VERSION 5.7 ;
  NOWIREEXTENSIONATPIN ON ;
  DIVIDERCHAR "/" ;
  BUSBITCHARS "[]" ;
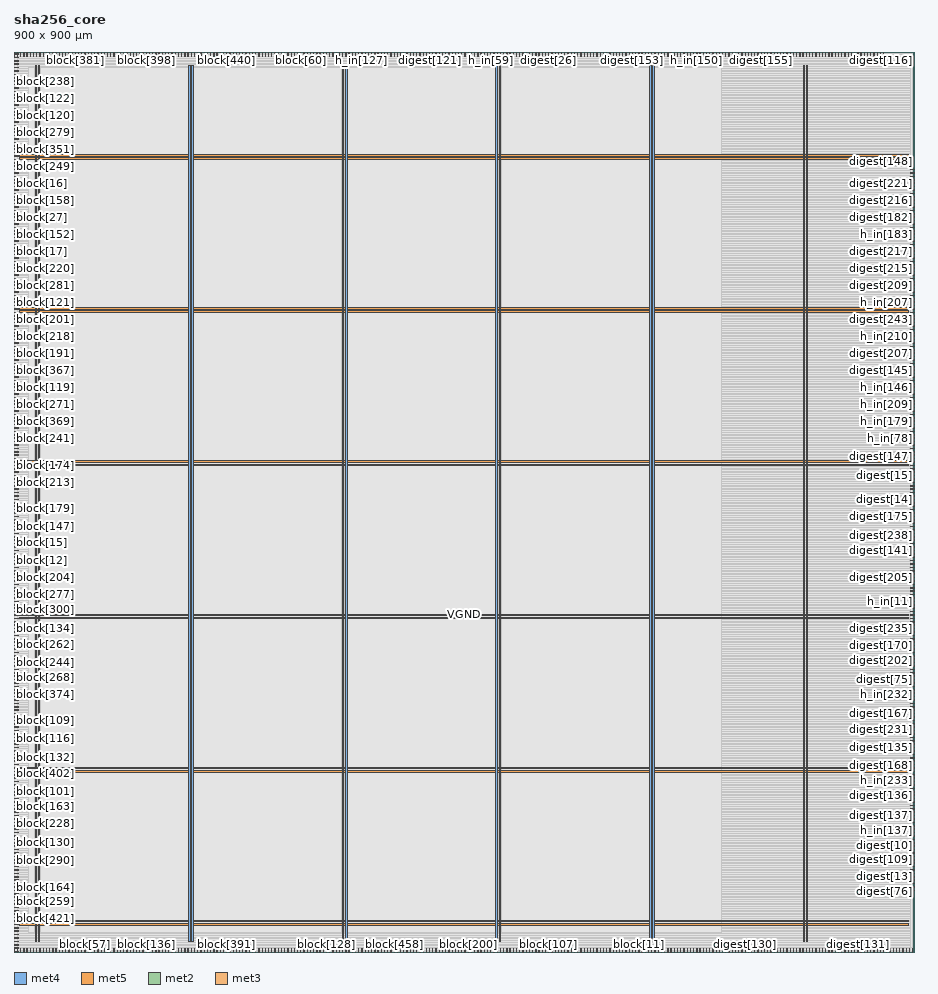
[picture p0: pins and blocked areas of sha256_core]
MACRO sha256_core
  CLASS BLOCK ;
  FOREIGN sha256_core ;
  ORIGIN 0.000 0.000 ;
  SIZE 900.000 BY 900.000 ;
  PIN VGND
    DIRECTION INOUT ;
    USE GROUND ;
    PORT
      LAYER met4 ;
        RECT 24.340 10.640 25.940 886.960 ;
    END
    PORT
      LAYER met4 ;
        RECT 177.940 10.640 179.540 886.960 ;
    END
    PORT
      LAYER met4 ;
        RECT 331.540 10.640 333.140 886.960 ;
    END
    PORT
      LAYER met4 ;
        RECT 485.140 10.640 486.740 886.960 ;
    END
    PORT
      LAYER met4 ;
        RECT 638.740 10.640 640.340 886.960 ;
    END
    PORT
      LAYER met4 ;
        RECT 792.340 10.640 793.940 886.960 ;
    END
    PORT
      LAYER met5 ;
        RECT 5.280 30.030 894.480 31.630 ;
    END
    PORT
      LAYER met5 ;
        RECT 5.280 183.210 894.480 184.810 ;
    END
    PORT
      LAYER met5 ;
        RECT 5.280 336.390 894.480 337.990 ;
    END
    PORT
      LAYER met5 ;
        RECT 5.280 489.570 894.480 491.170 ;
    END
    PORT
      LAYER met5 ;
        RECT 5.280 642.750 894.480 644.350 ;
    END
    PORT
      LAYER met5 ;
        RECT 5.280 795.930 894.480 797.530 ;
    END
  END VGND
  PIN VPWR
    DIRECTION INOUT ;
    USE POWER ;
    PORT
      LAYER met4 ;
        RECT 21.040 10.640 22.640 886.960 ;
    END
    PORT
      LAYER met4 ;
        RECT 174.640 10.640 176.240 886.960 ;
    END
    PORT
      LAYER met4 ;
        RECT 328.240 10.640 329.840 886.960 ;
    END
    PORT
      LAYER met4 ;
        RECT 481.840 10.640 483.440 886.960 ;
    END
    PORT
      LAYER met4 ;
        RECT 635.440 10.640 637.040 886.960 ;
    END
    PORT
      LAYER met4 ;
        RECT 789.040 10.640 790.640 886.960 ;
    END
    PORT
      LAYER met5 ;
        RECT 5.280 26.730 894.480 28.330 ;
    END
    PORT
      LAYER met5 ;
        RECT 5.280 179.910 894.480 181.510 ;
    END
    PORT
      LAYER met5 ;
        RECT 5.280 333.090 894.480 334.690 ;
    END
    PORT
      LAYER met5 ;
        RECT 5.280 486.270 894.480 487.870 ;
    END
    PORT
      LAYER met5 ;
        RECT 5.280 639.450 894.480 641.050 ;
    END
    PORT
      LAYER met5 ;
        RECT 5.280 792.630 894.480 794.230 ;
    END
  END VPWR
  PIN block[0]
    DIRECTION INPUT ;
    USE SIGNAL ;
    ANTENNAGATEAREA 0.631200 ;
    ANTENNADIFFAREA 0.434700 ;
    PORT
      LAYER met2 ;
        RECT 296.330 0.000 296.610 4.000 ;
    END
  END block[0]
  PIN block[100]
    DIRECTION INPUT ;
    USE SIGNAL ;
    ANTENNAGATEAREA 0.631200 ;
    ANTENNADIFFAREA 0.434700 ;
    PORT
      LAYER met3 ;
        RECT 0.000 302.640 4.000 303.240 ;
    END
  END block[100]
  PIN block[101]
    DIRECTION INPUT ;
    USE SIGNAL ;
    ANTENNAGATEAREA 0.631200 ;
    ANTENNADIFFAREA 0.434700 ;
    PORT
      LAYER met3 ;
        RECT 0.000 159.840 4.000 160.440 ;
    END
  END block[101]
  PIN block[102]
    DIRECTION INPUT ;
    USE SIGNAL ;
    ANTENNAGATEAREA 0.631200 ;
    ANTENNADIFFAREA 0.434700 ;
    PORT
      LAYER met3 ;
        RECT 0.000 353.640 4.000 354.240 ;
    END
  END block[102]
  PIN block[103]
    DIRECTION INPUT ;
    USE SIGNAL ;
    ANTENNAGATEAREA 0.631200 ;
    ANTENNADIFFAREA 0.434700 ;
    PORT
      LAYER met2 ;
        RECT 180.410 0.000 180.690 4.000 ;
    END
  END block[103]
  PIN block[104]
    DIRECTION INPUT ;
    USE SIGNAL ;
    ANTENNAGATEAREA 0.631200 ;
    ANTENNADIFFAREA 0.434700 ;
    PORT
      LAYER met2 ;
        RECT 116.010 0.000 116.290 4.000 ;
    END
  END block[104]
  PIN block[105]
    DIRECTION INPUT ;
    USE SIGNAL ;
    ANTENNAGATEAREA 0.631200 ;
    ANTENNADIFFAREA 0.434700 ;
    PORT
      LAYER met3 ;
        RECT 0.000 639.240 4.000 639.840 ;
    END
  END block[105]
  PIN block[106]
    DIRECTION INPUT ;
    USE SIGNAL ;
    ANTENNAGATEAREA 0.631200 ;
    ANTENNADIFFAREA 0.434700 ;
    PORT
      LAYER met3 ;
        RECT 0.000 887.440 4.000 888.040 ;
    END
  END block[106]
  PIN block[107]
    DIRECTION INPUT ;
    USE SIGNAL ;
    ANTENNAGATEAREA 0.631200 ;
    ANTENNADIFFAREA 0.434700 ;
    PORT
      LAYER met2 ;
        RECT 534.610 0.000 534.890 4.000 ;
    END
  END block[107]
  PIN block[108]
    DIRECTION INPUT ;
    USE SIGNAL ;
    ANTENNAGATEAREA 0.631200 ;
    ANTENNADIFFAREA 0.434700 ;
    PORT
      LAYER met3 ;
        RECT 0.000 377.440 4.000 378.040 ;
    END
  END block[108]
  PIN block[109]
    DIRECTION INPUT ;
    USE SIGNAL ;
    ANTENNAGATEAREA 0.631200 ;
    ANTENNADIFFAREA 0.434700 ;
    PORT
      LAYER met3 ;
        RECT 0.000 231.240 4.000 231.840 ;
    END
  END block[109]
  PIN block[10]
    DIRECTION INPUT ;
    USE SIGNAL ;
    ANTENNAGATEAREA 0.647700 ;
    ANTENNADIFFAREA 0.434700 ;
    PORT
      LAYER met2 ;
        RECT 344.630 0.000 344.910 4.000 ;
    END
  END block[10]
  PIN block[110]
    DIRECTION INPUT ;
    USE SIGNAL ;
    ANTENNAGATEAREA 0.631200 ;
    ANTENNADIFFAREA 0.434700 ;
    PORT
      LAYER met3 ;
        RECT 0.000 499.840 4.000 500.440 ;
    END
  END block[110]
  PIN block[111]
    DIRECTION INPUT ;
    USE SIGNAL ;
    ANTENNAGATEAREA 0.631200 ;
    ANTENNADIFFAREA 0.434700 ;
    PORT
      LAYER met3 ;
        RECT 0.000 676.640 4.000 677.240 ;
    END
  END block[111]
  PIN block[112]
    DIRECTION INPUT ;
    USE SIGNAL ;
    ANTENNAGATEAREA 0.631200 ;
    ANTENNADIFFAREA 0.434700 ;
    PORT
      LAYER met3 ;
        RECT 0.000 557.640 4.000 558.240 ;
    END
  END block[112]
  PIN block[113]
    DIRECTION INPUT ;
    USE SIGNAL ;
    ANTENNAGATEAREA 0.631200 ;
    ANTENNADIFFAREA 0.434700 ;
    PORT
      LAYER met3 ;
        RECT 0.000 523.640 4.000 524.240 ;
    END
  END block[113]
  PIN block[114]
    DIRECTION INPUT ;
    USE SIGNAL ;
    ANTENNAGATEAREA 0.631200 ;
    ANTENNADIFFAREA 0.434700 ;
    PORT
      LAYER met3 ;
        RECT 0.000 380.840 4.000 381.440 ;
    END
  END block[114]
  PIN block[115]
    DIRECTION INPUT ;
    USE SIGNAL ;
    ANTENNAGATEAREA 0.631200 ;
    ANTENNADIFFAREA 0.434700 ;
    PORT
      LAYER met3 ;
        RECT 0.000 363.840 4.000 364.440 ;
    END
  END block[115]
  PIN block[116]
    DIRECTION INPUT ;
    USE SIGNAL ;
    ANTENNAGATEAREA 0.631200 ;
    ANTENNADIFFAREA 0.434700 ;
    PORT
      LAYER met3 ;
        RECT 0.000 221.040 4.000 221.640 ;
    END
  END block[116]
  PIN block[117]
    DIRECTION INPUT ;
    USE SIGNAL ;
    ANTENNAGATEAREA 0.631200 ;
    ANTENNADIFFAREA 0.434700 ;
    PORT
      LAYER met3 ;
        RECT 0.000 496.440 4.000 497.040 ;
    END
  END block[117]
  PIN block[118]
    DIRECTION INPUT ;
    USE SIGNAL ;
    ANTENNAGATEAREA 0.631200 ;
    ANTENNADIFFAREA 0.434700 ;
    PORT
      LAYER met3 ;
        RECT 0.000 438.640 4.000 439.240 ;
    END
  END block[118]
  PIN block[119]
    DIRECTION INPUT ;
    USE SIGNAL ;
    ANTENNAGATEAREA 0.631200 ;
    ANTENNADIFFAREA 0.434700 ;
    PORT
      LAYER met3 ;
        RECT 0.000 564.440 4.000 565.040 ;
    END
  END block[119]
  PIN block[11]
    DIRECTION INPUT ;
    USE SIGNAL ;
    ANTENNAGATEAREA 0.593700 ;
    ANTENNADIFFAREA 0.434700 ;
    PORT
      LAYER met2 ;
        RECT 624.770 0.000 625.050 4.000 ;
    END
  END block[11]
  PIN block[120]
    DIRECTION INPUT ;
    USE SIGNAL ;
    ANTENNAGATEAREA 0.631200 ;
    ANTENNADIFFAREA 0.434700 ;
    PORT
      LAYER met3 ;
        RECT 0.000 836.440 4.000 837.040 ;
    END
  END block[120]
  PIN block[121]
    DIRECTION INPUT ;
    USE SIGNAL ;
    ANTENNAGATEAREA 0.631200 ;
    ANTENNADIFFAREA 0.434700 ;
    PORT
      LAYER met3 ;
        RECT 0.000 649.440 4.000 650.040 ;
    END
  END block[121]
  PIN block[122]
    DIRECTION INPUT ;
    USE SIGNAL ;
    ANTENNAGATEAREA 0.631200 ;
    ANTENNADIFFAREA 0.434700 ;
    PORT
      LAYER met3 ;
        RECT 0.000 853.440 4.000 854.040 ;
    END
  END block[122]
  PIN block[123]
    DIRECTION INPUT ;
    USE SIGNAL ;
    ANTENNAGATEAREA 0.631200 ;
    ANTENNADIFFAREA 0.434700 ;
    PORT
      LAYER met2 ;
        RECT 225.490 896.000 225.770 900.000 ;
    END
  END block[123]
  PIN block[124]
    DIRECTION INPUT ;
    USE SIGNAL ;
    ANTENNAGATEAREA 0.631200 ;
    ANTENNADIFFAREA 0.434700 ;
    PORT
      LAYER met3 ;
        RECT 0.000 765.040 4.000 765.640 ;
    END
  END block[124]
  PIN block[125]
    DIRECTION INPUT ;
    USE SIGNAL ;
    ANTENNAGATEAREA 0.631200 ;
    ANTENNADIFFAREA 0.434700 ;
    PORT
      LAYER met2 ;
        RECT 167.530 896.000 167.810 900.000 ;
    END
  END block[125]
  PIN block[126]
    DIRECTION INPUT ;
    USE SIGNAL ;
    ANTENNAGATEAREA 0.631200 ;
    ANTENNADIFFAREA 0.434700 ;
    PORT
      LAYER met3 ;
        RECT 0.000 646.040 4.000 646.640 ;
    END
  END block[126]
  PIN block[127]
    DIRECTION INPUT ;
    USE SIGNAL ;
    ANTENNAGATEAREA 0.631200 ;
    ANTENNADIFFAREA 0.434700 ;
    PORT
      LAYER met3 ;
        RECT 0.000 686.840 4.000 687.440 ;
    END
  END block[127]
  PIN block[128]
    DIRECTION INPUT ;
    USE SIGNAL ;
    ANTENNAGATEAREA 0.631200 ;
    ANTENNADIFFAREA 0.434700 ;
    PORT
      LAYER met2 ;
        RECT 312.430 0.000 312.710 4.000 ;
    END
  END block[128]
  PIN block[129]
    DIRECTION INPUT ;
    USE SIGNAL ;
    ANTENNAGATEAREA 0.631200 ;
    ANTENNADIFFAREA 0.434700 ;
    PORT
      LAYER met2 ;
        RECT 106.350 0.000 106.630 4.000 ;
    END
  END block[129]
  PIN block[12]
    DIRECTION INPUT ;
    USE SIGNAL ;
    ANTENNAGATEAREA 0.631200 ;
    ANTENNADIFFAREA 0.434700 ;
    PORT
      LAYER met3 ;
        RECT 0.000 391.040 4.000 391.640 ;
    END
  END block[12]
  PIN block[130]
    DIRECTION INPUT ;
    USE SIGNAL ;
    ANTENNAGATEAREA 0.560700 ;
    ANTENNADIFFAREA 0.434700 ;
    PORT
      LAYER met3 ;
        RECT 0.000 108.840 4.000 109.440 ;
    END
  END block[130]
  PIN block[131]
    DIRECTION INPUT ;
    USE SIGNAL ;
    ANTENNAGATEAREA 0.631200 ;
    ANTENNADIFFAREA 0.434700 ;
    PORT
      LAYER met3 ;
        RECT 0.000 37.440 4.000 38.040 ;
    END
  END block[131]
  PIN block[132]
    DIRECTION INPUT ;
    USE SIGNAL ;
    ANTENNAGATEAREA 0.631200 ;
    ANTENNADIFFAREA 0.434700 ;
    PORT
      LAYER met3 ;
        RECT 0.000 193.840 4.000 194.440 ;
    END
  END block[132]
  PIN block[133]
    DIRECTION INPUT ;
    USE SIGNAL ;
    ANTENNAGATEAREA 0.631200 ;
    ANTENNADIFFAREA 0.434700 ;
    PORT
      LAYER met3 ;
        RECT 0.000 197.240 4.000 197.840 ;
    END
  END block[133]
  PIN block[134]
    DIRECTION INPUT ;
    USE SIGNAL ;
    ANTENNAGATEAREA 0.631200 ;
    ANTENNADIFFAREA 0.434700 ;
    PORT
      LAYER met3 ;
        RECT 0.000 323.040 4.000 323.640 ;
    END
  END block[134]
  PIN block[135]
    DIRECTION INPUT ;
    USE SIGNAL ;
    ANTENNAGATEAREA 0.631200 ;
    ANTENNADIFFAREA 0.434700 ;
    PORT
      LAYER met2 ;
        RECT 58.050 0.000 58.330 4.000 ;
    END
  END block[135]
  PIN block[136]
    DIRECTION INPUT ;
    USE SIGNAL ;
    ANTENNAGATEAREA 0.631200 ;
    ANTENNADIFFAREA 0.434700 ;
    PORT
      LAYER met2 ;
        RECT 132.110 0.000 132.390 4.000 ;
    END
  END block[136]
  PIN block[137]
    DIRECTION INPUT ;
    USE SIGNAL ;
    ANTENNAGATEAREA 0.631200 ;
    ANTENNADIFFAREA 0.434700 ;
    PORT
      LAYER met3 ;
        RECT 0.000 778.640 4.000 779.240 ;
    END
  END block[137]
  PIN block[138]
    DIRECTION INPUT ;
    USE SIGNAL ;
    ANTENNAGATEAREA 0.631200 ;
    ANTENNADIFFAREA 0.434700 ;
    PORT
      LAYER met3 ;
        RECT 0.000 884.040 4.000 884.640 ;
    END
  END block[138]
  PIN block[139]
    DIRECTION INPUT ;
    USE SIGNAL ;
    ANTENNAGATEAREA 0.631200 ;
    ANTENNADIFFAREA 0.434700 ;
    PORT
      LAYER met2 ;
        RECT 502.410 0.000 502.690 4.000 ;
    END
  END block[139]
  PIN block[13]
    DIRECTION INPUT ;
    USE SIGNAL ;
    ANTENNAGATEAREA 0.647700 ;
    ANTENNADIFFAREA 0.434700 ;
    PORT
      LAYER met2 ;
        RECT 29.070 0.000 29.350 4.000 ;
    END
  END block[13]
  PIN block[140]
    DIRECTION INPUT ;
    USE SIGNAL ;
    ANTENNAGATEAREA 0.631200 ;
    ANTENNADIFFAREA 0.434700 ;
    PORT
      LAYER met3 ;
        RECT 0.000 258.440 4.000 259.040 ;
    END
  END block[140]
  PIN block[141]
    DIRECTION INPUT ;
    USE SIGNAL ;
    ANTENNAGATEAREA 0.631200 ;
    ANTENNADIFFAREA 0.434700 ;
    PORT
      LAYER met3 ;
        RECT 0.000 414.840 4.000 415.440 ;
    END
  END block[141]
  PIN block[142]
    DIRECTION INPUT ;
    USE SIGNAL ;
    ANTENNAGATEAREA 0.631200 ;
    ANTENNADIFFAREA 0.434700 ;
    PORT
      LAYER met3 ;
        RECT 0.000 489.640 4.000 490.240 ;
    END
  END block[142]
  PIN block[143]
    DIRECTION INPUT ;
    USE SIGNAL ;
    ANTENNAGATEAREA 0.631200 ;
    ANTENNADIFFAREA 0.434700 ;
    PORT
      LAYER met3 ;
        RECT 0.000 714.040 4.000 714.640 ;
    END
  END block[143]
  PIN block[144]
    DIRECTION INPUT ;
    USE SIGNAL ;
    ANTENNAGATEAREA 0.631200 ;
    ANTENNADIFFAREA 0.434700 ;
    PORT
      LAYER met3 ;
        RECT 0.000 591.640 4.000 592.240 ;
    END
  END block[144]
  PIN block[145]
    DIRECTION INPUT ;
    USE SIGNAL ;
    ANTENNAGATEAREA 0.647700 ;
    ANTENNADIFFAREA 0.434700 ;
    PORT
      LAYER met3 ;
        RECT 0.000 748.040 4.000 748.640 ;
    END
  END block[145]
  PIN block[146]
    DIRECTION INPUT ;
    USE SIGNAL ;
    ANTENNAGATEAREA 0.631200 ;
    ANTENNADIFFAREA 0.434700 ;
    PORT
      LAYER met3 ;
        RECT 0.000 244.840 4.000 245.440 ;
    END
  END block[146]
  PIN block[147]
    DIRECTION INPUT ;
    USE SIGNAL ;
    ANTENNAGATEAREA 0.631200 ;
    ANTENNADIFFAREA 0.434700 ;
    PORT
      LAYER met3 ;
        RECT 0.000 425.040 4.000 425.640 ;
    END
  END block[147]
  PIN block[148]
    DIRECTION INPUT ;
    USE SIGNAL ;
    ANTENNAGATEAREA 0.631200 ;
    ANTENNADIFFAREA 0.434700 ;
    PORT
      LAYER met3 ;
        RECT 0.000 319.640 4.000 320.240 ;
    END
  END block[148]
  PIN block[149]
    DIRECTION INPUT ;
    USE SIGNAL ;
    ANTENNAGATEAREA 0.631200 ;
    ANTENNADIFFAREA 0.434700 ;
    PORT
      LAYER met3 ;
        RECT 0.000 472.640 4.000 473.240 ;
    END
  END block[149]
  PIN block[14]
    DIRECTION INPUT ;
    USE SIGNAL ;
    ANTENNAGATEAREA 0.631200 ;
    ANTENNADIFFAREA 0.434700 ;
    PORT
      LAYER met3 ;
        RECT 0.000 411.440 4.000 412.040 ;
    END
  END block[14]
  PIN block[150]
    DIRECTION INPUT ;
    USE SIGNAL ;
    ANTENNAGATEAREA 0.631200 ;
    ANTENNADIFFAREA 0.434700 ;
    PORT
      LAYER met3 ;
        RECT 0.000 251.640 4.000 252.240 ;
    END
  END block[150]
  PIN block[151]
    DIRECTION INPUT ;
    USE SIGNAL ;
    ANTENNAGATEAREA 0.631200 ;
    ANTENNADIFFAREA 0.434700 ;
    PORT
      LAYER met3 ;
        RECT 0.000 588.240 4.000 588.840 ;
    END
  END block[151]
  PIN block[152]
    DIRECTION INPUT ;
    USE SIGNAL ;
    ANTENNAGATEAREA 0.631200 ;
    ANTENNADIFFAREA 0.434700 ;
    PORT
      LAYER met3 ;
        RECT 0.000 717.440 4.000 718.040 ;
    END
  END block[152]
  PIN block[153]
    DIRECTION INPUT ;
    USE SIGNAL ;
    ANTENNAGATEAREA 0.631200 ;
    ANTENNADIFFAREA 0.434700 ;
    PORT
      LAYER met3 ;
        RECT 0.000 839.840 4.000 840.440 ;
    END
  END block[153]
  PIN block[154]
    DIRECTION INPUT ;
    USE SIGNAL ;
    ANTENNAGATEAREA 0.631200 ;
    ANTENNADIFFAREA 0.434700 ;
    PORT
      LAYER met3 ;
        RECT 0.000 799.040 4.000 799.640 ;
    END
  END block[154]
  PIN block[155]
    DIRECTION INPUT ;
    USE SIGNAL ;
    ANTENNAGATEAREA 0.631200 ;
    ANTENNADIFFAREA 0.434700 ;
    PORT
      LAYER met2 ;
        RECT 151.430 896.000 151.710 900.000 ;
    END
  END block[155]
  PIN block[156]
    DIRECTION INPUT ;
    USE SIGNAL ;
    ANTENNAGATEAREA 0.631200 ;
    ANTENNADIFFAREA 0.434700 ;
    PORT
      LAYER met3 ;
        RECT 0.000 826.240 4.000 826.840 ;
    END
  END block[156]
  PIN block[157]
    DIRECTION INPUT ;
    USE SIGNAL ;
    ANTENNAGATEAREA 0.631200 ;
    ANTENNADIFFAREA 0.434700 ;
    PORT
      LAYER met2 ;
        RECT 64.490 896.000 64.770 900.000 ;
    END
  END block[157]
  PIN block[158]
    DIRECTION INPUT ;
    USE SIGNAL ;
    ANTENNAGATEAREA 0.631200 ;
    ANTENNADIFFAREA 0.434700 ;
    PORT
      LAYER met3 ;
        RECT 0.000 751.440 4.000 752.040 ;
    END
  END block[158]
  PIN block[159]
    DIRECTION INPUT ;
    USE SIGNAL ;
    ANTENNAGATEAREA 0.631200 ;
    ANTENNADIFFAREA 0.434700 ;
    PORT
      LAYER met3 ;
        RECT 0.000 822.840 4.000 823.440 ;
    END
  END block[159]
  PIN block[15]
    DIRECTION INPUT ;
    USE SIGNAL ;
    ANTENNAGATEAREA 0.631200 ;
    ANTENNADIFFAREA 0.434700 ;
    PORT
      LAYER met3 ;
        RECT 0.000 401.240 4.000 401.840 ;
    END
  END block[15]
  PIN block[160]
    DIRECTION INPUT ;
    USE SIGNAL ;
    ANTENNAGATEAREA 0.631200 ;
    ANTENNADIFFAREA 0.434700 ;
    PORT
      LAYER met2 ;
        RECT 360.730 0.000 361.010 4.000 ;
    END
  END block[160]
  PIN block[161]
    DIRECTION INPUT ;
    USE SIGNAL ;
    ANTENNAGATEAREA 0.631200 ;
    ANTENNADIFFAREA 0.434700 ;
    PORT
      LAYER met2 ;
        RECT 186.850 0.000 187.130 4.000 ;
    END
  END block[161]
  PIN block[162]
    DIRECTION INPUT ;
    USE SIGNAL ;
    ANTENNAGATEAREA 0.631200 ;
    ANTENNADIFFAREA 0.434700 ;
    PORT
      LAYER met2 ;
        RECT 209.390 0.000 209.670 4.000 ;
    END
  END block[162]
  PIN block[163]
    DIRECTION INPUT ;
    USE SIGNAL ;
    ANTENNAGATEAREA 0.631200 ;
    ANTENNADIFFAREA 0.434700 ;
    PORT
      LAYER met3 ;
        RECT 0.000 153.040 4.000 153.640 ;
    END
  END block[163]
  PIN block[164]
    DIRECTION INPUT ;
    USE SIGNAL ;
    ANTENNAGATEAREA 0.631200 ;
    ANTENNADIFFAREA 0.434700 ;
    PORT
      LAYER met3 ;
        RECT 0.000 64.640 4.000 65.240 ;
    END
  END block[164]
  PIN block[165]
    DIRECTION INPUT ;
    USE SIGNAL ;
    ANTENNAGATEAREA 0.631200 ;
    ANTENNADIFFAREA 0.434700 ;
    PORT
      LAYER met3 ;
        RECT 0.000 6.840 4.000 7.440 ;
    END
  END block[165]
  PIN block[166]
    DIRECTION INPUT ;
    USE SIGNAL ;
    ANTENNAGATEAREA 0.631200 ;
    ANTENNADIFFAREA 0.434700 ;
    PORT
      LAYER met3 ;
        RECT 0.000 309.440 4.000 310.040 ;
    END
  END block[166]
  PIN block[167]
    DIRECTION INPUT ;
    USE SIGNAL ;
    ANTENNAGATEAREA 0.631200 ;
    ANTENNADIFFAREA 0.434700 ;
    PORT
      LAYER met2 ;
        RECT 51.610 0.000 51.890 4.000 ;
    END
  END block[167]
  PIN block[168]
    DIRECTION INPUT ;
    USE SIGNAL ;
    ANTENNAGATEAREA 0.631200 ;
    ANTENNADIFFAREA 0.434700 ;
    PORT
      LAYER met2 ;
        RECT 325.310 0.000 325.590 4.000 ;
    END
  END block[168]
  PIN block[169]
    DIRECTION INPUT ;
    USE SIGNAL ;
    ANTENNAGATEAREA 0.631200 ;
    ANTENNADIFFAREA 0.434700 ;
    PORT
      LAYER met3 ;
        RECT 0.000 856.840 4.000 857.440 ;
    END
  END block[169]
  PIN block[16]
    DIRECTION INPUT ;
    USE SIGNAL ;
    ANTENNAGATEAREA 0.593700 ;
    ANTENNADIFFAREA 0.434700 ;
    PORT
      LAYER met3 ;
        RECT 0.000 768.440 4.000 769.040 ;
    END
  END block[16]
  PIN block[170]
    DIRECTION INPUT ;
    USE SIGNAL ;
    ANTENNAGATEAREA 0.631200 ;
    ANTENNADIFFAREA 0.434700 ;
    PORT
      LAYER met3 ;
        RECT 0.000 867.040 4.000 867.640 ;
    END
  END block[170]
  PIN block[171]
    DIRECTION INPUT ;
    USE SIGNAL ;
    ANTENNAGATEAREA 0.631200 ;
    ANTENNADIFFAREA 0.434700 ;
    PORT
      LAYER met2 ;
        RECT 611.890 0.000 612.170 4.000 ;
    END
  END block[171]
  PIN block[172]
    DIRECTION INPUT ;
    USE SIGNAL ;
    ANTENNAGATEAREA 0.631200 ;
    ANTENNADIFFAREA 0.434700 ;
    PORT
      LAYER met3 ;
        RECT 0.000 268.640 4.000 269.240 ;
    END
  END block[172]
  PIN block[173]
    DIRECTION INPUT ;
    USE SIGNAL ;
    ANTENNAGATEAREA 0.631200 ;
    ANTENNADIFFAREA 0.434700 ;
    PORT
      LAYER met3 ;
        RECT 0.000 404.640 4.000 405.240 ;
    END
  END block[173]
  PIN block[174]
    DIRECTION INPUT ;
    USE SIGNAL ;
    ANTENNAGATEAREA 0.631200 ;
    ANTENNADIFFAREA 0.434700 ;
    PORT
      LAYER met3 ;
        RECT 0.000 486.240 4.000 486.840 ;
    END
  END block[174]
  PIN block[175]
    DIRECTION INPUT ;
    USE SIGNAL ;
    ANTENNAGATEAREA 0.631200 ;
    ANTENNADIFFAREA 0.434700 ;
    PORT
      LAYER met3 ;
        RECT 0.000 537.240 4.000 537.840 ;
    END
  END block[175]
  PIN block[176]
    DIRECTION INPUT ;
    USE SIGNAL ;
    ANTENNAGATEAREA 0.631200 ;
    ANTENNADIFFAREA 0.434700 ;
    PORT
      LAYER met3 ;
        RECT 0.000 550.840 4.000 551.440 ;
    END
  END block[176]
  PIN block[177]
    DIRECTION INPUT ;
    USE SIGNAL ;
    ANTENNAGATEAREA 0.631200 ;
    ANTENNADIFFAREA 0.434700 ;
    PORT
      LAYER met3 ;
        RECT 0.000 516.840 4.000 517.440 ;
    END
  END block[177]
  PIN block[178]
    DIRECTION INPUT ;
    USE SIGNAL ;
    ANTENNAGATEAREA 0.631200 ;
    ANTENNADIFFAREA 0.434700 ;
    PORT
      LAYER met3 ;
        RECT 0.000 238.040 4.000 238.640 ;
    END
  END block[178]
  PIN block[179]
    DIRECTION INPUT ;
    USE SIGNAL ;
    ANTENNAGATEAREA 0.631200 ;
    ANTENNADIFFAREA 0.434700 ;
    PORT
      LAYER met3 ;
        RECT 0.000 435.240 4.000 435.840 ;
    END
  END block[179]
  PIN block[17]
    DIRECTION INPUT ;
    USE SIGNAL ;
    ANTENNAGATEAREA 0.631200 ;
    ANTENNADIFFAREA 0.434700 ;
    PORT
      LAYER met3 ;
        RECT 0.000 700.440 4.000 701.040 ;
    END
  END block[17]
  PIN block[180]
    DIRECTION INPUT ;
    USE SIGNAL ;
    ANTENNAGATEAREA 0.631200 ;
    ANTENNADIFFAREA 0.434700 ;
    PORT
      LAYER met3 ;
        RECT 0.000 227.840 4.000 228.440 ;
    END
  END block[180]
  PIN block[181]
    DIRECTION INPUT ;
    USE SIGNAL ;
    ANTENNAGATEAREA 0.593700 ;
    ANTENNADIFFAREA 0.434700 ;
    PORT
      LAYER met3 ;
        RECT 0.000 897.640 4.000 898.240 ;
    END
  END block[181]
  PIN block[182]
    DIRECTION INPUT ;
    USE SIGNAL ;
    ANTENNAGATEAREA 0.631200 ;
    ANTENNADIFFAREA 0.434700 ;
    PORT
      LAYER met3 ;
        RECT 0.000 397.840 4.000 398.440 ;
    END
  END block[182]
  PIN block[183]
    DIRECTION INPUT ;
    USE SIGNAL ;
    ANTENNAGATEAREA 0.631200 ;
    ANTENNADIFFAREA 0.434700 ;
    PORT
      LAYER met3 ;
        RECT 0.000 578.040 4.000 578.640 ;
    END
  END block[183]
  PIN block[184]
    DIRECTION INPUT ;
    USE SIGNAL ;
    ANTENNAGATEAREA 0.631200 ;
    ANTENNADIFFAREA 0.434700 ;
    PORT
      LAYER met3 ;
        RECT 0.000 710.640 4.000 711.240 ;
    END
  END block[184]
  PIN block[185]
    DIRECTION INPUT ;
    USE SIGNAL ;
    ANTENNAGATEAREA 0.631200 ;
    ANTENNADIFFAREA 0.434700 ;
    PORT
      LAYER met3 ;
        RECT 0.000 843.240 4.000 843.840 ;
    END
  END block[185]
  PIN block[186]
    DIRECTION INPUT ;
    USE SIGNAL ;
    ANTENNAGATEAREA 0.631200 ;
    ANTENNADIFFAREA 0.434700 ;
    PORT
      LAYER met3 ;
        RECT 0.000 680.040 4.000 680.640 ;
    END
  END block[186]
  PIN block[187]
    DIRECTION INPUT ;
    USE SIGNAL ;
    ANTENNAGATEAREA 0.631200 ;
    ANTENNADIFFAREA 0.434700 ;
    PORT
      LAYER met2 ;
        RECT 29.070 896.000 29.350 900.000 ;
    END
  END block[187]
  PIN block[188]
    DIRECTION INPUT ;
    USE SIGNAL ;
    ANTENNAGATEAREA 0.631200 ;
    ANTENNADIFFAREA 0.434700 ;
    PORT
      LAYER met3 ;
        RECT 0.000 761.640 4.000 762.240 ;
    END
  END block[188]
  PIN block[189]
    DIRECTION INPUT ;
    USE SIGNAL ;
    ANTENNAGATEAREA 0.631200 ;
    ANTENNADIFFAREA 0.434700 ;
    PORT
      LAYER met2 ;
        RECT 48.390 896.000 48.670 900.000 ;
    END
  END block[189]
  PIN block[18]
    DIRECTION INPUT ;
    USE SIGNAL ;
    ANTENNAGATEAREA 0.593700 ;
    ANTENNADIFFAREA 0.434700 ;
    PORT
      LAYER met3 ;
        RECT 0.000 690.240 4.000 690.840 ;
    END
  END block[18]
  PIN block[190]
    DIRECTION INPUT ;
    USE SIGNAL ;
    ANTENNAGATEAREA 0.631200 ;
    ANTENNADIFFAREA 0.434700 ;
    PORT
      LAYER met3 ;
        RECT 0.000 795.640 4.000 796.240 ;
    END
  END block[190]
  PIN block[191]
    DIRECTION INPUT ;
    USE SIGNAL ;
    ANTENNAGATEAREA 0.631200 ;
    ANTENNADIFFAREA 0.434700 ;
    PORT
      LAYER met3 ;
        RECT 0.000 598.440 4.000 599.040 ;
    END
  END block[191]
  PIN block[192]
    DIRECTION INPUT ;
    USE SIGNAL ;
    ANTENNAGATEAREA 0.631200 ;
    ANTENNADIFFAREA 0.434700 ;
    PORT
      LAYER met2 ;
        RECT 396.150 0.000 396.430 4.000 ;
    END
  END block[192]
  PIN block[193]
    DIRECTION INPUT ;
    USE SIGNAL ;
    ANTENNAGATEAREA 0.631200 ;
    ANTENNADIFFAREA 0.434700 ;
    PORT
      LAYER met2 ;
        RECT 257.690 0.000 257.970 4.000 ;
    END
  END block[193]
  PIN block[194]
    DIRECTION INPUT ;
    USE SIGNAL ;
    ANTENNAGATEAREA 0.631200 ;
    ANTENNADIFFAREA 0.434700 ;
    PORT
      LAYER met2 ;
        RECT 125.670 0.000 125.950 4.000 ;
    END
  END block[194]
  PIN block[195]
    DIRECTION INPUT ;
    USE SIGNAL ;
    ANTENNAGATEAREA 0.631200 ;
    ANTENNADIFFAREA 0.434700 ;
    PORT
      LAYER met3 ;
        RECT 0.000 44.240 4.000 44.840 ;
    END
  END block[195]
  PIN block[196]
    DIRECTION INPUT ;
    USE SIGNAL ;
    ANTENNAGATEAREA 0.631200 ;
    ANTENNADIFFAREA 0.434700 ;
    PORT
      LAYER met3 ;
        RECT 0.000 78.240 4.000 78.840 ;
    END
  END block[196]
  PIN block[197]
    DIRECTION INPUT ;
    USE SIGNAL ;
    ANTENNAGATEAREA 0.631200 ;
    ANTENNADIFFAREA 0.434700 ;
    PORT
      LAYER met3 ;
        RECT 0.000 183.640 4.000 184.240 ;
    END
  END block[197]
  PIN block[198]
    DIRECTION INPUT ;
    USE SIGNAL ;
    ANTENNAGATEAREA 0.631200 ;
    ANTENNADIFFAREA 0.434700 ;
    PORT
      LAYER met3 ;
        RECT 0.000 292.440 4.000 293.040 ;
    END
  END block[198]
  PIN block[199]
    DIRECTION INPUT ;
    USE SIGNAL ;
    ANTENNAGATEAREA 0.631200 ;
    ANTENNADIFFAREA 0.434700 ;
    PORT
      LAYER met2 ;
        RECT 222.270 0.000 222.550 4.000 ;
    END
  END block[199]
  PIN block[19]
    DIRECTION INPUT ;
    USE SIGNAL ;
    ANTENNAGATEAREA 0.647700 ;
    ANTENNADIFFAREA 0.434700 ;
    PORT
      LAYER met3 ;
        RECT 0.000 860.240 4.000 860.840 ;
    END
  END block[19]
  PIN block[1]
    DIRECTION INPUT ;
    USE SIGNAL ;
    ANTENNAGATEAREA 0.631200 ;
    ANTENNADIFFAREA 0.434700 ;
    PORT
      LAYER met2 ;
        RECT 80.590 0.000 80.870 4.000 ;
    END
  END block[1]
  PIN block[200]
    DIRECTION INPUT ;
    USE SIGNAL ;
    ANTENNAGATEAREA 0.631200 ;
    ANTENNADIFFAREA 0.434700 ;
    PORT
      LAYER met2 ;
        RECT 454.110 0.000 454.390 4.000 ;
    END
  END block[200]
  PIN block[201]
    DIRECTION INPUT ;
    USE SIGNAL ;
    ANTENNAGATEAREA 0.631200 ;
    ANTENNADIFFAREA 0.434700 ;
    PORT
      LAYER met3 ;
        RECT 0.000 632.440 4.000 633.040 ;
    END
  END block[201]
  PIN block[202]
    DIRECTION INPUT ;
    USE SIGNAL ;
    ANTENNAGATEAREA 0.631200 ;
    ANTENNADIFFAREA 0.434700 ;
    PORT
      LAYER met3 ;
        RECT 0.000 894.240 4.000 894.840 ;
    END
  END block[202]
  PIN block[203]
    DIRECTION INPUT ;
    USE SIGNAL ;
    ANTENNAGATEAREA 0.631200 ;
    ANTENNADIFFAREA 0.434700 ;
    PORT
      LAYER met2 ;
        RECT 615.110 0.000 615.390 4.000 ;
    END
  END block[203]
  PIN block[204]
    DIRECTION INPUT ;
    USE SIGNAL ;
    ANTENNAGATEAREA 0.631200 ;
    ANTENNADIFFAREA 0.434700 ;
    PORT
      LAYER met3 ;
        RECT 0.000 374.040 4.000 374.640 ;
    END
  END block[204]
  PIN block[205]
    DIRECTION INPUT ;
    USE SIGNAL ;
    ANTENNAGATEAREA 0.631200 ;
    ANTENNADIFFAREA 0.434700 ;
    PORT
      LAYER met3 ;
        RECT 0.000 428.440 4.000 429.040 ;
    END
  END block[205]
  PIN block[206]
    DIRECTION INPUT ;
    USE SIGNAL ;
    ANTENNAGATEAREA 0.631200 ;
    ANTENNADIFFAREA 0.434700 ;
    PORT
      LAYER met3 ;
        RECT 0.000 479.440 4.000 480.040 ;
    END
  END block[206]
  PIN block[207]
    DIRECTION INPUT ;
    USE SIGNAL ;
    ANTENNAGATEAREA 0.631200 ;
    ANTENNADIFFAREA 0.434700 ;
    PORT
      LAYER met3 ;
        RECT 0.000 788.840 4.000 789.440 ;
    END
  END block[207]
  PIN block[208]
    DIRECTION INPUT ;
    USE SIGNAL ;
    ANTENNAGATEAREA 0.631200 ;
    ANTENNADIFFAREA 0.434700 ;
    PORT
      LAYER met3 ;
        RECT 0.000 618.840 4.000 619.440 ;
    END
  END block[208]
  PIN block[209]
    DIRECTION INPUT ;
    USE SIGNAL ;
    ANTENNAGATEAREA 0.631200 ;
    ANTENNADIFFAREA 0.434700 ;
    PORT
      LAYER met3 ;
        RECT 0.000 510.040 4.000 510.640 ;
    END
  END block[209]
  PIN block[20]
    DIRECTION INPUT ;
    USE SIGNAL ;
    ANTENNAGATEAREA 0.631200 ;
    ANTENNADIFFAREA 0.434700 ;
    PORT
      LAYER met3 ;
        RECT 0.000 493.040 4.000 493.640 ;
    END
  END block[20]
  PIN block[210]
    DIRECTION INPUT ;
    USE SIGNAL ;
    ANTENNAGATEAREA 0.631200 ;
    ANTENNADIFFAREA 0.434700 ;
    PORT
      LAYER met3 ;
        RECT 0.000 336.640 4.000 337.240 ;
    END
  END block[210]
  PIN block[211]
    DIRECTION INPUT ;
    USE SIGNAL ;
    ANTENNAGATEAREA 0.631200 ;
    ANTENNADIFFAREA 0.434700 ;
    PORT
      LAYER met3 ;
        RECT 0.000 408.040 4.000 408.640 ;
    END
  END block[211]
  PIN block[212]
    DIRECTION INPUT ;
    USE SIGNAL ;
    ANTENNAGATEAREA 0.631200 ;
    ANTENNADIFFAREA 0.434700 ;
    PORT
      LAYER met3 ;
        RECT 0.000 312.840 4.000 313.440 ;
    END
  END block[212]
  PIN block[213]
    DIRECTION INPUT ;
    USE SIGNAL ;
    ANTENNAGATEAREA 0.631200 ;
    ANTENNADIFFAREA 0.434700 ;
    PORT
      LAYER met3 ;
        RECT 0.000 469.240 4.000 469.840 ;
    END
  END block[213]
  PIN block[214]
    DIRECTION INPUT ;
    USE SIGNAL ;
    ANTENNAGATEAREA 0.631200 ;
    ANTENNADIFFAREA 0.434700 ;
    PORT
      LAYER met3 ;
        RECT 0.000 421.640 4.000 422.240 ;
    END
  END block[214]
  PIN block[215]
    DIRECTION INPUT ;
    USE SIGNAL ;
    ANTENNAGATEAREA 0.631200 ;
    ANTENNADIFFAREA 0.434700 ;
    PORT
      LAYER met3 ;
        RECT 0.000 584.840 4.000 585.440 ;
    END
  END block[215]
  PIN block[216]
    DIRECTION INPUT ;
    USE SIGNAL ;
    ANTENNAGATEAREA 0.631200 ;
    ANTENNADIFFAREA 0.434700 ;
    PORT
      LAYER met3 ;
        RECT 0.000 697.040 4.000 697.640 ;
    END
  END block[216]
  PIN block[217]
    DIRECTION INPUT ;
    USE SIGNAL ;
    ANTENNAGATEAREA 0.631200 ;
    ANTENNADIFFAREA 0.434700 ;
    PORT
      LAYER met3 ;
        RECT 0.000 656.240 4.000 656.840 ;
    END
  END block[217]
  PIN block[218]
    DIRECTION INPUT ;
    USE SIGNAL ;
    ANTENNAGATEAREA 0.631200 ;
    ANTENNADIFFAREA 0.434700 ;
    PORT
      LAYER met3 ;
        RECT 0.000 615.440 4.000 616.040 ;
    END
  END block[218]
  PIN block[219]
    DIRECTION INPUT ;
    USE SIGNAL ;
    ANTENNAGATEAREA 0.631200 ;
    ANTENNADIFFAREA 0.434700 ;
    PORT
      LAYER met2 ;
        RECT 80.590 896.000 80.870 900.000 ;
    END
  END block[219]
  PIN block[21]
    DIRECTION INPUT ;
    USE SIGNAL ;
    ANTENNAGATEAREA 0.593700 ;
    ANTENNADIFFAREA 0.434700 ;
    PORT
      LAYER met3 ;
        RECT 0.000 608.640 4.000 609.240 ;
    END
  END block[21]
  PIN block[220]
    DIRECTION INPUT ;
    USE SIGNAL ;
    ANTENNAGATEAREA 0.631200 ;
    ANTENNADIFFAREA 0.434700 ;
    PORT
      LAYER met3 ;
        RECT 0.000 683.440 4.000 684.040 ;
    END
  END block[220]
  PIN block[221]
    DIRECTION INPUT ;
    USE SIGNAL ;
    ANTENNAGATEAREA 0.631200 ;
    ANTENNADIFFAREA 0.434700 ;
    PORT
      LAYER met2 ;
        RECT 209.390 896.000 209.670 900.000 ;
    END
  END block[221]
  PIN block[222]
    DIRECTION INPUT ;
    USE SIGNAL ;
    ANTENNAGATEAREA 0.631200 ;
    ANTENNADIFFAREA 0.434700 ;
    PORT
      LAYER met3 ;
        RECT 0.000 731.040 4.000 731.640 ;
    END
  END block[222]
  PIN block[223]
    DIRECTION INPUT ;
    USE SIGNAL ;
    ANTENNAGATEAREA 0.631200 ;
    ANTENNADIFFAREA 0.434700 ;
    PORT
      LAYER met3 ;
        RECT 0.000 629.040 4.000 629.640 ;
    END
  END block[223]
  PIN block[224]
    DIRECTION INPUT ;
    USE SIGNAL ;
    ANTENNAGATEAREA 0.631200 ;
    ANTENNADIFFAREA 0.434700 ;
    PORT
      LAYER met2 ;
        RECT 331.750 0.000 332.030 4.000 ;
    END
  END block[224]
  PIN block[225]
    DIRECTION INPUT ;
    USE SIGNAL ;
    ANTENNAGATEAREA 0.631200 ;
    ANTENNADIFFAREA 0.434700 ;
    PORT
      LAYER met2 ;
        RECT 244.810 0.000 245.090 4.000 ;
    END
  END block[225]
  PIN block[226]
    DIRECTION INPUT ;
    USE SIGNAL ;
    ANTENNAGATEAREA 0.631200 ;
    ANTENNADIFFAREA 0.434700 ;
    PORT
      LAYER met2 ;
        RECT 154.650 0.000 154.930 4.000 ;
    END
  END block[226]
  PIN block[227]
    DIRECTION INPUT ;
    USE SIGNAL ;
    ANTENNAGATEAREA 0.631200 ;
    ANTENNADIFFAREA 0.434700 ;
    PORT
      LAYER met3 ;
        RECT 0.000 23.840 4.000 24.440 ;
    END
  END block[227]
  PIN block[228]
    DIRECTION INPUT ;
    USE SIGNAL ;
    ANTENNAGATEAREA 0.631200 ;
    ANTENNADIFFAREA 0.434700 ;
    PORT
      LAYER met3 ;
        RECT 0.000 136.040 4.000 136.640 ;
    END
  END block[228]
  PIN block[229]
    DIRECTION INPUT ;
    USE SIGNAL ;
    ANTENNAGATEAREA 0.631200 ;
    ANTENNADIFFAREA 0.434700 ;
    PORT
      LAYER met3 ;
        RECT 0.000 68.040 4.000 68.640 ;
    END
  END block[229]
  PIN block[22]
    DIRECTION INPUT ;
    USE SIGNAL ;
    ANTENNAGATEAREA 0.647700 ;
    ANTENNADIFFAREA 0.434700 ;
    PORT
      LAYER met3 ;
        RECT 0.000 642.640 4.000 643.240 ;
    END
  END block[22]
  PIN block[230]
    DIRECTION INPUT ;
    USE SIGNAL ;
    ANTENNAGATEAREA 0.631200 ;
    ANTENNADIFFAREA 0.434700 ;
    PORT
      LAYER met3 ;
        RECT 0.000 329.840 4.000 330.440 ;
    END
  END block[230]
  PIN block[231]
    DIRECTION INPUT ;
    USE SIGNAL ;
    ANTENNAGATEAREA 0.631200 ;
    ANTENNADIFFAREA 0.434700 ;
    PORT
      LAYER met2 ;
        RECT 273.790 0.000 274.070 4.000 ;
    END
  END block[231]
  PIN block[232]
    DIRECTION INPUT ;
    USE SIGNAL ;
    ANTENNAGATEAREA 0.631200 ;
    ANTENNADIFFAREA 0.434700 ;
    PORT
      LAYER met2 ;
        RECT 470.210 0.000 470.490 4.000 ;
    END
  END block[232]
  PIN block[233]
    DIRECTION INPUT ;
    USE SIGNAL ;
    ANTENNAGATEAREA 0.631200 ;
    ANTENNADIFFAREA 0.434700 ;
    PORT
      LAYER met3 ;
        RECT 0.000 625.640 4.000 626.240 ;
    END
  END block[233]
  PIN block[234]
    DIRECTION INPUT ;
    USE SIGNAL ;
    ANTENNAGATEAREA 0.631200 ;
    ANTENNADIFFAREA 0.434700 ;
    PORT
      LAYER met3 ;
        RECT 0.000 462.440 4.000 463.040 ;
    END
  END block[234]
  PIN block[235]
    DIRECTION INPUT ;
    USE SIGNAL ;
    ANTENNAGATEAREA 0.631200 ;
    ANTENNADIFFAREA 0.434700 ;
    PORT
      LAYER met2 ;
        RECT 573.250 0.000 573.530 4.000 ;
    END
  END block[235]
  PIN block[236]
    DIRECTION INPUT ;
    USE SIGNAL ;
    ANTENNAGATEAREA 0.631200 ;
    ANTENNADIFFAREA 0.434700 ;
    PORT
      LAYER met3 ;
        RECT 0.000 275.440 4.000 276.040 ;
    END
  END block[236]
  PIN block[237]
    DIRECTION INPUT ;
    USE SIGNAL ;
    ANTENNAGATEAREA 0.631200 ;
    ANTENNADIFFAREA 0.434700 ;
    PORT
      LAYER met3 ;
        RECT 0.000 445.440 4.000 446.040 ;
    END
  END block[237]
  PIN block[238]
    DIRECTION INPUT ;
    USE SIGNAL ;
    ANTENNAGATEAREA 0.593700 ;
    ANTENNADIFFAREA 0.434700 ;
    PORT
      LAYER met3 ;
        RECT 0.000 870.440 4.000 871.040 ;
    END
  END block[238]
  PIN block[239]
    DIRECTION INPUT ;
    USE SIGNAL ;
    ANTENNAGATEAREA 0.631200 ;
    ANTENNADIFFAREA 0.434700 ;
    PORT
      LAYER met3 ;
        RECT 0.000 540.640 4.000 541.240 ;
    END
  END block[239]
  PIN block[23]
    DIRECTION INPUT ;
    USE SIGNAL ;
    ANTENNAGATEAREA 0.647700 ;
    ANTENNADIFFAREA 0.434700 ;
    PORT
      LAYER met3 ;
        RECT 0.000 877.240 4.000 877.840 ;
    END
  END block[23]
  PIN block[240]
    DIRECTION INPUT ;
    USE SIGNAL ;
    ANTENNAGATEAREA 0.631200 ;
    ANTENNADIFFAREA 0.434700 ;
    PORT
      LAYER met3 ;
        RECT 0.000 574.640 4.000 575.240 ;
    END
  END block[240]
  PIN block[241]
    DIRECTION INPUT ;
    USE SIGNAL ;
    ANTENNAGATEAREA 0.631200 ;
    ANTENNADIFFAREA 0.434700 ;
    PORT
      LAYER met3 ;
        RECT 0.000 513.440 4.000 514.040 ;
    END
  END block[241]
  PIN block[242]
    DIRECTION INPUT ;
    USE SIGNAL ;
    ANTENNAGATEAREA 0.631200 ;
    ANTENNADIFFAREA 0.434700 ;
    PORT
      LAYER met3 ;
        RECT 0.000 234.640 4.000 235.240 ;
    END
  END block[242]
  PIN block[243]
    DIRECTION INPUT ;
    USE SIGNAL ;
    ANTENNAGATEAREA 0.631200 ;
    ANTENNADIFFAREA 0.434700 ;
    PORT
      LAYER met3 ;
        RECT 0.000 241.440 4.000 242.040 ;
    END
  END block[243]
  PIN block[244]
    DIRECTION INPUT ;
    USE SIGNAL ;
    ANTENNAGATEAREA 0.631200 ;
    ANTENNADIFFAREA 0.434700 ;
    PORT
      LAYER met3 ;
        RECT 0.000 289.040 4.000 289.640 ;
    END
  END block[244]
  PIN block[245]
    DIRECTION INPUT ;
    USE SIGNAL ;
    ANTENNAGATEAREA 0.631200 ;
    ANTENNADIFFAREA 0.434700 ;
    PORT
      LAYER met3 ;
        RECT 0.000 452.240 4.000 452.840 ;
    END
  END block[245]
  PIN block[246]
    DIRECTION INPUT ;
    USE SIGNAL ;
    ANTENNAGATEAREA 0.631200 ;
    ANTENNADIFFAREA 0.434700 ;
    PORT
      LAYER met3 ;
        RECT 0.000 261.840 4.000 262.440 ;
    END
  END block[246]
  PIN block[247]
    DIRECTION INPUT ;
    USE SIGNAL ;
    ANTENNAGATEAREA 0.631200 ;
    ANTENNADIFFAREA 0.434700 ;
    PORT
      LAYER met3 ;
        RECT 0.000 595.040 4.000 595.640 ;
    END
  END block[247]
  PIN block[248]
    DIRECTION INPUT ;
    USE SIGNAL ;
    ANTENNAGATEAREA 0.631200 ;
    ANTENNADIFFAREA 0.434700 ;
    PORT
      LAYER met2 ;
        RECT 138.550 896.000 138.830 900.000 ;
    END
  END block[248]
  PIN block[249]
    DIRECTION INPUT ;
    USE SIGNAL ;
    ANTENNAGATEAREA 0.631200 ;
    ANTENNADIFFAREA 0.434700 ;
    PORT
      LAYER met3 ;
        RECT 0.000 785.440 4.000 786.040 ;
    END
  END block[249]
  PIN block[24]
    DIRECTION INPUT ;
    USE SIGNAL ;
    ANTENNAGATEAREA 0.631200 ;
    ANTENNADIFFAREA 0.434700 ;
    PORT
      LAYER met3 ;
        RECT 0.000 612.040 4.000 612.640 ;
    END
  END block[24]
  PIN block[250]
    DIRECTION INPUT ;
    USE SIGNAL ;
    ANTENNAGATEAREA 0.631200 ;
    ANTENNADIFFAREA 0.434700 ;
    PORT
      LAYER met3 ;
        RECT 0.000 782.040 4.000 782.640 ;
    END
  END block[250]
  PIN block[251]
    DIRECTION INPUT ;
    USE SIGNAL ;
    ANTENNAGATEAREA 0.631200 ;
    ANTENNADIFFAREA 0.434700 ;
    PORT
      LAYER met2 ;
        RECT 74.150 896.000 74.430 900.000 ;
    END
  END block[251]
  PIN block[252]
    DIRECTION INPUT ;
    USE SIGNAL ;
    ANTENNAGATEAREA 0.631200 ;
    ANTENNADIFFAREA 0.434700 ;
    PORT
      LAYER met2 ;
        RECT 116.010 896.000 116.290 900.000 ;
    END
  END block[252]
  PIN block[253]
    DIRECTION INPUT ;
    USE SIGNAL ;
    ANTENNAGATEAREA 0.631200 ;
    ANTENNADIFFAREA 0.434700 ;
    PORT
      LAYER met2 ;
        RECT 164.310 896.000 164.590 900.000 ;
    END
  END block[253]
  PIN block[254]
    DIRECTION INPUT ;
    USE SIGNAL ;
    ANTENNAGATEAREA 0.631200 ;
    ANTENNADIFFAREA 0.434700 ;
    PORT
      LAYER met3 ;
        RECT 0.000 693.640 4.000 694.240 ;
    END
  END block[254]
  PIN block[255]
    DIRECTION INPUT ;
    USE SIGNAL ;
    ANTENNAGATEAREA 0.631200 ;
    ANTENNADIFFAREA 0.434700 ;
    PORT
      LAYER met3 ;
        RECT 0.000 601.840 4.000 602.440 ;
    END
  END block[255]
  PIN block[256]
    DIRECTION INPUT ;
    USE SIGNAL ;
    ANTENNAGATEAREA 0.631200 ;
    ANTENNADIFFAREA 0.434700 ;
    PORT
      LAYER met2 ;
        RECT 627.990 0.000 628.270 4.000 ;
    END
  END block[256]
  PIN block[257]
    DIRECTION INPUT ;
    USE SIGNAL ;
    ANTENNAGATEAREA 0.631200 ;
    ANTENNADIFFAREA 0.434700 ;
    PORT
      LAYER met2 ;
        RECT 238.370 0.000 238.650 4.000 ;
    END
  END block[257]
  PIN block[258]
    DIRECTION INPUT ;
    USE SIGNAL ;
    ANTENNAGATEAREA 0.631200 ;
    ANTENNADIFFAREA 0.434700 ;
    PORT
      LAYER met3 ;
        RECT 0.000 115.640 4.000 116.240 ;
    END
  END block[258]
  PIN block[259]
    DIRECTION INPUT ;
    USE SIGNAL ;
    ANTENNAGATEAREA 0.631200 ;
    ANTENNADIFFAREA 0.434700 ;
    PORT
      LAYER met3 ;
        RECT 0.000 57.840 4.000 58.440 ;
    END
  END block[259]
  PIN block[25]
    DIRECTION INPUT ;
    USE SIGNAL ;
    ANTENNAGATEAREA 0.631200 ;
    ANTENNADIFFAREA 0.434700 ;
    PORT
      LAYER met3 ;
        RECT 0.000 652.840 4.000 653.440 ;
    END
  END block[25]
  PIN block[260]
    DIRECTION INPUT ;
    USE SIGNAL ;
    ANTENNAGATEAREA 0.631200 ;
    ANTENNADIFFAREA 0.434700 ;
    PORT
      LAYER met3 ;
        RECT 0.000 156.440 4.000 157.040 ;
    END
  END block[260]
  PIN block[261]
    DIRECTION INPUT ;
    USE SIGNAL ;
    ANTENNAGATEAREA 0.631200 ;
    ANTENNADIFFAREA 0.434700 ;
    PORT
      LAYER met3 ;
        RECT 0.000 27.240 4.000 27.840 ;
    END
  END block[261]
  PIN block[262]
    DIRECTION INPUT ;
    USE SIGNAL ;
    ANTENNAGATEAREA 0.631200 ;
    ANTENNADIFFAREA 0.434700 ;
    PORT
      LAYER met3 ;
        RECT 0.000 299.240 4.000 299.840 ;
    END
  END block[262]
  PIN block[263]
    DIRECTION INPUT ;
    USE SIGNAL ;
    ANTENNAGATEAREA 0.631200 ;
    ANTENNADIFFAREA 0.434700 ;
    PORT
      LAYER met2 ;
        RECT 277.010 0.000 277.290 4.000 ;
    END
  END block[263]
  PIN block[264]
    DIRECTION INPUT ;
    USE SIGNAL ;
    ANTENNAGATEAREA 0.631200 ;
    ANTENNADIFFAREA 0.434700 ;
    PORT
      LAYER met2 ;
        RECT 621.550 0.000 621.830 4.000 ;
    END
  END block[264]
  PIN block[265]
    DIRECTION INPUT ;
    USE SIGNAL ;
    ANTENNAGATEAREA 0.631200 ;
    ANTENNADIFFAREA 0.434700 ;
    PORT
      LAYER met3 ;
        RECT 0.000 850.040 4.000 850.640 ;
    END
  END block[265]
  PIN block[266]
    DIRECTION INPUT ;
    USE SIGNAL ;
    ANTENNAGATEAREA 0.631200 ;
    ANTENNADIFFAREA 0.434700 ;
    PORT
      LAYER met3 ;
        RECT 0.000 459.040 4.000 459.640 ;
    END
  END block[266]
  PIN block[267]
    DIRECTION INPUT ;
    USE SIGNAL ;
    ANTENNAGATEAREA 0.631200 ;
    ANTENNADIFFAREA 0.434700 ;
    PORT
      LAYER met2 ;
        RECT 505.630 0.000 505.910 4.000 ;
    END
  END block[267]
  PIN block[268]
    DIRECTION INPUT ;
    USE SIGNAL ;
    ANTENNAGATEAREA 0.631200 ;
    ANTENNADIFFAREA 0.434700 ;
    PORT
      LAYER met3 ;
        RECT 0.000 282.240 4.000 282.840 ;
    END
  END block[268]
  PIN block[269]
    DIRECTION INPUT ;
    USE SIGNAL ;
    ANTENNAGATEAREA 0.631200 ;
    ANTENNADIFFAREA 0.434700 ;
    PORT
      LAYER met3 ;
        RECT 0.000 431.840 4.000 432.440 ;
    END
  END block[269]
  PIN block[26]
    DIRECTION INPUT ;
    USE SIGNAL ;
    ANTENNAGATEAREA 0.631200 ;
    ANTENNADIFFAREA 0.434700 ;
    PORT
      LAYER met3 ;
        RECT 0.000 775.240 4.000 775.840 ;
    END
  END block[26]
  PIN block[270]
    DIRECTION INPUT ;
    USE SIGNAL ;
    ANTENNAGATEAREA 0.631200 ;
    ANTENNADIFFAREA 0.434700 ;
    PORT
      LAYER met3 ;
        RECT 0.000 503.240 4.000 503.840 ;
    END
  END block[270]
  PIN block[271]
    DIRECTION INPUT ;
    USE SIGNAL ;
    ANTENNAGATEAREA 0.631200 ;
    ANTENNADIFFAREA 0.434700 ;
    PORT
      LAYER met3 ;
        RECT 0.000 547.440 4.000 548.040 ;
    END
  END block[271]
  PIN block[272]
    DIRECTION INPUT ;
    USE SIGNAL ;
    ANTENNAGATEAREA 0.631200 ;
    ANTENNADIFFAREA 0.434700 ;
    PORT
      LAYER met3 ;
        RECT 0.000 571.240 4.000 571.840 ;
    END
  END block[272]
  PIN block[273]
    DIRECTION INPUT ;
    USE SIGNAL ;
    ANTENNAGATEAREA 0.631200 ;
    ANTENNADIFFAREA 0.434700 ;
    PORT
      LAYER met3 ;
        RECT 0.000 520.240 4.000 520.840 ;
    END
  END block[273]
  PIN block[274]
    DIRECTION INPUT ;
    USE SIGNAL ;
    ANTENNAGATEAREA 0.631200 ;
    ANTENNADIFFAREA 0.434700 ;
    PORT
      LAYER met3 ;
        RECT 0.000 316.240 4.000 316.840 ;
    END
  END block[274]
  PIN block[275]
    DIRECTION INPUT ;
    USE SIGNAL ;
    ANTENNAGATEAREA 0.631200 ;
    ANTENNADIFFAREA 0.434700 ;
    PORT
      LAYER met3 ;
        RECT 0.000 295.840 4.000 296.440 ;
    END
  END block[275]
  PIN block[276]
    DIRECTION INPUT ;
    USE SIGNAL ;
    ANTENNAGATEAREA 0.631200 ;
    ANTENNADIFFAREA 0.434700 ;
    PORT
      LAYER met3 ;
        RECT 0.000 278.840 4.000 279.440 ;
    END
  END block[276]
  PIN block[277]
    DIRECTION INPUT ;
    USE SIGNAL ;
    ANTENNAGATEAREA 0.631200 ;
    ANTENNADIFFAREA 0.434700 ;
    PORT
      LAYER met3 ;
        RECT 0.000 357.040 4.000 357.640 ;
    END
  END block[277]
  PIN block[278]
    DIRECTION INPUT ;
    USE SIGNAL ;
    ANTENNAGATEAREA 0.631200 ;
    ANTENNADIFFAREA 0.434700 ;
    PORT
      LAYER met3 ;
        RECT 0.000 384.240 4.000 384.840 ;
    END
  END block[278]
  PIN block[279]
    DIRECTION INPUT ;
    USE SIGNAL ;
    ANTENNAGATEAREA 0.631200 ;
    ANTENNADIFFAREA 0.434700 ;
    PORT
      LAYER met3 ;
        RECT 0.000 819.440 4.000 820.040 ;
    END
  END block[279]
  PIN block[27]
    DIRECTION INPUT ;
    USE SIGNAL ;
    ANTENNAGATEAREA 0.631200 ;
    ANTENNADIFFAREA 0.434700 ;
    PORT
      LAYER met3 ;
        RECT 0.000 734.440 4.000 735.040 ;
    END
  END block[27]
  PIN block[280]
    DIRECTION INPUT ;
    USE SIGNAL ;
    ANTENNAGATEAREA 0.631200 ;
    ANTENNADIFFAREA 0.434700 ;
    PORT
      LAYER met2 ;
        RECT 6.530 896.000 6.810 900.000 ;
    END
  END block[280]
  PIN block[281]
    DIRECTION INPUT ;
    USE SIGNAL ;
    ANTENNAGATEAREA 0.631200 ;
    ANTENNADIFFAREA 0.434700 ;
    PORT
      LAYER met3 ;
        RECT 0.000 666.440 4.000 667.040 ;
    END
  END block[281]
  PIN block[282]
    DIRECTION INPUT ;
    USE SIGNAL ;
    ANTENNAGATEAREA 0.631200 ;
    ANTENNADIFFAREA 0.434700 ;
    PORT
      LAYER met3 ;
        RECT 0.000 880.640 4.000 881.240 ;
    END
  END block[282]
  PIN block[283]
    DIRECTION INPUT ;
    USE SIGNAL ;
    ANTENNAGATEAREA 0.631200 ;
    ANTENNADIFFAREA 0.434700 ;
    PORT
      LAYER met2 ;
        RECT 180.410 896.000 180.690 900.000 ;
    END
  END block[283]
  PIN block[284]
    DIRECTION INPUT ;
    USE SIGNAL ;
    ANTENNAGATEAREA 0.631200 ;
    ANTENNADIFFAREA 0.434700 ;
    PORT
      LAYER met2 ;
        RECT 235.150 896.000 235.430 900.000 ;
    END
  END block[284]
  PIN block[285]
    DIRECTION INPUT ;
    USE SIGNAL ;
    ANTENNAGATEAREA 0.631200 ;
    ANTENNADIFFAREA 0.434700 ;
    PORT
      LAYER met2 ;
        RECT 215.830 896.000 216.110 900.000 ;
    END
  END block[285]
  PIN block[286]
    DIRECTION INPUT ;
    USE SIGNAL ;
    ANTENNAGATEAREA 0.631200 ;
    ANTENNADIFFAREA 0.434700 ;
    PORT
      LAYER met3 ;
        RECT 0.000 720.840 4.000 721.440 ;
    END
  END block[286]
  PIN block[287]
    DIRECTION INPUT ;
    USE SIGNAL ;
    ANTENNAGATEAREA 0.631200 ;
    ANTENNADIFFAREA 0.434700 ;
    PORT
      LAYER met3 ;
        RECT 0.000 707.240 4.000 707.840 ;
    END
  END block[287]
  PIN block[288]
    DIRECTION INPUT ;
    USE SIGNAL ;
    ANTENNAGATEAREA 0.631200 ;
    ANTENNADIFFAREA 0.434700 ;
    PORT
      LAYER met2 ;
        RECT 637.650 0.000 637.930 4.000 ;
    END
  END block[288]
  PIN block[289]
    DIRECTION INPUT ;
    USE SIGNAL ;
    ANTENNAGATEAREA 0.631200 ;
    ANTENNADIFFAREA 0.434700 ;
    PORT
      LAYER met2 ;
        RECT 119.230 0.000 119.510 4.000 ;
    END
  END block[289]
  PIN block[28]
    DIRECTION INPUT ;
    USE SIGNAL ;
    ANTENNAGATEAREA 0.560700 ;
    ANTENNADIFFAREA 0.434700 ;
    PORT
      LAYER met3 ;
        RECT 0.000 829.640 4.000 830.240 ;
    END
  END block[28]
  PIN block[290]
    DIRECTION INPUT ;
    USE SIGNAL ;
    ANTENNAGATEAREA 0.631200 ;
    ANTENNADIFFAREA 0.434700 ;
    PORT
      LAYER met3 ;
        RECT 0.000 98.640 4.000 99.240 ;
    END
  END block[290]
  PIN block[291]
    DIRECTION INPUT ;
    USE SIGNAL ;
    ANTENNAGATEAREA 0.631200 ;
    ANTENNADIFFAREA 0.434700 ;
    PORT
      LAYER met3 ;
        RECT 0.000 105.440 4.000 106.040 ;
    END
  END block[291]
  PIN block[292]
    DIRECTION INPUT ;
    USE SIGNAL ;
    ANTENNAGATEAREA 0.631200 ;
    ANTENNADIFFAREA 0.434700 ;
    PORT
      LAYER met3 ;
        RECT 0.000 74.840 4.000 75.440 ;
    END
  END block[292]
  PIN block[293]
    DIRECTION INPUT ;
    USE SIGNAL ;
    ANTENNAGATEAREA 0.631200 ;
    ANTENNADIFFAREA 0.434700 ;
    PORT
      LAYER met3 ;
        RECT 0.000 91.840 4.000 92.440 ;
    END
  END block[293]
  PIN block[294]
    DIRECTION INPUT ;
    USE SIGNAL ;
    ANTENNAGATEAREA 0.631200 ;
    ANTENNADIFFAREA 0.434700 ;
    PORT
      LAYER met3 ;
        RECT 0.000 306.040 4.000 306.640 ;
    END
  END block[294]
  PIN block[295]
    DIRECTION INPUT ;
    USE SIGNAL ;
    ANTENNAGATEAREA 0.631200 ;
    ANTENNADIFFAREA 0.434700 ;
    PORT
      LAYER met2 ;
        RECT 283.450 0.000 283.730 4.000 ;
    END
  END block[295]
  PIN block[296]
    DIRECTION INPUT ;
    USE SIGNAL ;
    ANTENNAGATEAREA 0.631200 ;
    ANTENNADIFFAREA 0.434700 ;
    PORT
      LAYER met2 ;
        RECT 489.530 0.000 489.810 4.000 ;
    END
  END block[296]
  PIN block[297]
    DIRECTION INPUT ;
    USE SIGNAL ;
    ANTENNAGATEAREA 0.631200 ;
    ANTENNADIFFAREA 0.434700 ;
    PORT
      LAYER met3 ;
        RECT 0.000 863.640 4.000 864.240 ;
    END
  END block[297]
  PIN block[298]
    DIRECTION INPUT ;
    USE SIGNAL ;
    ANTENNAGATEAREA 0.631200 ;
    ANTENNADIFFAREA 0.434700 ;
    PORT
      LAYER met3 ;
        RECT 0.000 455.640 4.000 456.240 ;
    END
  END block[298]
  PIN block[299]
    DIRECTION INPUT ;
    USE SIGNAL ;
    ANTENNAGATEAREA 0.631200 ;
    ANTENNADIFFAREA 0.434700 ;
    PORT
      LAYER met2 ;
        RECT 508.850 0.000 509.130 4.000 ;
    END
  END block[299]
  PIN block[29]
    DIRECTION INPUT ;
    USE SIGNAL ;
    ANTENNAGATEAREA 0.631200 ;
    ANTENNADIFFAREA 0.434700 ;
    PORT
      LAYER met3 ;
        RECT 0.000 805.840 4.000 806.440 ;
    END
  END block[29]
  PIN block[2]
    DIRECTION INPUT ;
    USE SIGNAL ;
    ANTENNAGATEAREA 0.631200 ;
    ANTENNADIFFAREA 0.434700 ;
    PORT
      LAYER met2 ;
        RECT 202.950 0.000 203.230 4.000 ;
    END
  END block[2]
  PIN block[300]
    DIRECTION INPUT ;
    USE SIGNAL ;
    ANTENNAGATEAREA 0.631200 ;
    ANTENNADIFFAREA 0.434700 ;
    PORT
      LAYER met3 ;
        RECT 0.000 350.240 4.000 350.840 ;
    END
  END block[300]
  PIN block[301]
    DIRECTION INPUT ;
    USE SIGNAL ;
    ANTENNAGATEAREA 0.631200 ;
    ANTENNADIFFAREA 0.434700 ;
    PORT
      LAYER met3 ;
        RECT 0.000 465.840 4.000 466.440 ;
    END
  END block[301]
  PIN block[302]
    DIRECTION INPUT ;
    USE SIGNAL ;
    ANTENNAGATEAREA 0.631200 ;
    ANTENNADIFFAREA 0.434700 ;
    PORT
      LAYER met3 ;
        RECT 0.000 544.040 4.000 544.640 ;
    END
  END block[302]
  PIN block[303]
    DIRECTION INPUT ;
    USE SIGNAL ;
    ANTENNAGATEAREA 0.631200 ;
    ANTENNADIFFAREA 0.434700 ;
    PORT
      LAYER met3 ;
        RECT 0.000 605.240 4.000 605.840 ;
    END
  END block[303]
  PIN block[304]
    DIRECTION INPUT ;
    USE SIGNAL ;
    ANTENNAGATEAREA 0.631200 ;
    ANTENNADIFFAREA 0.434700 ;
    PORT
      LAYER met3 ;
        RECT 0.000 567.840 4.000 568.440 ;
    END
  END block[304]
  PIN block[305]
    DIRECTION INPUT ;
    USE SIGNAL ;
    ANTENNAGATEAREA 0.631200 ;
    ANTENNADIFFAREA 0.434700 ;
    PORT
      LAYER met3 ;
        RECT 0.000 527.040 4.000 527.640 ;
    END
  END block[305]
  PIN block[306]
    DIRECTION INPUT ;
    USE SIGNAL ;
    ANTENNAGATEAREA 0.631200 ;
    ANTENNADIFFAREA 0.434700 ;
    PORT
      LAYER met3 ;
        RECT 0.000 272.040 4.000 272.640 ;
    END
  END block[306]
  PIN block[307]
    DIRECTION INPUT ;
    USE SIGNAL ;
    ANTENNAGATEAREA 0.631200 ;
    ANTENNADIFFAREA 0.434700 ;
    PORT
      LAYER met3 ;
        RECT 0.000 224.440 4.000 225.040 ;
    END
  END block[307]
  PIN block[308]
    DIRECTION INPUT ;
    USE SIGNAL ;
    ANTENNAGATEAREA 0.631200 ;
    ANTENNADIFFAREA 0.434700 ;
    PORT
      LAYER met3 ;
        RECT 0.000 285.640 4.000 286.240 ;
    END
  END block[308]
  PIN block[309]
    DIRECTION INPUT ;
    USE SIGNAL ;
    ANTENNAGATEAREA 0.631200 ;
    ANTENNADIFFAREA 0.434700 ;
    PORT
      LAYER met3 ;
        RECT 0.000 418.240 4.000 418.840 ;
    END
  END block[309]
  PIN block[30]
    DIRECTION INPUT ;
    USE SIGNAL ;
    ANTENNAGATEAREA 0.631200 ;
    ANTENNADIFFAREA 0.434700 ;
    PORT
      LAYER met3 ;
        RECT 0.000 741.240 4.000 741.840 ;
    END
  END block[30]
  PIN block[310]
    DIRECTION INPUT ;
    USE SIGNAL ;
    ANTENNAGATEAREA 0.631200 ;
    ANTENNADIFFAREA 0.434700 ;
    PORT
      LAYER met3 ;
        RECT 0.000 255.040 4.000 255.640 ;
    END
  END block[310]
  PIN block[311]
    DIRECTION INPUT ;
    USE SIGNAL ;
    ANTENNAGATEAREA 0.631200 ;
    ANTENNADIFFAREA 0.434700 ;
    PORT
      LAYER met3 ;
        RECT 0.000 744.640 4.000 745.240 ;
    END
  END block[311]
  PIN block[312]
    DIRECTION INPUT ;
    USE SIGNAL ;
    ANTENNAGATEAREA 0.631200 ;
    ANTENNADIFFAREA 0.434700 ;
    PORT
      LAYER met2 ;
        RECT 35.510 896.000 35.790 900.000 ;
    END
  END block[312]
  PIN block[313]
    DIRECTION INPUT ;
    USE SIGNAL ;
    ANTENNAGATEAREA 0.631200 ;
    ANTENNADIFFAREA 0.434700 ;
    PORT
      LAYER met3 ;
        RECT 0.000 816.040 4.000 816.640 ;
    END
  END block[313]
  PIN block[314]
    DIRECTION INPUT ;
    USE SIGNAL ;
    ANTENNAGATEAREA 0.631200 ;
    ANTENNADIFFAREA 0.434700 ;
    PORT
      LAYER met3 ;
        RECT 0.000 758.240 4.000 758.840 ;
    END
  END block[314]
  PIN block[315]
    DIRECTION INPUT ;
    USE SIGNAL ;
    ANTENNAGATEAREA 0.631200 ;
    ANTENNADIFFAREA 0.434700 ;
    PORT
      LAYER met2 ;
        RECT 109.570 896.000 109.850 900.000 ;
    END
  END block[315]
  PIN block[316]
    DIRECTION INPUT ;
    USE SIGNAL ;
    ANTENNAGATEAREA 0.631200 ;
    ANTENNADIFFAREA 0.434700 ;
    PORT
      LAYER met2 ;
        RECT 228.710 896.000 228.990 900.000 ;
    END
  END block[316]
  PIN block[317]
    DIRECTION INPUT ;
    USE SIGNAL ;
    ANTENNAGATEAREA 0.631200 ;
    ANTENNADIFFAREA 0.434700 ;
    PORT
      LAYER met2 ;
        RECT 12.970 896.000 13.250 900.000 ;
    END
  END block[317]
  PIN block[318]
    DIRECTION INPUT ;
    USE SIGNAL ;
    ANTENNAGATEAREA 0.631200 ;
    ANTENNADIFFAREA 0.434700 ;
    PORT
      LAYER met3 ;
        RECT 0.000 724.240 4.000 724.840 ;
    END
  END block[318]
  PIN block[319]
    DIRECTION INPUT ;
    USE SIGNAL ;
    ANTENNAGATEAREA 0.631200 ;
    ANTENNADIFFAREA 0.434700 ;
    PORT
      LAYER met3 ;
        RECT 0.000 673.240 4.000 673.840 ;
    END
  END block[319]
  PIN block[31]
    DIRECTION INPUT ;
    USE SIGNAL ;
    ANTENNAGATEAREA 0.631200 ;
    ANTENNADIFFAREA 0.434700 ;
    PORT
      LAYER met3 ;
        RECT 0.000 727.640 4.000 728.240 ;
    END
  END block[31]
  PIN block[320]
    DIRECTION INPUT ;
    USE SIGNAL ;
    ANTENNAGATEAREA 0.631200 ;
    ANTENNADIFFAREA 0.434700 ;
    PORT
      LAYER met2 ;
        RECT 599.010 0.000 599.290 4.000 ;
    END
  END block[320]
  PIN block[321]
    DIRECTION INPUT ;
    USE SIGNAL ;
    ANTENNAGATEAREA 0.631200 ;
    ANTENNADIFFAREA 0.434700 ;
    PORT
      LAYER met2 ;
        RECT 235.150 0.000 235.430 4.000 ;
    END
  END block[321]
  PIN block[322]
    DIRECTION INPUT ;
    USE SIGNAL ;
    ANTENNAGATEAREA 0.631200 ;
    ANTENNADIFFAREA 0.434700 ;
    PORT
      LAYER met3 ;
        RECT 0.000 10.240 4.000 10.840 ;
    END
  END block[322]
  PIN block[323]
    DIRECTION INPUT ;
    USE SIGNAL ;
    ANTENNAGATEAREA 0.631200 ;
    ANTENNADIFFAREA 0.434700 ;
    PORT
      LAYER met3 ;
        RECT 0.000 173.440 4.000 174.040 ;
    END
  END block[323]
  PIN block[324]
    DIRECTION INPUT ;
    USE SIGNAL ;
    ANTENNAGATEAREA 0.631200 ;
    ANTENNADIFFAREA 0.434700 ;
    PORT
      LAYER met3 ;
        RECT 0.000 30.640 4.000 31.240 ;
    END
  END block[324]
  PIN block[325]
    DIRECTION INPUT ;
    USE SIGNAL ;
    ANTENNAGATEAREA 0.631200 ;
    ANTENNADIFFAREA 0.434700 ;
    PORT
      LAYER met3 ;
        RECT 0.000 112.240 4.000 112.840 ;
    END
  END block[325]
  PIN block[326]
    DIRECTION INPUT ;
    USE SIGNAL ;
    ANTENNAGATEAREA 0.631200 ;
    ANTENNADIFFAREA 0.434700 ;
    PORT
      LAYER met3 ;
        RECT 0.000 333.240 4.000 333.840 ;
    END
  END block[326]
  PIN block[327]
    DIRECTION INPUT ;
    USE SIGNAL ;
    ANTENNAGATEAREA 0.631200 ;
    ANTENNADIFFAREA 0.434700 ;
    PORT
      LAYER met2 ;
        RECT 264.130 0.000 264.410 4.000 ;
    END
  END block[327]
  PIN block[328]
    DIRECTION INPUT ;
    USE SIGNAL ;
    ANTENNAGATEAREA 0.631200 ;
    ANTENNADIFFAREA 0.434700 ;
    PORT
      LAYER met2 ;
        RECT 357.510 0.000 357.790 4.000 ;
    END
  END block[328]
  PIN block[329]
    DIRECTION INPUT ;
    USE SIGNAL ;
    ANTENNAGATEAREA 0.631200 ;
    ANTENNADIFFAREA 0.434700 ;
    PORT
      LAYER met3 ;
        RECT 0.000 635.840 4.000 636.440 ;
    END
  END block[329]
  PIN block[32]
    DIRECTION INPUT ;
    USE SIGNAL ;
    ANTENNAGATEAREA 0.631200 ;
    ANTENNADIFFAREA 0.434700 ;
    PORT
      LAYER met2 ;
        RECT 289.890 0.000 290.170 4.000 ;
    END
  END block[32]
  PIN block[330]
    DIRECTION INPUT ;
    USE SIGNAL ;
    ANTENNAGATEAREA 0.631200 ;
    ANTENNADIFFAREA 0.434700 ;
    PORT
      LAYER met3 ;
        RECT 0.000 448.840 4.000 449.440 ;
    END
  END block[330]
  PIN block[331]
    DIRECTION INPUT ;
    USE SIGNAL ;
    ANTENNAGATEAREA 0.631200 ;
    ANTENNADIFFAREA 0.434700 ;
    PORT
      LAYER met2 ;
        RECT 428.350 0.000 428.630 4.000 ;
    END
  END block[331]
  PIN block[332]
    DIRECTION INPUT ;
    USE SIGNAL ;
    ANTENNAGATEAREA 0.631200 ;
    ANTENNADIFFAREA 0.434700 ;
    PORT
      LAYER met3 ;
        RECT 0.000 370.640 4.000 371.240 ;
    END
  END block[332]
  PIN block[333]
    DIRECTION INPUT ;
    USE SIGNAL ;
    ANTENNAGATEAREA 0.631200 ;
    ANTENNADIFFAREA 0.434700 ;
    PORT
      LAYER met3 ;
        RECT 0.000 476.040 4.000 476.640 ;
    END
  END block[333]
  PIN block[334]
    DIRECTION INPUT ;
    USE SIGNAL ;
    ANTENNAGATEAREA 0.631200 ;
    ANTENNADIFFAREA 0.434700 ;
    PORT
      LAYER met3 ;
        RECT 0.000 506.640 4.000 507.240 ;
    END
  END block[334]
  PIN block[335]
    DIRECTION INPUT ;
    USE SIGNAL ;
    ANTENNAGATEAREA 0.631200 ;
    ANTENNADIFFAREA 0.434700 ;
    PORT
      LAYER met3 ;
        RECT 0.000 771.840 4.000 772.440 ;
    END
  END block[335]
  PIN block[336]
    DIRECTION INPUT ;
    USE SIGNAL ;
    ANTENNAGATEAREA 0.631200 ;
    ANTENNADIFFAREA 0.434700 ;
    PORT
      LAYER met3 ;
        RECT 0.000 561.040 4.000 561.640 ;
    END
  END block[336]
  PIN block[337]
    DIRECTION INPUT ;
    USE SIGNAL ;
    ANTENNAGATEAREA 0.631200 ;
    ANTENNADIFFAREA 0.434700 ;
    PORT
      LAYER met3 ;
        RECT 0.000 533.840 4.000 534.440 ;
    END
  END block[337]
  PIN block[338]
    DIRECTION INPUT ;
    USE SIGNAL ;
    ANTENNAGATEAREA 0.631200 ;
    ANTENNADIFFAREA 0.434700 ;
    PORT
      LAYER met3 ;
        RECT 0.000 139.440 4.000 140.040 ;
    END
  END block[338]
  PIN block[339]
    DIRECTION INPUT ;
    USE SIGNAL ;
    ANTENNAGATEAREA 0.631200 ;
    ANTENNADIFFAREA 0.434700 ;
    PORT
      LAYER met3 ;
        RECT 0.000 132.640 4.000 133.240 ;
    END
  END block[339]
  PIN block[33]
    DIRECTION INPUT ;
    USE SIGNAL ;
    ANTENNAGATEAREA 0.631200 ;
    ANTENNADIFFAREA 0.434700 ;
    PORT
      LAYER met2 ;
        RECT 164.310 0.000 164.590 4.000 ;
    END
  END block[33]
  PIN block[340]
    DIRECTION INPUT ;
    USE SIGNAL ;
    ANTENNAGATEAREA 0.631200 ;
    ANTENNADIFFAREA 0.434700 ;
    PORT
      LAYER met3 ;
        RECT 0.000 343.440 4.000 344.040 ;
    END
  END block[340]
  PIN block[341]
    DIRECTION INPUT ;
    USE SIGNAL ;
    ANTENNAGATEAREA 0.631200 ;
    ANTENNADIFFAREA 0.434700 ;
    PORT
      LAYER met3 ;
        RECT 0.000 326.440 4.000 327.040 ;
    END
  END block[341]
  PIN block[342]
    DIRECTION INPUT ;
    USE SIGNAL ;
    ANTENNAGATEAREA 0.631200 ;
    ANTENNADIFFAREA 0.434700 ;
    PORT
      LAYER met3 ;
        RECT 0.000 360.440 4.000 361.040 ;
    END
  END block[342]
  PIN block[343]
    DIRECTION INPUT ;
    USE SIGNAL ;
    ANTENNAGATEAREA 0.631200 ;
    ANTENNADIFFAREA 0.434700 ;
    PORT
      LAYER met3 ;
        RECT 0.000 754.840 4.000 755.440 ;
    END
  END block[343]
  PIN block[344]
    DIRECTION INPUT ;
    USE SIGNAL ;
    ANTENNAGATEAREA 0.631200 ;
    ANTENNADIFFAREA 0.434700 ;
    PORT
      LAYER met2 ;
        RECT 32.290 896.000 32.570 900.000 ;
    END
  END block[344]
  PIN block[345]
    DIRECTION INPUT ;
    USE SIGNAL ;
    ANTENNAGATEAREA 0.631200 ;
    ANTENNADIFFAREA 0.434700 ;
    PORT
      LAYER met3 ;
        RECT 0.000 792.240 4.000 792.840 ;
    END
  END block[345]
  PIN block[346]
    DIRECTION INPUT ;
    USE SIGNAL ;
    ANTENNAGATEAREA 0.631200 ;
    ANTENNADIFFAREA 0.434700 ;
    PORT
      LAYER met3 ;
        RECT 0.000 890.840 4.000 891.440 ;
    END
  END block[346]
  PIN block[347]
    DIRECTION INPUT ;
    USE SIGNAL ;
    ANTENNAGATEAREA 0.631200 ;
    ANTENNADIFFAREA 0.434700 ;
    PORT
      LAYER met2 ;
        RECT 93.470 896.000 93.750 900.000 ;
    END
  END block[347]
  PIN block[348]
    DIRECTION INPUT ;
    USE SIGNAL ;
    ANTENNAGATEAREA 0.631200 ;
    ANTENNADIFFAREA 0.434700 ;
    PORT
      LAYER met3 ;
        RECT 0.000 737.840 4.000 738.440 ;
    END
  END block[348]
  PIN block[349]
    DIRECTION INPUT ;
    USE SIGNAL ;
    ANTENNAGATEAREA 0.631200 ;
    ANTENNADIFFAREA 0.434700 ;
    PORT
      LAYER met2 ;
        RECT 96.690 896.000 96.970 900.000 ;
    END
  END block[349]
  PIN block[34]
    DIRECTION INPUT ;
    USE SIGNAL ;
    ANTENNAGATEAREA 0.631200 ;
    ANTENNADIFFAREA 0.434700 ;
    PORT
      LAYER met3 ;
        RECT 0.000 47.640 4.000 48.240 ;
    END
  END block[34]
  PIN block[350]
    DIRECTION INPUT ;
    USE SIGNAL ;
    ANTENNAGATEAREA 0.631200 ;
    ANTENNADIFFAREA 0.434700 ;
    PORT
      LAYER met3 ;
        RECT 0.000 809.240 4.000 809.840 ;
    END
  END block[350]
  PIN block[351]
    DIRECTION INPUT ;
    USE SIGNAL ;
    ANTENNAGATEAREA 0.631200 ;
    ANTENNADIFFAREA 0.434700 ;
    PORT
      LAYER met3 ;
        RECT 0.000 802.440 4.000 803.040 ;
    END
  END block[351]
  PIN block[352]
    DIRECTION INPUT ;
    USE SIGNAL ;
    ANTENNAGATEAREA 0.631200 ;
    ANTENNADIFFAREA 0.434700 ;
    PORT
      LAYER met2 ;
        RECT 495.970 0.000 496.250 4.000 ;
    END
  END block[352]
  PIN block[353]
    DIRECTION INPUT ;
    USE SIGNAL ;
    ANTENNAGATEAREA 0.631200 ;
    ANTENNADIFFAREA 0.434700 ;
    PORT
      LAYER met2 ;
        RECT 241.590 0.000 241.870 4.000 ;
    END
  END block[353]
  PIN block[354]
    DIRECTION INPUT ;
    USE SIGNAL ;
    ANTENNAGATEAREA 0.631200 ;
    ANTENNADIFFAREA 0.434700 ;
    PORT
      LAYER met2 ;
        RECT 77.370 0.000 77.650 4.000 ;
    END
  END block[354]
  PIN block[355]
    DIRECTION INPUT ;
    USE SIGNAL ;
    ANTENNAGATEAREA 0.631200 ;
    ANTENNADIFFAREA 0.434700 ;
    PORT
      LAYER met3 ;
        RECT 0.000 3.440 4.000 4.040 ;
    END
  END block[355]
  PIN block[356]
    DIRECTION INPUT ;
    USE SIGNAL ;
    ANTENNAGATEAREA 0.631200 ;
    ANTENNADIFFAREA 0.434700 ;
    PORT
      LAYER met3 ;
        RECT 0.000 95.240 4.000 95.840 ;
    END
  END block[356]
  PIN block[357]
    DIRECTION INPUT ;
    USE SIGNAL ;
    ANTENNAGATEAREA 0.631200 ;
    ANTENNADIFFAREA 0.434700 ;
    PORT
      LAYER met3 ;
        RECT 0.000 122.440 4.000 123.040 ;
    END
  END block[357]
  PIN block[358]
    DIRECTION INPUT ;
    USE SIGNAL ;
    ANTENNAGATEAREA 0.631200 ;
    ANTENNADIFFAREA 0.434700 ;
    PORT
      LAYER met3 ;
        RECT 0.000 17.040 4.000 17.640 ;
    END
  END block[358]
  PIN block[359]
    DIRECTION INPUT ;
    USE SIGNAL ;
    ANTENNAGATEAREA 0.631200 ;
    ANTENNADIFFAREA 0.434700 ;
    PORT
      LAYER met2 ;
        RECT 286.670 0.000 286.950 4.000 ;
    END
  END block[359]
  PIN block[35]
    DIRECTION INPUT ;
    USE SIGNAL ;
    ANTENNAGATEAREA 0.631200 ;
    ANTENNADIFFAREA 0.434700 ;
    PORT
      LAYER met2 ;
        RECT 128.890 0.000 129.170 4.000 ;
    END
  END block[35]
  PIN block[360]
    DIRECTION INPUT ;
    USE SIGNAL ;
    ANTENNAGATEAREA 0.647700 ;
    ANTENNADIFFAREA 0.434700 ;
    PORT
      LAYER met2 ;
        RECT 589.350 0.000 589.630 4.000 ;
    END
  END block[360]
  PIN block[361]
    DIRECTION INPUT ;
    USE SIGNAL ;
    ANTENNAGATEAREA 0.631200 ;
    ANTENNADIFFAREA 0.434700 ;
    PORT
      LAYER met3 ;
        RECT 0.000 669.840 4.000 670.440 ;
    END
  END block[361]
  PIN block[362]
    DIRECTION INPUT ;
    USE SIGNAL ;
    ANTENNAGATEAREA 0.631200 ;
    ANTENNADIFFAREA 0.434700 ;
    PORT
      LAYER met3 ;
        RECT 0.000 442.040 4.000 442.640 ;
    END
  END block[362]
  PIN block[363]
    DIRECTION INPUT ;
    USE SIGNAL ;
    ANTENNAGATEAREA 0.631200 ;
    ANTENNADIFFAREA 0.434700 ;
    PORT
      LAYER met2 ;
        RECT 363.950 0.000 364.230 4.000 ;
    END
  END block[363]
  PIN block[364]
    DIRECTION INPUT ;
    USE SIGNAL ;
    ANTENNAGATEAREA 0.631200 ;
    ANTENNADIFFAREA 0.434700 ;
    PORT
      LAYER met3 ;
        RECT 0.000 394.440 4.000 395.040 ;
    END
  END block[364]
  PIN block[365]
    DIRECTION INPUT ;
    USE SIGNAL ;
    ANTENNAGATEAREA 0.631200 ;
    ANTENNADIFFAREA 0.434700 ;
    PORT
      LAYER met3 ;
        RECT 0.000 482.840 4.000 483.440 ;
    END
  END block[365]
  PIN block[366]
    DIRECTION INPUT ;
    USE SIGNAL ;
    ANTENNAGATEAREA 0.631200 ;
    ANTENNADIFFAREA 0.434700 ;
    PORT
      LAYER met3 ;
        RECT 0.000 622.240 4.000 622.840 ;
    END
  END block[366]
  PIN block[367]
    DIRECTION INPUT ;
    USE SIGNAL ;
    ANTENNAGATEAREA 0.631200 ;
    ANTENNADIFFAREA 0.434700 ;
    PORT
      LAYER met3 ;
        RECT 0.000 581.440 4.000 582.040 ;
    END
  END block[367]
  PIN block[368]
    DIRECTION INPUT ;
    USE SIGNAL ;
    ANTENNAGATEAREA 0.631200 ;
    ANTENNADIFFAREA 0.434700 ;
    PORT
      LAYER met3 ;
        RECT 0.000 554.240 4.000 554.840 ;
    END
  END block[368]
  PIN block[369]
    DIRECTION INPUT ;
    USE SIGNAL ;
    ANTENNAGATEAREA 0.631200 ;
    ANTENNADIFFAREA 0.434700 ;
    PORT
      LAYER met3 ;
        RECT 0.000 530.440 4.000 531.040 ;
    END
  END block[369]
  PIN block[36]
    DIRECTION INPUT ;
    USE SIGNAL ;
    ANTENNAGATEAREA 0.560700 ;
    ANTENNADIFFAREA 0.434700 ;
    PORT
      LAYER met3 ;
        RECT 0.000 346.840 4.000 347.440 ;
    END
  END block[36]
  PIN block[370]
    DIRECTION INPUT ;
    USE SIGNAL ;
    ANTENNAGATEAREA 0.631200 ;
    ANTENNADIFFAREA 0.434700 ;
    PORT
      LAYER met3 ;
        RECT 0.000 88.440 4.000 89.040 ;
    END
  END block[370]
  PIN block[371]
    DIRECTION INPUT ;
    USE SIGNAL ;
    ANTENNAGATEAREA 0.631200 ;
    ANTENNADIFFAREA 0.434700 ;
    PORT
      LAYER met3 ;
        RECT 0.000 13.640 4.000 14.240 ;
    END
  END block[371]
  PIN block[372]
    DIRECTION INPUT ;
    USE SIGNAL ;
    ANTENNAGATEAREA 0.631200 ;
    ANTENNADIFFAREA 0.434700 ;
    PORT
      LAYER met3 ;
        RECT 0.000 248.240 4.000 248.840 ;
    END
  END block[372]
  PIN block[373]
    DIRECTION INPUT ;
    USE SIGNAL ;
    ANTENNAGATEAREA 0.631200 ;
    ANTENNADIFFAREA 0.434700 ;
    PORT
      LAYER met3 ;
        RECT 0.000 340.040 4.000 340.640 ;
    END
  END block[373]
  PIN block[374]
    DIRECTION INPUT ;
    USE SIGNAL ;
    ANTENNAGATEAREA 0.631200 ;
    ANTENNADIFFAREA 0.434700 ;
    PORT
      LAYER met3 ;
        RECT 0.000 265.240 4.000 265.840 ;
    END
  END block[374]
  PIN block[375]
    DIRECTION INPUT ;
    USE SIGNAL ;
    ANTENNAGATEAREA 0.631200 ;
    ANTENNADIFFAREA 0.434700 ;
    PORT
      LAYER met3 ;
        RECT 0.000 703.840 4.000 704.440 ;
    END
  END block[375]
  PIN block[376]
    DIRECTION INPUT ;
    USE SIGNAL ;
    ANTENNAGATEAREA 0.631200 ;
    ANTENNADIFFAREA 0.434700 ;
    PORT
      LAYER met2 ;
        RECT 99.910 896.000 100.190 900.000 ;
    END
  END block[376]
  PIN block[377]
    DIRECTION INPUT ;
    USE SIGNAL ;
    ANTENNAGATEAREA 0.631200 ;
    ANTENNADIFFAREA 0.434700 ;
    PORT
      LAYER met3 ;
        RECT 0.000 663.040 4.000 663.640 ;
    END
  END block[377]
  PIN block[378]
    DIRECTION INPUT ;
    USE SIGNAL ;
    ANTENNAGATEAREA 0.631200 ;
    ANTENNADIFFAREA 0.434700 ;
    PORT
      LAYER met3 ;
        RECT 0.000 846.640 4.000 847.240 ;
    END
  END block[378]
  PIN block[379]
    DIRECTION INPUT ;
    USE SIGNAL ;
    ANTENNAGATEAREA 0.631200 ;
    ANTENNADIFFAREA 0.434700 ;
    PORT
      LAYER met2 ;
        RECT 54.830 896.000 55.110 900.000 ;
    END
  END block[379]
  PIN block[37]
    DIRECTION INPUT ;
    USE SIGNAL ;
    ANTENNAGATEAREA 0.631200 ;
    ANTENNADIFFAREA 0.434700 ;
    PORT
      LAYER met2 ;
        RECT 177.190 0.000 177.470 4.000 ;
    END
  END block[37]
  PIN block[380]
    DIRECTION INPUT ;
    USE SIGNAL ;
    ANTENNAGATEAREA 0.631200 ;
    ANTENNADIFFAREA 0.434700 ;
    PORT
      LAYER met3 ;
        RECT 0.000 833.040 4.000 833.640 ;
    END
  END block[380]
  PIN block[381]
    DIRECTION INPUT ;
    USE SIGNAL ;
    ANTENNAGATEAREA 0.631200 ;
    ANTENNADIFFAREA 0.434700 ;
    PORT
      LAYER met2 ;
        RECT 61.270 896.000 61.550 900.000 ;
    END
  END block[381]
  PIN block[382]
    DIRECTION INPUT ;
    USE SIGNAL ;
    ANTENNAGATEAREA 0.631200 ;
    ANTENNADIFFAREA 0.434700 ;
    PORT
      LAYER met3 ;
        RECT 0.000 812.640 4.000 813.240 ;
    END
  END block[382]
  PIN block[383]
    DIRECTION INPUT ;
    USE SIGNAL ;
    ANTENNAGATEAREA 0.631200 ;
    ANTENNADIFFAREA 0.434700 ;
    PORT
      LAYER met3 ;
        RECT 0.000 659.640 4.000 660.240 ;
    END
  END block[383]
  PIN block[384]
    DIRECTION INPUT ;
    USE SIGNAL ;
    ANTENNAGATEAREA 0.631200 ;
    ANTENNADIFFAREA 0.434700 ;
    PORT
      LAYER met2 ;
        RECT 515.290 0.000 515.570 4.000 ;
    END
  END block[384]
  PIN block[385]
    DIRECTION INPUT ;
    USE SIGNAL ;
    ANTENNAGATEAREA 0.631200 ;
    ANTENNADIFFAREA 0.434700 ;
    PORT
      LAYER met2 ;
        RECT 251.250 0.000 251.530 4.000 ;
    END
  END block[385]
  PIN block[386]
    DIRECTION INPUT ;
    USE SIGNAL ;
    ANTENNAGATEAREA 0.631200 ;
    ANTENNADIFFAREA 0.434700 ;
    PORT
      LAYER met2 ;
        RECT 215.830 0.000 216.110 4.000 ;
    END
  END block[386]
  PIN block[387]
    DIRECTION INPUT ;
    USE SIGNAL ;
    ANTENNAGATEAREA 0.631200 ;
    ANTENNADIFFAREA 0.434700 ;
    PORT
      LAYER met3 ;
        RECT 0.000 54.440 4.000 55.040 ;
    END
  END block[387]
  PIN block[388]
    DIRECTION INPUT ;
    USE SIGNAL ;
    ANTENNAGATEAREA 0.631200 ;
    ANTENNADIFFAREA 0.434700 ;
    PORT
      LAYER met3 ;
        RECT 0.000 102.040 4.000 102.640 ;
    END
  END block[388]
  PIN block[389]
    DIRECTION INPUT ;
    USE SIGNAL ;
    ANTENNAGATEAREA 0.631200 ;
    ANTENNADIFFAREA 0.434700 ;
    PORT
      LAYER met3 ;
        RECT 0.000 119.040 4.000 119.640 ;
    END
  END block[389]
  PIN block[38]
    DIRECTION INPUT ;
    USE SIGNAL ;
    ANTENNAGATEAREA 0.631200 ;
    ANTENNADIFFAREA 0.434700 ;
    PORT
      LAYER met3 ;
        RECT 0.000 367.240 4.000 367.840 ;
    END
  END block[38]
  PIN block[390]
    DIRECTION INPUT ;
    USE SIGNAL ;
    ANTENNAGATEAREA 0.631200 ;
    ANTENNADIFFAREA 0.434700 ;
    PORT
      LAYER met3 ;
        RECT 0.000 51.040 4.000 51.640 ;
    END
  END block[390]
  PIN block[391]
    DIRECTION INPUT ;
    USE SIGNAL ;
    ANTENNAGATEAREA 0.631200 ;
    ANTENNADIFFAREA 0.434700 ;
    PORT
      LAYER met2 ;
        RECT 212.610 0.000 212.890 4.000 ;
    END
  END block[391]
  PIN block[392]
    DIRECTION INPUT ;
    USE SIGNAL ;
    ANTENNAGATEAREA 0.631200 ;
    ANTENNADIFFAREA 0.434700 ;
    PORT
      LAYER met2 ;
        RECT 370.390 0.000 370.670 4.000 ;
    END
  END block[392]
  PIN block[393]
    DIRECTION INPUT ;
    USE SIGNAL ;
    ANTENNAGATEAREA 0.631200 ;
    ANTENNADIFFAREA 0.434700 ;
    PORT
      LAYER met3 ;
        RECT 0.000 873.840 4.000 874.440 ;
    END
  END block[393]
  PIN block[394]
    DIRECTION INPUT ;
    USE SIGNAL ;
    ANTENNAGATEAREA 0.631200 ;
    ANTENNADIFFAREA 0.434700 ;
    PORT
      LAYER met2 ;
        RECT 570.030 0.000 570.310 4.000 ;
    END
  END block[394]
  PIN block[395]
    DIRECTION INPUT ;
    USE SIGNAL ;
    ANTENNAGATEAREA 0.631200 ;
    ANTENNADIFFAREA 0.434700 ;
    PORT
      LAYER met2 ;
        RECT 595.790 0.000 596.070 4.000 ;
    END
  END block[395]
  PIN block[396]
    DIRECTION INPUT ;
    USE SIGNAL ;
    ANTENNAGATEAREA 0.631200 ;
    ANTENNADIFFAREA 0.434700 ;
    PORT
      LAYER met3 ;
        RECT 0.000 387.640 4.000 388.240 ;
    END
  END block[396]
  PIN block[397]
    DIRECTION INPUT ;
    USE SIGNAL ;
    ANTENNAGATEAREA 0.631200 ;
    ANTENNADIFFAREA 0.434700 ;
    PORT
      LAYER met2 ;
        RECT 58.050 896.000 58.330 900.000 ;
    END
  END block[397]
  PIN block[398]
    DIRECTION INPUT ;
    USE SIGNAL ;
    ANTENNAGATEAREA 0.631200 ;
    ANTENNADIFFAREA 0.434700 ;
    PORT
      LAYER met2 ;
        RECT 132.110 896.000 132.390 900.000 ;
    END
  END block[398]
  PIN block[399]
    DIRECTION INPUT ;
    USE SIGNAL ;
    ANTENNAGATEAREA 0.631200 ;
    ANTENNADIFFAREA 0.434700 ;
    PORT
      LAYER met2 ;
        RECT 177.190 896.000 177.470 900.000 ;
    END
  END block[399]
  PIN block[39]
    DIRECTION INPUT ;
    USE SIGNAL ;
    ANTENNAGATEAREA 0.631200 ;
    ANTENNADIFFAREA 0.434700 ;
    PORT
      LAYER met2 ;
        RECT 190.070 0.000 190.350 4.000 ;
    END
  END block[39]
  PIN block[3]
    DIRECTION INPUT ;
    USE SIGNAL ;
    ANTENNAGATEAREA 0.631200 ;
    ANTENNADIFFAREA 0.434700 ;
    PORT
      LAYER met2 ;
        RECT 148.210 0.000 148.490 4.000 ;
    END
  END block[3]
  PIN block[400]
    DIRECTION INPUT ;
    USE SIGNAL ;
    ANTENNAGATEAREA 0.631200 ;
    ANTENNADIFFAREA 0.434700 ;
    PORT
      LAYER met2 ;
        RECT 70.930 896.000 71.210 900.000 ;
    END
  END block[400]
  PIN block[401]
    DIRECTION INPUT ;
    USE SIGNAL ;
    ANTENNAGATEAREA 0.631200 ;
    ANTENNADIFFAREA 0.434700 ;
    PORT
      LAYER met2 ;
        RECT 45.170 896.000 45.450 900.000 ;
    END
  END block[401]
  PIN block[402]
    DIRECTION INPUT ;
    USE SIGNAL ;
    ANTENNAGATEAREA 0.631200 ;
    ANTENNADIFFAREA 0.434700 ;
    PORT
      LAYER met3 ;
        RECT 0.000 170.040 4.000 170.640 ;
    END
  END block[402]
  PIN block[403]
    DIRECTION INPUT ;
    USE SIGNAL ;
    ANTENNAGATEAREA 0.631200 ;
    ANTENNADIFFAREA 0.434700 ;
    PORT
      LAYER met3 ;
        RECT 0.000 180.240 4.000 180.840 ;
    END
  END block[403]
  PIN block[404]
    DIRECTION INPUT ;
    USE SIGNAL ;
    ANTENNAGATEAREA 0.631200 ;
    ANTENNADIFFAREA 0.434700 ;
    PORT
      LAYER met3 ;
        RECT 0.000 166.640 4.000 167.240 ;
    END
  END block[404]
  PIN block[405]
    DIRECTION INPUT ;
    USE SIGNAL ;
    ANTENNAGATEAREA 0.631200 ;
    ANTENNADIFFAREA 0.434700 ;
    PORT
      LAYER met3 ;
        RECT 0.000 129.240 4.000 129.840 ;
    END
  END block[405]
  PIN block[406]
    DIRECTION INPUT ;
    USE SIGNAL ;
    ANTENNAGATEAREA 0.631200 ;
    ANTENNADIFFAREA 0.434700 ;
    PORT
      LAYER met3 ;
        RECT 0.000 146.240 4.000 146.840 ;
    END
  END block[406]
  PIN block[407]
    DIRECTION INPUT ;
    USE SIGNAL ;
    ANTENNAGATEAREA 0.631200 ;
    ANTENNADIFFAREA 0.434700 ;
    PORT
      LAYER met2 ;
        RECT 87.030 896.000 87.310 900.000 ;
    END
  END block[407]
  PIN block[408]
    DIRECTION INPUT ;
    USE SIGNAL ;
    ANTENNAGATEAREA 0.631200 ;
    ANTENNADIFFAREA 0.434700 ;
    PORT
      LAYER met2 ;
        RECT 90.250 896.000 90.530 900.000 ;
    END
  END block[408]
  PIN block[409]
    DIRECTION INPUT ;
    USE SIGNAL ;
    ANTENNAGATEAREA 0.631200 ;
    ANTENNADIFFAREA 0.434700 ;
    PORT
      LAYER met2 ;
        RECT 244.810 896.000 245.090 900.000 ;
    END
  END block[409]
  PIN block[40]
    DIRECTION INPUT ;
    USE SIGNAL ;
    ANTENNAGATEAREA 0.631200 ;
    ANTENNADIFFAREA 0.434700 ;
    PORT
      LAYER met2 ;
        RECT 109.570 0.000 109.850 4.000 ;
    END
  END block[40]
  PIN block[410]
    DIRECTION INPUT ;
    USE SIGNAL ;
    ANTENNAGATEAREA 0.631200 ;
    ANTENNADIFFAREA 0.434700 ;
    PORT
      LAYER met2 ;
        RECT 466.990 0.000 467.270 4.000 ;
    END
  END block[410]
  PIN block[411]
    DIRECTION INPUT ;
    USE SIGNAL ;
    ANTENNAGATEAREA 0.631200 ;
    ANTENNADIFFAREA 0.434700 ;
    PORT
      LAYER met2 ;
        RECT 135.330 896.000 135.610 900.000 ;
    END
  END block[411]
  PIN block[412]
    DIRECTION INPUT ;
    USE SIGNAL ;
    ANTENNAGATEAREA 0.631200 ;
    ANTENNADIFFAREA 0.434700 ;
    PORT
      LAYER met2 ;
        RECT 67.710 896.000 67.990 900.000 ;
    END
  END block[412]
  PIN block[413]
    DIRECTION INPUT ;
    USE SIGNAL ;
    ANTENNAGATEAREA 0.631200 ;
    ANTENNADIFFAREA 0.434700 ;
    PORT
      LAYER met2 ;
        RECT 186.850 896.000 187.130 900.000 ;
    END
  END block[413]
  PIN block[414]
    DIRECTION INPUT ;
    USE SIGNAL ;
    ANTENNAGATEAREA 0.631200 ;
    ANTENNADIFFAREA 0.434700 ;
    PORT
      LAYER met2 ;
        RECT 103.130 896.000 103.410 900.000 ;
    END
  END block[414]
  PIN block[415]
    DIRECTION INPUT ;
    USE SIGNAL ;
    ANTENNAGATEAREA 0.631200 ;
    ANTENNADIFFAREA 0.434700 ;
    PORT
      LAYER met2 ;
        RECT 16.190 896.000 16.470 900.000 ;
    END
  END block[415]
  PIN block[416]
    DIRECTION INPUT ;
    USE SIGNAL ;
    ANTENNAGATEAREA 0.631200 ;
    ANTENNADIFFAREA 0.434700 ;
    PORT
      LAYER met2 ;
        RECT 524.950 0.000 525.230 4.000 ;
    END
  END block[416]
  PIN block[417]
    DIRECTION INPUT ;
    USE SIGNAL ;
    ANTENNAGATEAREA 0.631200 ;
    ANTENNADIFFAREA 0.434700 ;
    PORT
      LAYER met2 ;
        RECT 157.870 0.000 158.150 4.000 ;
    END
  END block[417]
  PIN block[418]
    DIRECTION INPUT ;
    USE SIGNAL ;
    ANTENNAGATEAREA 0.631200 ;
    ANTENNADIFFAREA 0.434700 ;
    PORT
      LAYER met2 ;
        RECT 45.170 0.000 45.450 4.000 ;
    END
  END block[418]
  PIN block[419]
    DIRECTION INPUT ;
    USE SIGNAL ;
    ANTENNAGATEAREA 0.631200 ;
    ANTENNADIFFAREA 0.434700 ;
    PORT
      LAYER met3 ;
        RECT 0.000 71.440 4.000 72.040 ;
    END
  END block[419]
  PIN block[41]
    DIRECTION INPUT ;
    USE SIGNAL ;
    ANTENNAGATEAREA 0.560700 ;
    ANTENNADIFFAREA 0.434700 ;
    PORT
      LAYER met2 ;
        RECT 32.290 0.000 32.570 4.000 ;
    END
  END block[41]
  PIN block[420]
    DIRECTION INPUT ;
    USE SIGNAL ;
    ANTENNAGATEAREA 0.631200 ;
    ANTENNADIFFAREA 0.434700 ;
    PORT
      LAYER met3 ;
        RECT 0.000 85.040 4.000 85.640 ;
    END
  END block[420]
  PIN block[421]
    DIRECTION INPUT ;
    USE SIGNAL ;
    ANTENNAGATEAREA 0.631200 ;
    ANTENNADIFFAREA 0.434700 ;
    PORT
      LAYER met3 ;
        RECT 0.000 40.840 4.000 41.440 ;
    END
  END block[421]
  PIN block[422]
    DIRECTION INPUT ;
    USE SIGNAL ;
    ANTENNAGATEAREA 0.631200 ;
    ANTENNADIFFAREA 0.434700 ;
    PORT
      LAYER met3 ;
        RECT 0.000 176.840 4.000 177.440 ;
    END
  END block[422]
  PIN block[423]
    DIRECTION INPUT ;
    USE SIGNAL ;
    ANTENNAGATEAREA 0.631200 ;
    ANTENNADIFFAREA 0.434700 ;
    PORT
      LAYER met2 ;
        RECT 267.350 0.000 267.630 4.000 ;
    END
  END block[423]
  PIN block[424]
    DIRECTION INPUT ;
    USE SIGNAL ;
    ANTENNAGATEAREA 0.631200 ;
    ANTENNADIFFAREA 0.434700 ;
    PORT
      LAYER met2 ;
        RECT 299.550 0.000 299.830 4.000 ;
    END
  END block[424]
  PIN block[425]
    DIRECTION INPUT ;
    USE SIGNAL ;
    ANTENNAGATEAREA 0.631200 ;
    ANTENNADIFFAREA 0.434700 ;
    PORT
      LAYER met2 ;
        RECT 254.470 896.000 254.750 900.000 ;
    END
  END block[425]
  PIN block[426]
    DIRECTION INPUT ;
    USE SIGNAL ;
    ANTENNAGATEAREA 0.631200 ;
    ANTENNADIFFAREA 0.434700 ;
    PORT
      LAYER met2 ;
        RECT 447.670 0.000 447.950 4.000 ;
    END
  END block[426]
  PIN block[427]
    DIRECTION INPUT ;
    USE SIGNAL ;
    ANTENNAGATEAREA 0.631200 ;
    ANTENNADIFFAREA 0.434700 ;
    PORT
      LAYER met2 ;
        RECT 634.430 0.000 634.710 4.000 ;
    END
  END block[427]
  PIN block[428]
    DIRECTION INPUT ;
    USE SIGNAL ;
    ANTENNAGATEAREA 0.631200 ;
    ANTENNADIFFAREA 0.434700 ;
    PORT
      LAYER met3 ;
        RECT 0.000 214.240 4.000 214.840 ;
    END
  END block[428]
  PIN block[429]
    DIRECTION INPUT ;
    USE SIGNAL ;
    ANTENNAGATEAREA 0.631200 ;
    ANTENNADIFFAREA 0.434700 ;
    PORT
      LAYER met2 ;
        RECT 25.850 896.000 26.130 900.000 ;
    END
  END block[429]
  PIN block[42]
    DIRECTION INPUT ;
    USE SIGNAL ;
    ANTENNAGATEAREA 0.647700 ;
    ANTENNADIFFAREA 0.434700 ;
    PORT
      LAYER met2 ;
        RECT 450.890 0.000 451.170 4.000 ;
    END
  END block[42]
  PIN block[430]
    DIRECTION INPUT ;
    USE SIGNAL ;
    ANTENNAGATEAREA 0.631200 ;
    ANTENNADIFFAREA 0.434700 ;
    PORT
      LAYER met2 ;
        RECT 38.730 896.000 39.010 900.000 ;
    END
  END block[430]
  PIN block[431]
    DIRECTION INPUT ;
    USE SIGNAL ;
    ANTENNAGATEAREA 0.631200 ;
    ANTENNADIFFAREA 0.434700 ;
    PORT
      LAYER met2 ;
        RECT 125.670 896.000 125.950 900.000 ;
    END
  END block[431]
  PIN block[432]
    DIRECTION INPUT ;
    USE SIGNAL ;
    ANTENNAGATEAREA 0.631200 ;
    ANTENNADIFFAREA 0.434700 ;
    PORT
      LAYER met2 ;
        RECT 41.950 896.000 42.230 900.000 ;
    END
  END block[432]
  PIN block[433]
    DIRECTION INPUT ;
    USE SIGNAL ;
    ANTENNAGATEAREA 0.631200 ;
    ANTENNADIFFAREA 0.434700 ;
    PORT
      LAYER met2 ;
        RECT 122.450 896.000 122.730 900.000 ;
    END
  END block[433]
  PIN block[434]
    DIRECTION INPUT ;
    USE SIGNAL ;
    ANTENNAGATEAREA 0.631200 ;
    ANTENNADIFFAREA 0.434700 ;
    PORT
      LAYER met3 ;
        RECT 0.000 20.440 4.000 21.040 ;
    END
  END block[434]
  PIN block[435]
    DIRECTION INPUT ;
    USE SIGNAL ;
    ANTENNAGATEAREA 0.631200 ;
    ANTENNADIFFAREA 0.434700 ;
    PORT
      LAYER met3 ;
        RECT 0.000 190.440 4.000 191.040 ;
    END
  END block[435]
  PIN block[436]
    DIRECTION INPUT ;
    USE SIGNAL ;
    ANTENNAGATEAREA 0.631200 ;
    ANTENNADIFFAREA 0.434700 ;
    PORT
      LAYER met3 ;
        RECT 0.000 125.840 4.000 126.440 ;
    END
  END block[436]
  PIN block[437]
    DIRECTION INPUT ;
    USE SIGNAL ;
    ANTENNAGATEAREA 0.631200 ;
    ANTENNADIFFAREA 0.434700 ;
    PORT
      LAYER met3 ;
        RECT 0.000 204.040 4.000 204.640 ;
    END
  END block[437]
  PIN block[438]
    DIRECTION INPUT ;
    USE SIGNAL ;
    ANTENNAGATEAREA 0.631200 ;
    ANTENNADIFFAREA 0.434700 ;
    PORT
      LAYER met3 ;
        RECT 0.000 163.240 4.000 163.840 ;
    END
  END block[438]
  PIN block[439]
    DIRECTION INPUT ;
    USE SIGNAL ;
    ANTENNAGATEAREA 0.631200 ;
    ANTENNADIFFAREA 0.434700 ;
    PORT
      LAYER met2 ;
        RECT 170.750 896.000 171.030 900.000 ;
    END
  END block[439]
  PIN block[43]
    DIRECTION INPUT ;
    USE SIGNAL ;
    ANTENNAGATEAREA 0.631200 ;
    ANTENNADIFFAREA 0.434700 ;
    PORT
      LAYER met2 ;
        RECT 347.850 0.000 348.130 4.000 ;
    END
  END block[43]
  PIN block[440]
    DIRECTION INPUT ;
    USE SIGNAL ;
    ANTENNAGATEAREA 0.631200 ;
    ANTENNADIFFAREA 0.434700 ;
    PORT
      LAYER met2 ;
        RECT 212.610 896.000 212.890 900.000 ;
    END
  END block[440]
  PIN block[441]
    DIRECTION INPUT ;
    USE SIGNAL ;
    ANTENNAGATEAREA 0.631200 ;
    ANTENNADIFFAREA 0.434700 ;
    PORT
      LAYER met2 ;
        RECT 222.270 896.000 222.550 900.000 ;
    END
  END block[441]
  PIN block[442]
    DIRECTION INPUT ;
    USE SIGNAL ;
    ANTENNAGATEAREA 0.631200 ;
    ANTENNADIFFAREA 0.434700 ;
    PORT
      LAYER met2 ;
        RECT 518.510 0.000 518.790 4.000 ;
    END
  END block[442]
  PIN block[443]
    DIRECTION INPUT ;
    USE SIGNAL ;
    ANTENNAGATEAREA 0.631200 ;
    ANTENNADIFFAREA 0.434700 ;
    PORT
      LAYER met2 ;
        RECT 206.170 896.000 206.450 900.000 ;
    END
  END block[443]
  PIN block[444]
    DIRECTION INPUT ;
    USE SIGNAL ;
    ANTENNAGATEAREA 0.631200 ;
    ANTENNADIFFAREA 0.434700 ;
    PORT
      LAYER met2 ;
        RECT 231.930 896.000 232.210 900.000 ;
    END
  END block[444]
  PIN block[445]
    DIRECTION INPUT ;
    USE SIGNAL ;
    ANTENNAGATEAREA 0.631200 ;
    ANTENNADIFFAREA 0.434700 ;
    PORT
      LAYER met2 ;
        RECT 83.810 896.000 84.090 900.000 ;
    END
  END block[445]
  PIN block[446]
    DIRECTION INPUT ;
    USE SIGNAL ;
    ANTENNAGATEAREA 0.631200 ;
    ANTENNADIFFAREA 0.434700 ;
    PORT
      LAYER met2 ;
        RECT 0.090 896.000 0.370 900.000 ;
    END
  END block[446]
  PIN block[447]
    DIRECTION INPUT ;
    USE SIGNAL ;
    ANTENNAGATEAREA 0.631200 ;
    ANTENNADIFFAREA 0.434700 ;
    PORT
      LAYER met2 ;
        RECT 106.350 896.000 106.630 900.000 ;
    END
  END block[447]
  PIN block[448]
    DIRECTION INPUT ;
    USE SIGNAL ;
    ANTENNAGATEAREA 0.631200 ;
    ANTENNADIFFAREA 0.434700 ;
    PORT
      LAYER met2 ;
        RECT 486.310 0.000 486.590 4.000 ;
    END
  END block[448]
  PIN block[449]
    DIRECTION INPUT ;
    USE SIGNAL ;
    ANTENNAGATEAREA 0.631200 ;
    ANTENNADIFFAREA 0.434700 ;
    PORT
      LAYER met2 ;
        RECT 260.910 0.000 261.190 4.000 ;
    END
  END block[449]
  PIN block[44]
    DIRECTION INPUT ;
    USE SIGNAL ;
    ANTENNAGATEAREA 0.593700 ;
    ANTENNADIFFAREA 0.434700 ;
    PORT
      LAYER met2 ;
        RECT 35.510 0.000 35.790 4.000 ;
    END
  END block[44]
  PIN block[450]
    DIRECTION INPUT ;
    USE SIGNAL ;
    ANTENNAGATEAREA 0.631200 ;
    ANTENNADIFFAREA 0.434700 ;
    PORT
      LAYER met2 ;
        RECT 225.490 0.000 225.770 4.000 ;
    END
  END block[450]
  PIN block[451]
    DIRECTION INPUT ;
    USE SIGNAL ;
    ANTENNAGATEAREA 0.631200 ;
    ANTENNADIFFAREA 0.434700 ;
    PORT
      LAYER met3 ;
        RECT 0.000 34.040 4.000 34.640 ;
    END
  END block[451]
  PIN block[452]
    DIRECTION INPUT ;
    USE SIGNAL ;
    ANTENNAGATEAREA 0.631200 ;
    ANTENNADIFFAREA 0.434700 ;
    PORT
      LAYER met3 ;
        RECT 0.000 61.240 4.000 61.840 ;
    END
  END block[452]
  PIN block[453]
    DIRECTION INPUT ;
    USE SIGNAL ;
    ANTENNAGATEAREA 0.631200 ;
    ANTENNADIFFAREA 0.434700 ;
    PORT
      LAYER met3 ;
        RECT 0.000 149.640 4.000 150.240 ;
    END
  END block[453]
  PIN block[454]
    DIRECTION INPUT ;
    USE SIGNAL ;
    ANTENNAGATEAREA 0.631200 ;
    ANTENNADIFFAREA 0.434700 ;
    PORT
      LAYER met3 ;
        RECT 0.000 207.440 4.000 208.040 ;
    END
  END block[454]
  PIN block[455]
    DIRECTION INPUT ;
    USE SIGNAL ;
    ANTENNAGATEAREA 0.631200 ;
    ANTENNADIFFAREA 0.434700 ;
    PORT
      LAYER met2 ;
        RECT 280.230 0.000 280.510 4.000 ;
    END
  END block[455]
  PIN block[456]
    DIRECTION INPUT ;
    USE SIGNAL ;
    ANTENNAGATEAREA 0.631200 ;
    ANTENNADIFFAREA 0.434700 ;
    PORT
      LAYER met2 ;
        RECT 199.730 0.000 200.010 4.000 ;
    END
  END block[456]
  PIN block[457]
    DIRECTION INPUT ;
    USE SIGNAL ;
    ANTENNAGATEAREA 0.631200 ;
    ANTENNADIFFAREA 0.434700 ;
    PORT
      LAYER met2 ;
        RECT 248.030 896.000 248.310 900.000 ;
    END
  END block[457]
  PIN block[458]
    DIRECTION INPUT ;
    USE SIGNAL ;
    ANTENNAGATEAREA 0.631200 ;
    ANTENNADIFFAREA 0.434700 ;
    PORT
      LAYER met2 ;
        RECT 380.050 0.000 380.330 4.000 ;
    END
  END block[458]
  PIN block[459]
    DIRECTION INPUT ;
    USE SIGNAL ;
    ANTENNAGATEAREA 0.631200 ;
    ANTENNADIFFAREA 0.434700 ;
    PORT
      LAYER met2 ;
        RECT 605.450 0.000 605.730 4.000 ;
    END
  END block[459]
  PIN block[45]
    DIRECTION INPUT ;
    USE SIGNAL ;
    ANTENNAGATEAREA 0.647700 ;
    ANTENNADIFFAREA 0.434700 ;
    PORT
      LAYER met2 ;
        RECT 16.190 0.000 16.470 4.000 ;
    END
  END block[45]
  PIN block[460]
    DIRECTION INPUT ;
    USE SIGNAL ;
    ANTENNAGATEAREA 0.631200 ;
    ANTENNADIFFAREA 0.434700 ;
    PORT
      LAYER met3 ;
        RECT 0.000 217.640 4.000 218.240 ;
    END
  END block[460]
  PIN block[461]
    DIRECTION INPUT ;
    USE SIGNAL ;
    ANTENNAGATEAREA 0.631200 ;
    ANTENNADIFFAREA 0.434700 ;
    PORT
      LAYER met2 ;
        RECT 119.230 896.000 119.510 900.000 ;
    END
  END block[461]
  PIN block[462]
    DIRECTION INPUT ;
    USE SIGNAL ;
    ANTENNAGATEAREA 0.631200 ;
    ANTENNADIFFAREA 0.434700 ;
    PORT
      LAYER met2 ;
        RECT 148.210 896.000 148.490 900.000 ;
    END
  END block[462]
  PIN block[463]
    DIRECTION INPUT ;
    USE SIGNAL ;
    ANTENNAGATEAREA 0.631200 ;
    ANTENNADIFFAREA 0.434700 ;
    PORT
      LAYER met2 ;
        RECT 193.290 896.000 193.570 900.000 ;
    END
  END block[463]
  PIN block[464]
    DIRECTION INPUT ;
    USE SIGNAL ;
    ANTENNAGATEAREA 0.631200 ;
    ANTENNADIFFAREA 0.434700 ;
    PORT
      LAYER met2 ;
        RECT 161.090 896.000 161.370 900.000 ;
    END
  END block[464]
  PIN block[465]
    DIRECTION INPUT ;
    USE SIGNAL ;
    ANTENNAGATEAREA 0.631200 ;
    ANTENNADIFFAREA 0.434700 ;
    PORT
      LAYER met2 ;
        RECT 141.770 896.000 142.050 900.000 ;
    END
  END block[465]
  PIN block[466]
    DIRECTION INPUT ;
    USE SIGNAL ;
    ANTENNAGATEAREA 0.631200 ;
    ANTENNADIFFAREA 0.434700 ;
    PORT
      LAYER met3 ;
        RECT 0.000 81.640 4.000 82.240 ;
    END
  END block[466]
  PIN block[467]
    DIRECTION INPUT ;
    USE SIGNAL ;
    ANTENNAGATEAREA 0.631200 ;
    ANTENNADIFFAREA 0.434700 ;
    PORT
      LAYER met3 ;
        RECT 0.000 187.040 4.000 187.640 ;
    END
  END block[467]
  PIN block[468]
    DIRECTION INPUT ;
    USE SIGNAL ;
    ANTENNAGATEAREA 0.631200 ;
    ANTENNADIFFAREA 0.434700 ;
    PORT
      LAYER met3 ;
        RECT 0.000 0.040 4.000 0.640 ;
    END
  END block[468]
  PIN block[469]
    DIRECTION INPUT ;
    USE SIGNAL ;
    ANTENNAGATEAREA 0.631200 ;
    ANTENNADIFFAREA 0.434700 ;
    PORT
      LAYER met3 ;
        RECT 0.000 200.640 4.000 201.240 ;
    END
  END block[469]
  PIN block[46]
    DIRECTION INPUT ;
    USE SIGNAL ;
    ANTENNAGATEAREA 0.631200 ;
    ANTENNADIFFAREA 0.434700 ;
    PORT
      LAYER met3 ;
        RECT 0.000 210.840 4.000 211.440 ;
    END
  END block[46]
  PIN block[470]
    DIRECTION INPUT ;
    USE SIGNAL ;
    ANTENNAGATEAREA 0.631200 ;
    ANTENNADIFFAREA 0.434700 ;
    PORT
      LAYER met3 ;
        RECT 0.000 142.840 4.000 143.440 ;
    END
  END block[470]
  PIN block[471]
    DIRECTION INPUT ;
    USE SIGNAL ;
    ANTENNAGATEAREA 0.631200 ;
    ANTENNADIFFAREA 0.434700 ;
    PORT
      LAYER met2 ;
        RECT 144.990 896.000 145.270 900.000 ;
    END
  END block[471]
  PIN block[472]
    DIRECTION INPUT ;
    USE SIGNAL ;
    ANTENNAGATEAREA 0.631200 ;
    ANTENNADIFFAREA 0.434700 ;
    PORT
      LAYER met2 ;
        RECT 3.310 896.000 3.590 900.000 ;
    END
  END block[472]
  PIN block[473]
    DIRECTION INPUT ;
    USE SIGNAL ;
    ANTENNAGATEAREA 0.631200 ;
    ANTENNADIFFAREA 0.434700 ;
    PORT
      LAYER met2 ;
        RECT 196.510 896.000 196.790 900.000 ;
    END
  END block[473]
  PIN block[474]
    DIRECTION INPUT ;
    USE SIGNAL ;
    ANTENNAGATEAREA 0.631200 ;
    ANTENNADIFFAREA 0.434700 ;
    PORT
      LAYER met2 ;
        RECT 373.610 0.000 373.890 4.000 ;
    END
  END block[474]
  PIN block[475]
    DIRECTION INPUT ;
    USE SIGNAL ;
    ANTENNAGATEAREA 0.631200 ;
    ANTENNADIFFAREA 0.434700 ;
    PORT
      LAYER met2 ;
        RECT 219.050 896.000 219.330 900.000 ;
    END
  END block[475]
  PIN block[476]
    DIRECTION INPUT ;
    USE SIGNAL ;
    ANTENNAGATEAREA 0.631200 ;
    ANTENNADIFFAREA 0.434700 ;
    PORT
      LAYER met2 ;
        RECT 19.410 896.000 19.690 900.000 ;
    END
  END block[476]
  PIN block[477]
    DIRECTION INPUT ;
    USE SIGNAL ;
    ANTENNAGATEAREA 0.631200 ;
    ANTENNADIFFAREA 0.434700 ;
    PORT
      LAYER met2 ;
        RECT 112.790 896.000 113.070 900.000 ;
    END
  END block[477]
  PIN block[478]
    DIRECTION INPUT ;
    USE SIGNAL ;
    ANTENNAGATEAREA 0.631200 ;
    ANTENNADIFFAREA 0.434700 ;
    PORT
      LAYER met2 ;
        RECT 173.970 896.000 174.250 900.000 ;
    END
  END block[478]
  PIN block[479]
    DIRECTION INPUT ;
    USE SIGNAL ;
    ANTENNAGATEAREA 0.631200 ;
    ANTENNADIFFAREA 0.434700 ;
    PORT
      LAYER met2 ;
        RECT 128.890 896.000 129.170 900.000 ;
    END
  END block[479]
  PIN block[47]
    DIRECTION INPUT ;
    USE SIGNAL ;
    ANTENNAGATEAREA 0.593700 ;
    ANTENNADIFFAREA 0.434700 ;
    PORT
      LAYER met2 ;
        RECT 41.950 0.000 42.230 4.000 ;
    END
  END block[47]
  PIN block[480]
    DIRECTION INPUT ;
    USE SIGNAL ;
    ANTENNAGATEAREA 0.631200 ;
    ANTENNADIFFAREA 0.434700 ;
    PORT
      LAYER met2 ;
        RECT 492.750 0.000 493.030 4.000 ;
    END
  END block[480]
  PIN block[481]
    DIRECTION INPUT ;
    USE SIGNAL ;
    ANTENNAGATEAREA 0.631200 ;
    ANTENNADIFFAREA 0.434700 ;
    PORT
      LAYER met2 ;
        RECT 270.570 0.000 270.850 4.000 ;
    END
  END block[481]
  PIN block[482]
    DIRECTION INPUT ;
    USE SIGNAL ;
    ANTENNAGATEAREA 0.631200 ;
    ANTENNADIFFAREA 0.434700 ;
    PORT
      LAYER met2 ;
        RECT 254.470 0.000 254.750 4.000 ;
    END
  END block[482]
  PIN block[483]
    DIRECTION INPUT ;
    USE SIGNAL ;
    ANTENNAGATEAREA 0.631200 ;
    ANTENNADIFFAREA 0.434700 ;
    PORT
      LAYER met2 ;
        RECT 173.970 0.000 174.250 4.000 ;
    END
  END block[483]
  PIN block[484]
    DIRECTION INPUT ;
    USE SIGNAL ;
    ANTENNAGATEAREA 0.631200 ;
    ANTENNADIFFAREA 0.434700 ;
    PORT
      LAYER met2 ;
        RECT 196.510 0.000 196.790 4.000 ;
    END
  END block[484]
  PIN block[485]
    DIRECTION INPUT ;
    USE SIGNAL ;
    ANTENNAGATEAREA 0.631200 ;
    ANTENNADIFFAREA 0.434700 ;
    PORT
      LAYER met2 ;
        RECT 151.430 0.000 151.710 4.000 ;
    END
  END block[485]
  PIN block[486]
    DIRECTION INPUT ;
    USE SIGNAL ;
    ANTENNAGATEAREA 0.647700 ;
    ANTENNADIFFAREA 0.434700 ;
    PORT
      LAYER met2 ;
        RECT 99.910 0.000 100.190 4.000 ;
    END
  END block[486]
  PIN block[487]
    DIRECTION INPUT ;
    USE SIGNAL ;
    ANTENNAGATEAREA 0.647700 ;
    ANTENNADIFFAREA 0.434700 ;
    PORT
      LAYER met2 ;
        RECT 96.690 0.000 96.970 4.000 ;
    END
  END block[487]
  PIN block[488]
    DIRECTION INPUT ;
    USE SIGNAL ;
    ANTENNAGATEAREA 0.647700 ;
    ANTENNADIFFAREA 0.434700 ;
    PORT
      LAYER met2 ;
        RECT 228.710 0.000 228.990 4.000 ;
    END
  END block[488]
  PIN block[489]
    DIRECTION INPUT ;
    USE SIGNAL ;
    ANTENNAGATEAREA 0.647700 ;
    ANTENNADIFFAREA 0.434700 ;
    PORT
      LAYER met2 ;
        RECT 557.150 0.000 557.430 4.000 ;
    END
  END block[489]
  PIN block[48]
    DIRECTION INPUT ;
    USE SIGNAL ;
    ANTENNAGATEAREA 0.593700 ;
    ANTENNADIFFAREA 0.434700 ;
    PORT
      LAYER met2 ;
        RECT 157.870 896.000 158.150 900.000 ;
    END
  END block[48]
  PIN block[490]
    DIRECTION INPUT ;
    USE SIGNAL ;
    ANTENNAGATEAREA 0.647700 ;
    ANTENNADIFFAREA 0.434700 ;
    PORT
      LAYER met2 ;
        RECT 463.770 0.000 464.050 4.000 ;
    END
  END block[490]
  PIN block[491]
    DIRECTION INPUT ;
    USE SIGNAL ;
    ANTENNAGATEAREA 0.593700 ;
    ANTENNADIFFAREA 0.434700 ;
    PORT
      LAYER met2 ;
        RECT 405.810 0.000 406.090 4.000 ;
    END
  END block[491]
  PIN block[492]
    DIRECTION INPUT ;
    USE SIGNAL ;
    ANTENNAGATEAREA 0.647700 ;
    ANTENNADIFFAREA 0.434700 ;
    PORT
      LAYER met2 ;
        RECT 302.770 0.000 303.050 4.000 ;
    END
  END block[492]
  PIN block[493]
    DIRECTION INPUT ;
    USE SIGNAL ;
    ANTENNAGATEAREA 0.593700 ;
    ANTENNADIFFAREA 0.434700 ;
    PORT
      LAYER met2 ;
        RECT 402.590 0.000 402.870 4.000 ;
    END
  END block[493]
  PIN block[494]
    DIRECTION INPUT ;
    USE SIGNAL ;
    ANTENNAGATEAREA 0.593700 ;
    ANTENNADIFFAREA 0.434700 ;
    PORT
      LAYER met2 ;
        RECT 19.410 0.000 19.690 4.000 ;
    END
  END block[494]
  PIN block[495]
    DIRECTION INPUT ;
    USE SIGNAL ;
    ANTENNAGATEAREA 0.593700 ;
    ANTENNADIFFAREA 0.434700 ;
    PORT
      LAYER met2 ;
        RECT 328.530 0.000 328.810 4.000 ;
    END
  END block[495]
  PIN block[496]
    DIRECTION INPUT ;
    USE SIGNAL ;
    ANTENNAGATEAREA 0.647700 ;
    ANTENNADIFFAREA 0.434700 ;
    PORT
      LAYER met2 ;
        RECT 318.870 0.000 319.150 4.000 ;
    END
  END block[496]
  PIN block[497]
    DIRECTION INPUT ;
    USE SIGNAL ;
    ANTENNAGATEAREA 0.647700 ;
    ANTENNADIFFAREA 0.434700 ;
    PORT
      LAYER met2 ;
        RECT 354.290 0.000 354.570 4.000 ;
    END
  END block[497]
  PIN block[498]
    DIRECTION INPUT ;
    USE SIGNAL ;
    ANTENNAGATEAREA 0.631200 ;
    ANTENNADIFFAREA 0.434700 ;
    PORT
      LAYER met2 ;
        RECT 305.990 0.000 306.270 4.000 ;
    END
  END block[498]
  PIN block[499]
    DIRECTION INPUT ;
    USE SIGNAL ;
    ANTENNAGATEAREA 0.593700 ;
    ANTENNADIFFAREA 0.434700 ;
    PORT
      LAYER met2 ;
        RECT 238.370 896.000 238.650 900.000 ;
    END
  END block[499]
  PIN block[49]
    DIRECTION INPUT ;
    USE SIGNAL ;
    ANTENNAGATEAREA 0.647700 ;
    ANTENNADIFFAREA 0.434700 ;
    PORT
      LAYER met2 ;
        RECT 22.630 896.000 22.910 900.000 ;
    END
  END block[49]
  PIN block[4]
    DIRECTION INPUT ;
    USE SIGNAL ;
    ANTENNAGATEAREA 0.647700 ;
    ANTENNADIFFAREA 0.434700 ;
    PORT
      LAYER met2 ;
        RECT 83.810 0.000 84.090 4.000 ;
    END
  END block[4]
  PIN block[500]
    DIRECTION INPUT ;
    USE SIGNAL ;
    ANTENNAGATEAREA 0.647700 ;
    ANTENNADIFFAREA 0.434700 ;
    PORT
      LAYER met2 ;
        RECT 199.730 896.000 200.010 900.000 ;
    END
  END block[500]
  PIN block[501]
    DIRECTION INPUT ;
    USE SIGNAL ;
    ANTENNAGATEAREA 0.593700 ;
    ANTENNADIFFAREA 0.434700 ;
    PORT
      LAYER met2 ;
        RECT 341.410 0.000 341.690 4.000 ;
    END
  END block[501]
  PIN block[502]
    DIRECTION INPUT ;
    USE SIGNAL ;
    ANTENNAGATEAREA 0.631200 ;
    ANTENNADIFFAREA 0.434700 ;
    PORT
      LAYER met2 ;
        RECT 367.170 0.000 367.450 4.000 ;
    END
  END block[502]
  PIN block[503]
    DIRECTION INPUT ;
    USE SIGNAL ;
    ANTENNAGATEAREA 0.631200 ;
    ANTENNADIFFAREA 0.434700 ;
    PORT
      LAYER met2 ;
        RECT 183.630 896.000 183.910 900.000 ;
    END
  END block[503]
  PIN block[504]
    DIRECTION INPUT ;
    USE SIGNAL ;
    ANTENNAGATEAREA 0.631200 ;
    ANTENNADIFFAREA 0.434700 ;
    PORT
      LAYER met2 ;
        RECT 154.650 896.000 154.930 900.000 ;
    END
  END block[504]
  PIN block[505]
    DIRECTION INPUT ;
    USE SIGNAL ;
    ANTENNAGATEAREA 0.631200 ;
    ANTENNADIFFAREA 0.434700 ;
    PORT
      LAYER met2 ;
        RECT 241.590 896.000 241.870 900.000 ;
    END
  END block[505]
  PIN block[506]
    DIRECTION INPUT ;
    USE SIGNAL ;
    ANTENNAGATEAREA 0.560700 ;
    ANTENNADIFFAREA 0.434700 ;
    PORT
      LAYER met2 ;
        RECT 251.250 896.000 251.530 900.000 ;
    END
  END block[506]
  PIN block[507]
    DIRECTION INPUT ;
    USE SIGNAL ;
    ANTENNAGATEAREA 0.631200 ;
    ANTENNADIFFAREA 0.434700 ;
    PORT
      LAYER met2 ;
        RECT 51.610 896.000 51.890 900.000 ;
    END
  END block[507]
  PIN block[508]
    DIRECTION INPUT ;
    USE SIGNAL ;
    ANTENNAGATEAREA 0.631200 ;
    ANTENNADIFFAREA 0.434700 ;
    PORT
      LAYER met2 ;
        RECT 202.950 896.000 203.230 900.000 ;
    END
  END block[508]
  PIN block[509]
    DIRECTION INPUT ;
    USE SIGNAL ;
    ANTENNAGATEAREA 0.631200 ;
    ANTENNADIFFAREA 0.434700 ;
    PORT
      LAYER met2 ;
        RECT 77.370 896.000 77.650 900.000 ;
    END
  END block[509]
  PIN block[50]
    DIRECTION INPUT ;
    USE SIGNAL ;
    ANTENNAGATEAREA 0.593700 ;
    ANTENNADIFFAREA 0.434700 ;
    PORT
      LAYER met2 ;
        RECT 190.070 896.000 190.350 900.000 ;
    END
  END block[50]
  PIN block[510]
    DIRECTION INPUT ;
    USE SIGNAL ;
    ANTENNAGATEAREA 0.631200 ;
    ANTENNADIFFAREA 0.434700 ;
    PORT
      LAYER met2 ;
        RECT 9.750 896.000 10.030 900.000 ;
    END
  END block[510]
  PIN block[511]
    DIRECTION INPUT ;
    USE SIGNAL ;
    ANTENNAGATEAREA 0.647700 ;
    ANTENNADIFFAREA 0.434700 ;
    PORT
      LAYER met2 ;
        RECT 6.530 0.000 6.810 4.000 ;
    END
  END block[511]
  PIN block[51]
    DIRECTION INPUT ;
    USE SIGNAL ;
    ANTENNAGATEAREA 0.593700 ;
    ANTENNADIFFAREA 0.434700 ;
    PORT
      LAYER met2 ;
        RECT 9.750 0.000 10.030 4.000 ;
    END
  END block[51]
  PIN block[52]
    DIRECTION INPUT ;
    USE SIGNAL ;
    ANTENNAGATEAREA 0.647700 ;
    ANTENNADIFFAREA 0.434700 ;
    PORT
      LAYER met2 ;
        RECT 322.090 0.000 322.370 4.000 ;
    END
  END block[52]
  PIN block[53]
    DIRECTION INPUT ;
    USE SIGNAL ;
    ANTENNAGATEAREA 0.647700 ;
    ANTENNADIFFAREA 0.434700 ;
    PORT
      LAYER met2 ;
        RECT 376.830 0.000 377.110 4.000 ;
    END
  END block[53]
  PIN block[54]
    DIRECTION INPUT ;
    USE SIGNAL ;
    ANTENNAGATEAREA 0.647700 ;
    ANTENNADIFFAREA 0.434700 ;
    PORT
      LAYER met2 ;
        RECT 135.330 0.000 135.610 4.000 ;
    END
  END block[54]
  PIN block[55]
    DIRECTION INPUT ;
    USE SIGNAL ;
    ANTENNAGATEAREA 0.593700 ;
    ANTENNADIFFAREA 0.434700 ;
    PORT
      LAYER met2 ;
        RECT 12.970 0.000 13.250 4.000 ;
    END
  END block[55]
  PIN block[56]
    DIRECTION INPUT ;
    USE SIGNAL ;
    ANTENNAGATEAREA 0.682200 ;
    ANTENNADIFFAREA 0.434700 ;
    PORT
      LAYER met2 ;
        RECT 3.310 0.000 3.590 4.000 ;
    END
  END block[56]
  PIN block[57]
    DIRECTION INPUT ;
    USE SIGNAL ;
    ANTENNAGATEAREA 0.593700 ;
    ANTENNADIFFAREA 0.434700 ;
    PORT
      LAYER met2 ;
        RECT 70.930 0.000 71.210 4.000 ;
    END
  END block[57]
  PIN block[58]
    DIRECTION INPUT ;
    USE SIGNAL ;
    ANTENNAGATEAREA 0.647700 ;
    ANTENNADIFFAREA 0.434700 ;
    PORT
      LAYER met2 ;
        RECT 309.210 0.000 309.490 4.000 ;
    END
  END block[58]
  PIN block[59]
    DIRECTION INPUT ;
    USE SIGNAL ;
    ANTENNAGATEAREA 0.631200 ;
    ANTENNADIFFAREA 0.434700 ;
    PORT
      LAYER met2 ;
        RECT 289.890 896.000 290.170 900.000 ;
    END
  END block[59]
  PIN block[5]
    DIRECTION INPUT ;
    USE SIGNAL ;
    ANTENNAGATEAREA 0.631200 ;
    ANTENNADIFFAREA 0.434700 ;
    PORT
      LAYER met2 ;
        RECT 144.990 0.000 145.270 4.000 ;
    END
  END block[5]
  PIN block[60]
    DIRECTION INPUT ;
    USE SIGNAL ;
    ANTENNAGATEAREA 0.631200 ;
    ANTENNADIFFAREA 0.434700 ;
    PORT
      LAYER met2 ;
        RECT 286.670 896.000 286.950 900.000 ;
    END
  END block[60]
  PIN block[61]
    DIRECTION INPUT ;
    USE SIGNAL ;
    ANTENNAGATEAREA 0.631200 ;
    ANTENNADIFFAREA 0.434700 ;
    PORT
      LAYER met2 ;
        RECT 283.450 896.000 283.730 900.000 ;
    END
  END block[61]
  PIN block[62]
    DIRECTION INPUT ;
    USE SIGNAL ;
    ANTENNAGATEAREA 0.631200 ;
    ANTENNADIFFAREA 0.434700 ;
    PORT
      LAYER met2 ;
        RECT 257.690 896.000 257.970 900.000 ;
    END
  END block[62]
  PIN block[63]
    DIRECTION INPUT ;
    USE SIGNAL ;
    ANTENNAGATEAREA 0.631200 ;
    ANTENNADIFFAREA 0.434700 ;
    PORT
      LAYER met2 ;
        RECT 267.350 896.000 267.630 900.000 ;
    END
  END block[63]
  PIN block[64]
    DIRECTION INPUT ;
    USE SIGNAL ;
    ANTENNAGATEAREA 0.631200 ;
    ANTENNADIFFAREA 0.434700 ;
    PORT
      LAYER met2 ;
        RECT 315.650 0.000 315.930 4.000 ;
    END
  END block[64]
  PIN block[65]
    DIRECTION INPUT ;
    USE SIGNAL ;
    ANTENNAGATEAREA 0.631200 ;
    ANTENNADIFFAREA 0.434700 ;
    PORT
      LAYER met2 ;
        RECT 112.790 0.000 113.070 4.000 ;
    END
  END block[65]
  PIN block[66]
    DIRECTION INPUT ;
    USE SIGNAL ;
    ANTENNAGATEAREA 0.631200 ;
    ANTENNADIFFAREA 0.434700 ;
    PORT
      LAYER met2 ;
        RECT 170.750 0.000 171.030 4.000 ;
    END
  END block[66]
  PIN block[67]
    DIRECTION INPUT ;
    USE SIGNAL ;
    ANTENNAGATEAREA 0.631200 ;
    ANTENNADIFFAREA 0.434700 ;
    PORT
      LAYER met2 ;
        RECT 161.090 0.000 161.370 4.000 ;
    END
  END block[67]
  PIN block[68]
    DIRECTION INPUT ;
    USE SIGNAL ;
    ANTENNAGATEAREA 0.560700 ;
    ANTENNADIFFAREA 0.434700 ;
    PORT
      LAYER met2 ;
        RECT 193.290 0.000 193.570 4.000 ;
    END
  END block[68]
  PIN block[69]
    DIRECTION INPUT ;
    USE SIGNAL ;
    ANTENNAGATEAREA 0.631200 ;
    ANTENNADIFFAREA 0.434700 ;
    PORT
      LAYER met2 ;
        RECT 141.770 0.000 142.050 4.000 ;
    END
  END block[69]
  PIN block[6]
    DIRECTION INPUT ;
    USE SIGNAL ;
    ANTENNAGATEAREA 0.647700 ;
    ANTENNADIFFAREA 0.434700 ;
    PORT
      LAYER met2 ;
        RECT 206.170 0.000 206.450 4.000 ;
    END
  END block[6]
  PIN block[70]
    DIRECTION INPUT ;
    USE SIGNAL ;
    ANTENNAGATEAREA 0.647700 ;
    ANTENNADIFFAREA 0.434700 ;
    PORT
      LAYER met2 ;
        RECT 93.470 0.000 93.750 4.000 ;
    END
  END block[70]
  PIN block[71]
    DIRECTION INPUT ;
    USE SIGNAL ;
    ANTENNAGATEAREA 0.631200 ;
    ANTENNADIFFAREA 0.434700 ;
    PORT
      LAYER met2 ;
        RECT 231.930 0.000 232.210 4.000 ;
    END
  END block[71]
  PIN block[72]
    DIRECTION INPUT ;
    USE SIGNAL ;
    ANTENNAGATEAREA 0.631200 ;
    ANTENNADIFFAREA 0.434700 ;
    PORT
      LAYER met2 ;
        RECT 25.850 0.000 26.130 4.000 ;
    END
  END block[72]
  PIN block[73]
    DIRECTION INPUT ;
    USE SIGNAL ;
    ANTENNAGATEAREA 0.560700 ;
    ANTENNADIFFAREA 0.434700 ;
    PORT
      LAYER met2 ;
        RECT 0.090 0.000 0.370 4.000 ;
    END
  END block[73]
  PIN block[74]
    DIRECTION INPUT ;
    USE SIGNAL ;
    ANTENNAGATEAREA 0.682200 ;
    ANTENNADIFFAREA 0.434700 ;
    PORT
      LAYER met2 ;
        RECT 631.210 0.000 631.490 4.000 ;
    END
  END block[74]
  PIN block[75]
    DIRECTION INPUT ;
    USE SIGNAL ;
    ANTENNAGATEAREA 0.631200 ;
    ANTENNADIFFAREA 0.434700 ;
    PORT
      LAYER met2 ;
        RECT 392.930 0.000 393.210 4.000 ;
    END
  END block[75]
  PIN block[76]
    DIRECTION INPUT ;
    USE SIGNAL ;
    ANTENNAGATEAREA 0.647700 ;
    ANTENNADIFFAREA 0.434700 ;
    PORT
      LAYER met2 ;
        RECT 183.630 0.000 183.910 4.000 ;
    END
  END block[76]
  PIN block[77]
    DIRECTION INPUT ;
    USE SIGNAL ;
    ANTENNAGATEAREA 0.647700 ;
    ANTENNADIFFAREA 0.434700 ;
    PORT
      LAYER met2 ;
        RECT 67.710 0.000 67.990 4.000 ;
    END
  END block[77]
  PIN block[78]
    DIRECTION INPUT ;
    USE SIGNAL ;
    ANTENNAGATEAREA 0.647700 ;
    ANTENNADIFFAREA 0.434700 ;
    PORT
      LAYER met2 ;
        RECT 74.150 0.000 74.430 4.000 ;
    END
  END block[78]
  PIN block[79]
    DIRECTION INPUT ;
    USE SIGNAL ;
    ANTENNAGATEAREA 0.647700 ;
    ANTENNADIFFAREA 0.434700 ;
    PORT
      LAYER met2 ;
        RECT 38.730 0.000 39.010 4.000 ;
    END
  END block[79]
  PIN block[7]
    DIRECTION INPUT ;
    USE SIGNAL ;
    ANTENNAGATEAREA 0.631200 ;
    ANTENNADIFFAREA 0.434700 ;
    PORT
      LAYER met2 ;
        RECT 219.050 0.000 219.330 4.000 ;
    END
  END block[7]
  PIN block[80]
    DIRECTION INPUT ;
    USE SIGNAL ;
    ANTENNAGATEAREA 0.593700 ;
    ANTENNADIFFAREA 0.434700 ;
    PORT
      LAYER met2 ;
        RECT 22.630 0.000 22.910 4.000 ;
    END
  END block[80]
  PIN block[81]
    DIRECTION INPUT ;
    USE SIGNAL ;
    ANTENNAGATEAREA 0.593700 ;
    ANTENNADIFFAREA 0.434700 ;
    PORT
      LAYER met2 ;
        RECT 64.490 0.000 64.770 4.000 ;
    END
  END block[81]
  PIN block[82]
    DIRECTION INPUT ;
    USE SIGNAL ;
    ANTENNAGATEAREA 0.647700 ;
    ANTENNADIFFAREA 0.434700 ;
    PORT
      LAYER met2 ;
        RECT 87.030 0.000 87.310 4.000 ;
    END
  END block[82]
  PIN block[83]
    DIRECTION INPUT ;
    USE SIGNAL ;
    ANTENNAGATEAREA 0.647700 ;
    ANTENNADIFFAREA 0.434700 ;
    PORT
      LAYER met2 ;
        RECT 167.530 0.000 167.810 4.000 ;
    END
  END block[83]
  PIN block[84]
    DIRECTION INPUT ;
    USE SIGNAL ;
    ANTENNAGATEAREA 0.647700 ;
    ANTENNADIFFAREA 0.434700 ;
    PORT
      LAYER met2 ;
        RECT 90.250 0.000 90.530 4.000 ;
    END
  END block[84]
  PIN block[85]
    DIRECTION INPUT ;
    USE SIGNAL ;
    ANTENNAGATEAREA 0.647700 ;
    ANTENNADIFFAREA 0.434700 ;
    PORT
      LAYER met2 ;
        RECT 103.130 0.000 103.410 4.000 ;
    END
  END block[85]
  PIN block[86]
    DIRECTION INPUT ;
    USE SIGNAL ;
    ANTENNAGATEAREA 0.647700 ;
    ANTENNADIFFAREA 0.434700 ;
    PORT
      LAYER met2 ;
        RECT 48.390 0.000 48.670 4.000 ;
    END
  END block[86]
  PIN block[87]
    DIRECTION INPUT ;
    USE SIGNAL ;
    ANTENNAGATEAREA 0.647700 ;
    ANTENNADIFFAREA 0.434700 ;
    PORT
      LAYER met2 ;
        RECT 61.270 0.000 61.550 4.000 ;
    END
  END block[87]
  PIN block[88]
    DIRECTION INPUT ;
    USE SIGNAL ;
    ANTENNAGATEAREA 0.631200 ;
    ANTENNADIFFAREA 0.434700 ;
    PORT
      LAYER met2 ;
        RECT 260.910 896.000 261.190 900.000 ;
    END
  END block[88]
  PIN block[89]
    DIRECTION INPUT ;
    USE SIGNAL ;
    ANTENNAGATEAREA 0.682200 ;
    ANTENNADIFFAREA 0.434700 ;
    PORT
      LAYER met2 ;
        RECT 351.070 0.000 351.350 4.000 ;
    END
  END block[89]
  PIN block[8]
    DIRECTION INPUT ;
    USE SIGNAL ;
    ANTENNAGATEAREA 0.631200 ;
    ANTENNADIFFAREA 0.434700 ;
    PORT
      LAYER met2 ;
        RECT 54.830 0.000 55.110 4.000 ;
    END
  END block[8]
  PIN block[90]
    DIRECTION INPUT ;
    USE SIGNAL ;
    ANTENNAGATEAREA 0.647700 ;
    ANTENNADIFFAREA 0.434700 ;
    PORT
      LAYER met2 ;
        RECT 338.190 0.000 338.470 4.000 ;
    END
  END block[90]
  PIN block[91]
    DIRECTION INPUT ;
    USE SIGNAL ;
    ANTENNAGATEAREA 0.631200 ;
    ANTENNADIFFAREA 0.434700 ;
    PORT
      LAYER met2 ;
        RECT 264.130 896.000 264.410 900.000 ;
    END
  END block[91]
  PIN block[92]
    DIRECTION INPUT ;
    USE SIGNAL ;
    ANTENNAGATEAREA 0.631200 ;
    ANTENNADIFFAREA 0.434700 ;
    PORT
      LAYER met2 ;
        RECT 280.230 896.000 280.510 900.000 ;
    END
  END block[92]
  PIN block[93]
    DIRECTION INPUT ;
    USE SIGNAL ;
    ANTENNAGATEAREA 0.631200 ;
    ANTENNADIFFAREA 0.434700 ;
    PORT
      LAYER met2 ;
        RECT 270.570 896.000 270.850 900.000 ;
    END
  END block[93]
  PIN block[94]
    DIRECTION INPUT ;
    USE SIGNAL ;
    ANTENNAGATEAREA 0.631200 ;
    ANTENNADIFFAREA 0.434700 ;
    PORT
      LAYER met2 ;
        RECT 273.790 896.000 274.070 900.000 ;
    END
  END block[94]
  PIN block[95]
    DIRECTION INPUT ;
    USE SIGNAL ;
    ANTENNAGATEAREA 0.631200 ;
    ANTENNADIFFAREA 0.434700 ;
    PORT
      LAYER met2 ;
        RECT 277.010 896.000 277.290 900.000 ;
    END
  END block[95]
  PIN block[96]
    DIRECTION INPUT ;
    USE SIGNAL ;
    ANTENNAGATEAREA 0.631200 ;
    ANTENNADIFFAREA 0.434700 ;
    PORT
      LAYER met2 ;
        RECT 334.970 0.000 335.250 4.000 ;
    END
  END block[96]
  PIN block[97]
    DIRECTION INPUT ;
    USE SIGNAL ;
    ANTENNAGATEAREA 0.631200 ;
    ANTENNADIFFAREA 0.434700 ;
    PORT
      LAYER met2 ;
        RECT 248.030 0.000 248.310 4.000 ;
    END
  END block[97]
  PIN block[98]
    DIRECTION INPUT ;
    USE SIGNAL ;
    ANTENNAGATEAREA 0.631200 ;
    ANTENNADIFFAREA 0.434700 ;
    PORT
      LAYER met2 ;
        RECT 138.550 0.000 138.830 4.000 ;
    END
  END block[98]
  PIN block[99]
    DIRECTION INPUT ;
    USE SIGNAL ;
    ANTENNAGATEAREA 0.631200 ;
    ANTENNADIFFAREA 0.434700 ;
    PORT
      LAYER met2 ;
        RECT 122.450 0.000 122.730 4.000 ;
    END
  END block[99]
  PIN block[9]
    DIRECTION INPUT ;
    USE SIGNAL ;
    ANTENNAGATEAREA 0.560700 ;
    ANTENNADIFFAREA 0.434700 ;
    PORT
      LAYER met2 ;
        RECT 293.110 0.000 293.390 4.000 ;
    END
  END block[9]
  PIN busy
    DIRECTION OUTPUT ;
    USE SIGNAL ;
    ANTENNADIFFAREA 0.340600 ;
    PORT
      LAYER met2 ;
        RECT 421.910 0.000 422.190 4.000 ;
    END
  END busy
  PIN clk
    DIRECTION INPUT ;
    USE SIGNAL ;
    ANTENNAGATEAREA 1.286700 ;
    ANTENNADIFFAREA 0.434700 ;
    PORT
      LAYER met2 ;
        RECT 640.870 0.000 641.150 4.000 ;
    END
  END clk
  PIN digest[0]
    DIRECTION OUTPUT ;
    USE SIGNAL ;
    ANTENNADIFFAREA 0.340600 ;
    PORT
      LAYER met2 ;
        RECT 483.090 0.000 483.370 4.000 ;
    END
  END digest[0]
  PIN digest[100]
    DIRECTION OUTPUT ;
    USE SIGNAL ;
    ANTENNADIFFAREA 0.340600 ;
    PORT
      LAYER met2 ;
        RECT 531.390 0.000 531.670 4.000 ;
    END
  END digest[100]
  PIN digest[101]
    DIRECTION OUTPUT ;
    USE SIGNAL ;
    ANTENNADIFFAREA 0.340600 ;
    PORT
      LAYER met2 ;
        RECT 550.710 0.000 550.990 4.000 ;
    END
  END digest[101]
  PIN digest[102]
    DIRECTION OUTPUT ;
    USE SIGNAL ;
    ANTENNADIFFAREA 0.340600 ;
    PORT
      LAYER met2 ;
        RECT 473.430 0.000 473.710 4.000 ;
    END
  END digest[102]
  PIN digest[103]
    DIRECTION OUTPUT ;
    USE SIGNAL ;
    ANTENNADIFFAREA 0.340600 ;
    PORT
      LAYER met2 ;
        RECT 521.730 0.000 522.010 4.000 ;
    END
  END digest[103]
  PIN digest[104]
    DIRECTION OUTPUT ;
    USE SIGNAL ;
    ANTENNADIFFAREA 0.340600 ;
    PORT
      LAYER met2 ;
        RECT 602.230 0.000 602.510 4.000 ;
    END
  END digest[104]
  PIN digest[105]
    DIRECTION OUTPUT ;
    USE SIGNAL ;
    ANTENNADIFFAREA 0.340600 ;
    PORT
      LAYER met2 ;
        RECT 476.650 0.000 476.930 4.000 ;
    END
  END digest[105]
  PIN digest[106]
    DIRECTION OUTPUT ;
    USE SIGNAL ;
    ANTENNADIFFAREA 0.340600 ;
    PORT
      LAYER met2 ;
        RECT 460.550 0.000 460.830 4.000 ;
    END
  END digest[106]
  PIN digest[107]
    DIRECTION OUTPUT ;
    USE SIGNAL ;
    ANTENNADIFFAREA 0.340600 ;
    PORT
      LAYER met2 ;
        RECT 586.130 0.000 586.410 4.000 ;
    END
  END digest[107]
  PIN digest[108]
    DIRECTION OUTPUT ;
    USE SIGNAL ;
    ANTENNADIFFAREA 0.340600 ;
    PORT
      LAYER met3 ;
        RECT 896.000 61.240 900.000 61.840 ;
    END
  END digest[108]
  PIN digest[109]
    DIRECTION OUTPUT ;
    USE SIGNAL ;
    ANTENNADIFFAREA 0.340600 ;
    PORT
      LAYER met3 ;
        RECT 896.000 91.840 900.000 92.440 ;
    END
  END digest[109]
  PIN digest[10]
    DIRECTION OUTPUT ;
    USE SIGNAL ;
    ANTENNADIFFAREA 0.340600 ;
    PORT
      LAYER met3 ;
        RECT 896.000 98.640 900.000 99.240 ;
    END
  END digest[10]
  PIN digest[110]
    DIRECTION OUTPUT ;
    USE SIGNAL ;
    ANTENNADIFFAREA 0.340600 ;
    PORT
      LAYER met3 ;
        RECT 896.000 676.640 900.000 677.240 ;
    END
  END digest[110]
  PIN digest[111]
    DIRECTION OUTPUT ;
    USE SIGNAL ;
    ANTENNADIFFAREA 0.340600 ;
    PORT
      LAYER met3 ;
        RECT 896.000 663.040 900.000 663.640 ;
    END
  END digest[111]
  PIN digest[112]
    DIRECTION OUTPUT ;
    USE SIGNAL ;
    ANTENNADIFFAREA 0.340600 ;
    PORT
      LAYER met2 ;
        RECT 444.450 0.000 444.730 4.000 ;
    END
  END digest[112]
  PIN digest[113]
    DIRECTION OUTPUT ;
    USE SIGNAL ;
    ANTENNADIFFAREA 0.340600 ;
    PORT
      LAYER met2 ;
        RECT 425.130 0.000 425.410 4.000 ;
    END
  END digest[113]
  PIN digest[114]
    DIRECTION OUTPUT ;
    USE SIGNAL ;
    ANTENNADIFFAREA 0.340600 ;
    PORT
      LAYER met2 ;
        RECT 409.030 0.000 409.310 4.000 ;
    END
  END digest[114]
  PIN digest[115]
    DIRECTION OUTPUT ;
    USE SIGNAL ;
    ANTENNADIFFAREA 0.340600 ;
    PORT
      LAYER met2 ;
        RECT 528.170 0.000 528.450 4.000 ;
    END
  END digest[115]
  PIN digest[116]
    DIRECTION OUTPUT ;
    USE SIGNAL ;
    ANTENNADIFFAREA 0.340600 ;
    PORT
      LAYER met2 ;
        RECT 869.490 896.000 869.770 900.000 ;
    END
  END digest[116]
  PIN digest[117]
    DIRECTION OUTPUT ;
    USE SIGNAL ;
    ANTENNADIFFAREA 0.340600 ;
    PORT
      LAYER met2 ;
        RECT 856.610 896.000 856.890 900.000 ;
    END
  END digest[117]
  PIN digest[118]
    DIRECTION OUTPUT ;
    USE SIGNAL ;
    ANTENNADIFFAREA 0.340600 ;
    PORT
      LAYER met2 ;
        RECT 296.330 896.000 296.610 900.000 ;
    END
  END digest[118]
  PIN digest[119]
    DIRECTION OUTPUT ;
    USE SIGNAL ;
    ANTENNADIFFAREA 0.340600 ;
    PORT
      LAYER met2 ;
        RECT 309.210 896.000 309.490 900.000 ;
    END
  END digest[119]
  PIN digest[11]
    DIRECTION OUTPUT ;
    USE SIGNAL ;
    ANTENNADIFFAREA 0.340600 ;
    PORT
      LAYER met3 ;
        RECT 896.000 326.440 900.000 327.040 ;
    END
  END digest[11]
  PIN digest[120]
    DIRECTION OUTPUT ;
    USE SIGNAL ;
    ANTENNADIFFAREA 0.340600 ;
    PORT
      LAYER met2 ;
        RECT 418.690 896.000 418.970 900.000 ;
    END
  END digest[120]
  PIN digest[121]
    DIRECTION OUTPUT ;
    USE SIGNAL ;
    ANTENNADIFFAREA 0.340600 ;
    PORT
      LAYER met2 ;
        RECT 415.470 896.000 415.750 900.000 ;
    END
  END digest[121]
  PIN digest[122]
    DIRECTION OUTPUT ;
    USE SIGNAL ;
    ANTENNADIFFAREA 0.340600 ;
    PORT
      LAYER met2 ;
        RECT 853.390 896.000 853.670 900.000 ;
    END
  END digest[122]
  PIN digest[123]
    DIRECTION OUTPUT ;
    USE SIGNAL ;
    ANTENNADIFFAREA 0.340600 ;
    PORT
      LAYER met2 ;
        RECT 840.510 896.000 840.790 900.000 ;
    END
  END digest[123]
  PIN digest[124]
    DIRECTION OUTPUT ;
    USE SIGNAL ;
    ANTENNADIFFAREA 0.340600 ;
    PORT
      LAYER met2 ;
        RECT 299.550 896.000 299.830 900.000 ;
    END
  END digest[124]
  PIN digest[125]
    DIRECTION OUTPUT ;
    USE SIGNAL ;
    ANTENNADIFFAREA 0.340600 ;
    PORT
      LAYER met2 ;
        RECT 318.870 896.000 319.150 900.000 ;
    END
  END digest[125]
  PIN digest[126]
    DIRECTION OUTPUT ;
    USE SIGNAL ;
    ANTENNADIFFAREA 0.340600 ;
    PORT
      LAYER met2 ;
        RECT 328.530 896.000 328.810 900.000 ;
    END
  END digest[126]
  PIN digest[127]
    DIRECTION OUTPUT ;
    USE SIGNAL ;
    ANTENNADIFFAREA 0.340600 ;
    PORT
      LAYER met2 ;
        RECT 322.090 896.000 322.370 900.000 ;
    END
  END digest[127]
  PIN digest[128]
    DIRECTION OUTPUT ;
    USE SIGNAL ;
    ANTENNADIFFAREA 0.340600 ;
    PORT
      LAYER met2 ;
        RECT 618.330 0.000 618.610 4.000 ;
    END
  END digest[128]
  PIN digest[129]
    DIRECTION OUTPUT ;
    USE SIGNAL ;
    ANTENNADIFFAREA 0.340600 ;
    PORT
      LAYER met2 ;
        RECT 553.930 0.000 554.210 4.000 ;
    END
  END digest[129]
  PIN digest[12]
    DIRECTION OUTPUT ;
    USE SIGNAL ;
    ANTENNADIFFAREA 0.340600 ;
    PORT
      LAYER met3 ;
        RECT 896.000 78.240 900.000 78.840 ;
    END
  END digest[12]
  PIN digest[130]
    DIRECTION OUTPUT ;
    USE SIGNAL ;
    ANTENNADIFFAREA 0.340600 ;
    PORT
      LAYER met2 ;
        RECT 731.030 0.000 731.310 4.000 ;
    END
  END digest[130]
  PIN digest[131]
    DIRECTION OUTPUT ;
    USE SIGNAL ;
    ANTENNADIFFAREA 0.340600 ;
    PORT
      LAYER met2 ;
        RECT 843.730 0.000 844.010 4.000 ;
    END
  END digest[131]
  PIN digest[132]
    DIRECTION OUTPUT ;
    USE SIGNAL ;
    ANTENNADIFFAREA 0.340600 ;
    PORT
      LAYER met2 ;
        RECT 814.750 0.000 815.030 4.000 ;
    END
  END digest[132]
  PIN digest[133]
    DIRECTION OUTPUT ;
    USE SIGNAL ;
    ANTENNADIFFAREA 0.340600 ;
    PORT
      LAYER met2 ;
        RECT 856.610 0.000 856.890 4.000 ;
    END
  END digest[133]
  PIN digest[134]
    DIRECTION OUTPUT ;
    USE SIGNAL ;
    ANTENNADIFFAREA 0.340600 ;
    PORT
      LAYER met3 ;
        RECT 896.000 112.240 900.000 112.840 ;
    END
  END digest[134]
  PIN digest[135]
    DIRECTION OUTPUT ;
    USE SIGNAL ;
    ANTENNADIFFAREA 0.340600 ;
    PORT
      LAYER met3 ;
        RECT 896.000 204.040 900.000 204.640 ;
    END
  END digest[135]
  PIN digest[136]
    DIRECTION OUTPUT ;
    USE SIGNAL ;
    ANTENNADIFFAREA 0.340600 ;
    PORT
      LAYER met3 ;
        RECT 896.000 156.440 900.000 157.040 ;
    END
  END digest[136]
  PIN digest[137]
    DIRECTION OUTPUT ;
    USE SIGNAL ;
    ANTENNADIFFAREA 0.340600 ;
    PORT
      LAYER met3 ;
        RECT 896.000 136.040 900.000 136.640 ;
    END
  END digest[137]
  PIN digest[138]
    DIRECTION OUTPUT ;
    USE SIGNAL ;
    ANTENNADIFFAREA 0.340600 ;
    PORT
      LAYER met3 ;
        RECT 896.000 346.840 900.000 347.440 ;
    END
  END digest[138]
  PIN digest[139]
    DIRECTION OUTPUT ;
    USE SIGNAL ;
    ANTENNADIFFAREA 0.340600 ;
    PORT
      LAYER met3 ;
        RECT 896.000 71.440 900.000 72.040 ;
    END
  END digest[139]
  PIN digest[13]
    DIRECTION OUTPUT ;
    USE SIGNAL ;
    ANTENNADIFFAREA 0.340600 ;
    PORT
      LAYER met3 ;
        RECT 896.000 74.840 900.000 75.440 ;
    END
  END digest[13]
  PIN digest[140]
    DIRECTION OUTPUT ;
    USE SIGNAL ;
    ANTENNADIFFAREA 0.340600 ;
    PORT
      LAYER met3 ;
        RECT 896.000 394.440 900.000 395.040 ;
    END
  END digest[140]
  PIN digest[141]
    DIRECTION OUTPUT ;
    USE SIGNAL ;
    ANTENNADIFFAREA 0.340600 ;
    PORT
      LAYER met3 ;
        RECT 896.000 401.240 900.000 401.840 ;
    END
  END digest[141]
  PIN digest[142]
    DIRECTION OUTPUT ;
    USE SIGNAL ;
    ANTENNADIFFAREA 0.340600 ;
    PORT
      LAYER met3 ;
        RECT 896.000 646.040 900.000 646.640 ;
    END
  END digest[142]
  PIN digest[143]
    DIRECTION OUTPUT ;
    USE SIGNAL ;
    ANTENNADIFFAREA 0.340600 ;
    PORT
      LAYER met3 ;
        RECT 896.000 595.040 900.000 595.640 ;
    END
  END digest[143]
  PIN digest[144]
    DIRECTION OUTPUT ;
    USE SIGNAL ;
    ANTENNADIFFAREA 0.340600 ;
    PORT
      LAYER met3 ;
        RECT 896.000 635.840 900.000 636.440 ;
    END
  END digest[144]
  PIN digest[145]
    DIRECTION OUTPUT ;
    USE SIGNAL ;
    ANTENNADIFFAREA 0.340600 ;
    PORT
      LAYER met3 ;
        RECT 896.000 581.440 900.000 582.040 ;
    END
  END digest[145]
  PIN digest[146]
    DIRECTION OUTPUT ;
    USE SIGNAL ;
    ANTENNADIFFAREA 0.340600 ;
    PORT
      LAYER met3 ;
        RECT 896.000 578.040 900.000 578.640 ;
    END
  END digest[146]
  PIN digest[147]
    DIRECTION OUTPUT ;
    USE SIGNAL ;
    ANTENNADIFFAREA 0.340600 ;
    PORT
      LAYER met3 ;
        RECT 896.000 503.240 900.000 503.840 ;
    END
  END digest[147]
  PIN digest[148]
    DIRECTION OUTPUT ;
    USE SIGNAL ;
    ANTENNADIFFAREA 0.340600 ;
    PORT
      LAYER met3 ;
        RECT 896.000 782.040 900.000 782.640 ;
    END
  END digest[148]
  PIN digest[149]
    DIRECTION OUTPUT ;
    USE SIGNAL ;
    ANTENNADIFFAREA 0.340600 ;
    PORT
      LAYER met3 ;
        RECT 896.000 731.040 900.000 731.640 ;
    END
  END digest[149]
  PIN digest[14]
    DIRECTION OUTPUT ;
    USE SIGNAL ;
    ANTENNADIFFAREA 0.340600 ;
    PORT
      LAYER met3 ;
        RECT 896.000 452.240 900.000 452.840 ;
    END
  END digest[14]
  PIN digest[150]
    DIRECTION OUTPUT ;
    USE SIGNAL ;
    ANTENNADIFFAREA 0.340600 ;
    PORT
      LAYER met3 ;
        RECT 896.000 778.640 900.000 779.240 ;
    END
  END digest[150]
  PIN digest[151]
    DIRECTION OUTPUT ;
    USE SIGNAL ;
    ANTENNADIFFAREA 0.340600 ;
    PORT
      LAYER met3 ;
        RECT 896.000 714.040 900.000 714.640 ;
    END
  END digest[151]
  PIN digest[152]
    DIRECTION OUTPUT ;
    USE SIGNAL ;
    ANTENNADIFFAREA 0.340600 ;
    PORT
      LAYER met2 ;
        RECT 830.850 896.000 831.130 900.000 ;
    END
  END digest[152]
  PIN digest[153]
    DIRECTION OUTPUT ;
    USE SIGNAL ;
    ANTENNADIFFAREA 0.340600 ;
    PORT
      LAYER met2 ;
        RECT 618.330 896.000 618.610 900.000 ;
    END
  END digest[153]
  PIN digest[154]
    DIRECTION OUTPUT ;
    USE SIGNAL ;
    ANTENNADIFFAREA 0.340600 ;
    PORT
      LAYER met2 ;
        RECT 743.910 896.000 744.190 900.000 ;
    END
  END digest[154]
  PIN digest[155]
    DIRECTION OUTPUT ;
    USE SIGNAL ;
    ANTENNADIFFAREA 0.340600 ;
    PORT
      LAYER met2 ;
        RECT 747.130 896.000 747.410 900.000 ;
    END
  END digest[155]
  PIN digest[156]
    DIRECTION OUTPUT ;
    USE SIGNAL ;
    ANTENNADIFFAREA 0.340600 ;
    PORT
      LAYER met2 ;
        RECT 589.350 896.000 589.630 900.000 ;
    END
  END digest[156]
  PIN digest[157]
    DIRECTION OUTPUT ;
    USE SIGNAL ;
    ANTENNADIFFAREA 0.340600 ;
    PORT
      LAYER met2 ;
        RECT 605.450 896.000 605.730 900.000 ;
    END
  END digest[157]
  PIN digest[158]
    DIRECTION OUTPUT ;
    USE SIGNAL ;
    ANTENNADIFFAREA 0.340600 ;
    PORT
      LAYER met2 ;
        RECT 573.250 896.000 573.530 900.000 ;
    END
  END digest[158]
  PIN digest[159]
    DIRECTION OUTPUT ;
    USE SIGNAL ;
    ANTENNADIFFAREA 0.340600 ;
    PORT
      LAYER met2 ;
        RECT 753.570 896.000 753.850 900.000 ;
    END
  END digest[159]
  PIN digest[15]
    DIRECTION OUTPUT ;
    USE SIGNAL ;
    ANTENNADIFFAREA 0.340600 ;
    PORT
      LAYER met3 ;
        RECT 896.000 476.040 900.000 476.640 ;
    END
  END digest[15]
  PIN digest[160]
    DIRECTION OUTPUT ;
    USE SIGNAL ;
    ANTENNADIFFAREA 0.340600 ;
    PORT
      LAYER met2 ;
        RECT 537.830 0.000 538.110 4.000 ;
    END
  END digest[160]
  PIN digest[161]
    DIRECTION OUTPUT ;
    USE SIGNAL ;
    ANTENNADIFFAREA 0.340600 ;
    PORT
      LAYER met2 ;
        RECT 898.470 0.000 898.750 4.000 ;
    END
  END digest[161]
  PIN digest[162]
    DIRECTION OUTPUT ;
    USE SIGNAL ;
    ANTENNADIFFAREA 0.340600 ;
    PORT
      LAYER met2 ;
        RECT 721.370 0.000 721.650 4.000 ;
    END
  END digest[162]
  PIN digest[163]
    DIRECTION OUTPUT ;
    USE SIGNAL ;
    ANTENNADIFFAREA 0.340600 ;
    PORT
      LAYER met2 ;
        RECT 866.270 0.000 866.550 4.000 ;
    END
  END digest[163]
  PIN digest[164]
    DIRECTION OUTPUT ;
    USE SIGNAL ;
    ANTENNADIFFAREA 0.340600 ;
    PORT
      LAYER met2 ;
        RECT 718.150 0.000 718.430 4.000 ;
    END
  END digest[164]
  PIN digest[165]
    DIRECTION OUTPUT ;
    USE SIGNAL ;
    ANTENNADIFFAREA 0.340600 ;
    PORT
      LAYER met2 ;
        RECT 830.850 0.000 831.130 4.000 ;
    END
  END digest[165]
  PIN digest[166]
    DIRECTION OUTPUT ;
    USE SIGNAL ;
    ANTENNADIFFAREA 0.340600 ;
    PORT
      LAYER met2 ;
        RECT 853.390 0.000 853.670 4.000 ;
    END
  END digest[166]
  PIN digest[167]
    DIRECTION OUTPUT ;
    USE SIGNAL ;
    ANTENNADIFFAREA 0.340600 ;
    PORT
      LAYER met3 ;
        RECT 896.000 238.040 900.000 238.640 ;
    END
  END digest[167]
  PIN digest[168]
    DIRECTION OUTPUT ;
    USE SIGNAL ;
    ANTENNADIFFAREA 0.340600 ;
    PORT
      LAYER met3 ;
        RECT 896.000 193.840 900.000 194.440 ;
    END
  END digest[168]
  PIN digest[169]
    DIRECTION OUTPUT ;
    USE SIGNAL ;
    ANTENNADIFFAREA 0.340600 ;
    PORT
      LAYER met3 ;
        RECT 896.000 166.640 900.000 167.240 ;
    END
  END digest[169]
  PIN digest[16]
    DIRECTION OUTPUT ;
    USE SIGNAL ;
    ANTENNADIFFAREA 0.340600 ;
    PORT
      LAYER met2 ;
        RECT 582.910 896.000 583.190 900.000 ;
    END
  END digest[16]
  PIN digest[170]
    DIRECTION OUTPUT ;
    USE SIGNAL ;
    ANTENNADIFFAREA 0.340600 ;
    PORT
      LAYER met3 ;
        RECT 896.000 306.040 900.000 306.640 ;
    END
  END digest[170]
  PIN digest[171]
    DIRECTION OUTPUT ;
    USE SIGNAL ;
    ANTENNADIFFAREA 0.340600 ;
    PORT
      LAYER met3 ;
        RECT 896.000 122.440 900.000 123.040 ;
    END
  END digest[171]
  PIN digest[172]
    DIRECTION OUTPUT ;
    USE SIGNAL ;
    ANTENNADIFFAREA 0.340600 ;
    PORT
      LAYER met3 ;
        RECT 896.000 370.640 900.000 371.240 ;
    END
  END digest[172]
  PIN digest[173]
    DIRECTION OUTPUT ;
    USE SIGNAL ;
    ANTENNADIFFAREA 0.340600 ;
    PORT
      LAYER met3 ;
        RECT 896.000 380.840 900.000 381.440 ;
    END
  END digest[173]
  PIN digest[174]
    DIRECTION OUTPUT ;
    USE SIGNAL ;
    ANTENNADIFFAREA 0.340600 ;
    PORT
      LAYER met3 ;
        RECT 896.000 605.240 900.000 605.840 ;
    END
  END digest[174]
  PIN digest[175]
    DIRECTION OUTPUT ;
    USE SIGNAL ;
    ANTENNADIFFAREA 0.340600 ;
    PORT
      LAYER met3 ;
        RECT 896.000 435.240 900.000 435.840 ;
    END
  END digest[175]
  PIN digest[176]
    DIRECTION OUTPUT ;
    USE SIGNAL ;
    ANTENNADIFFAREA 0.340600 ;
    PORT
      LAYER met3 ;
        RECT 896.000 561.040 900.000 561.640 ;
    END
  END digest[176]
  PIN digest[177]
    DIRECTION OUTPUT ;
    USE SIGNAL ;
    ANTENNADIFFAREA 0.340600 ;
    PORT
      LAYER met3 ;
        RECT 896.000 493.040 900.000 493.640 ;
    END
  END digest[177]
  PIN digest[178]
    DIRECTION OUTPUT ;
    USE SIGNAL ;
    ANTENNADIFFAREA 0.340600 ;
    PORT
      LAYER met3 ;
        RECT 896.000 496.440 900.000 497.040 ;
    END
  END digest[178]
  PIN digest[179]
    DIRECTION OUTPUT ;
    USE SIGNAL ;
    ANTENNADIFFAREA 0.340600 ;
    PORT
      LAYER met3 ;
        RECT 896.000 506.640 900.000 507.240 ;
    END
  END digest[179]
  PIN digest[17]
    DIRECTION OUTPUT ;
    USE SIGNAL ;
    ANTENNADIFFAREA 0.340600 ;
    PORT
      LAYER met2 ;
        RECT 563.590 896.000 563.870 900.000 ;
    END
  END digest[17]
  PIN digest[180]
    DIRECTION OUTPUT ;
    USE SIGNAL ;
    ANTENNADIFFAREA 0.340600 ;
    PORT
      LAYER met3 ;
        RECT 896.000 574.640 900.000 575.240 ;
    END
  END digest[180]
  PIN digest[181]
    DIRECTION OUTPUT ;
    USE SIGNAL ;
    ANTENNADIFFAREA 0.340600 ;
    PORT
      LAYER met3 ;
        RECT 896.000 571.240 900.000 571.840 ;
    END
  END digest[181]
  PIN digest[182]
    DIRECTION OUTPUT ;
    USE SIGNAL ;
    ANTENNADIFFAREA 0.340600 ;
    PORT
      LAYER met3 ;
        RECT 896.000 734.440 900.000 735.040 ;
    END
  END digest[182]
  PIN digest[183]
    DIRECTION OUTPUT ;
    USE SIGNAL ;
    ANTENNADIFFAREA 0.340600 ;
    PORT
      LAYER met3 ;
        RECT 896.000 693.640 900.000 694.240 ;
    END
  END digest[183]
  PIN digest[184]
    DIRECTION OUTPUT ;
    USE SIGNAL ;
    ANTENNADIFFAREA 0.340600 ;
    PORT
      LAYER met3 ;
        RECT 896.000 724.240 900.000 724.840 ;
    END
  END digest[184]
  PIN digest[185]
    DIRECTION OUTPUT ;
    USE SIGNAL ;
    ANTENNADIFFAREA 0.340600 ;
    PORT
      LAYER met3 ;
        RECT 896.000 737.840 900.000 738.440 ;
    END
  END digest[185]
  PIN digest[186]
    DIRECTION OUTPUT ;
    USE SIGNAL ;
    ANTENNADIFFAREA 0.340600 ;
    PORT
      LAYER met3 ;
        RECT 896.000 697.040 900.000 697.640 ;
    END
  END digest[186]
  PIN digest[187]
    DIRECTION OUTPUT ;
    USE SIGNAL ;
    ANTENNADIFFAREA 0.340600 ;
    PORT
      LAYER met3 ;
        RECT 896.000 727.640 900.000 728.240 ;
    END
  END digest[187]
  PIN digest[188]
    DIRECTION OUTPUT ;
    USE SIGNAL ;
    ANTENNADIFFAREA 0.340600 ;
    PORT
      LAYER met2 ;
        RECT 624.770 896.000 625.050 900.000 ;
    END
  END digest[188]
  PIN digest[189]
    DIRECTION OUTPUT ;
    USE SIGNAL ;
    ANTENNADIFFAREA 0.340600 ;
    PORT
      LAYER met2 ;
        RECT 615.110 896.000 615.390 900.000 ;
    END
  END digest[189]
  PIN digest[18]
    DIRECTION OUTPUT ;
    USE SIGNAL ;
    ANTENNADIFFAREA 0.340600 ;
    PORT
      LAYER met2 ;
        RECT 763.230 896.000 763.510 900.000 ;
    END
  END digest[18]
  PIN digest[190]
    DIRECTION OUTPUT ;
    USE SIGNAL ;
    ANTENNADIFFAREA 0.340600 ;
    PORT
      LAYER met2 ;
        RECT 737.470 896.000 737.750 900.000 ;
    END
  END digest[190]
  PIN digest[191]
    DIRECTION OUTPUT ;
    USE SIGNAL ;
    ANTENNADIFFAREA 0.340600 ;
    PORT
      LAYER met2 ;
        RECT 727.810 896.000 728.090 900.000 ;
    END
  END digest[191]
  PIN digest[192]
    DIRECTION OUTPUT ;
    USE SIGNAL ;
    ANTENNADIFFAREA 0.340600 ;
    PORT
      LAYER met2 ;
        RECT 795.430 0.000 795.710 4.000 ;
    END
  END digest[192]
  PIN digest[193]
    DIRECTION OUTPUT ;
    USE SIGNAL ;
    ANTENNADIFFAREA 0.340600 ;
    PORT
      LAYER met2 ;
        RECT 740.690 0.000 740.970 4.000 ;
    END
  END digest[193]
  PIN digest[194]
    DIRECTION OUTPUT ;
    USE SIGNAL ;
    ANTENNADIFFAREA 0.340600 ;
    PORT
      LAYER met2 ;
        RECT 766.450 0.000 766.730 4.000 ;
    END
  END digest[194]
  PIN digest[195]
    DIRECTION OUTPUT ;
    USE SIGNAL ;
    ANTENNADIFFAREA 0.340600 ;
    PORT
      LAYER met2 ;
        RECT 708.490 0.000 708.770 4.000 ;
    END
  END digest[195]
  PIN digest[196]
    DIRECTION OUTPUT ;
    USE SIGNAL ;
    ANTENNADIFFAREA 0.340600 ;
    PORT
      LAYER met2 ;
        RECT 727.810 0.000 728.090 4.000 ;
    END
  END digest[196]
  PIN digest[197]
    DIRECTION OUTPUT ;
    USE SIGNAL ;
    ANTENNADIFFAREA 0.340600 ;
    PORT
      LAYER met2 ;
        RECT 788.990 0.000 789.270 4.000 ;
    END
  END digest[197]
  PIN digest[198]
    DIRECTION OUTPUT ;
    USE SIGNAL ;
    ANTENNADIFFAREA 0.340600 ;
    PORT
      LAYER met2 ;
        RECT 850.170 0.000 850.450 4.000 ;
    END
  END digest[198]
  PIN digest[199]
    DIRECTION OUTPUT ;
    USE SIGNAL ;
    ANTENNADIFFAREA 0.340600 ;
    PORT
      LAYER met2 ;
        RECT 888.810 0.000 889.090 4.000 ;
    END
  END digest[199]
  PIN digest[19]
    DIRECTION OUTPUT ;
    USE SIGNAL ;
    ANTENNADIFFAREA 0.340600 ;
    PORT
      LAYER met2 ;
        RECT 766.450 896.000 766.730 900.000 ;
    END
  END digest[19]
  PIN digest[1]
    DIRECTION OUTPUT ;
    USE SIGNAL ;
    ANTENNADIFFAREA 0.340600 ;
    PORT
      LAYER met2 ;
        RECT 579.690 0.000 579.970 4.000 ;
    END
  END digest[1]
  PIN digest[200]
    DIRECTION OUTPUT ;
    USE SIGNAL ;
    ANTENNADIFFAREA 0.340600 ;
    PORT
      LAYER met3 ;
        RECT 896.000 251.640 900.000 252.240 ;
    END
  END digest[200]
  PIN digest[201]
    DIRECTION OUTPUT ;
    USE SIGNAL ;
    ANTENNADIFFAREA 0.340600 ;
    PORT
      LAYER met3 ;
        RECT 896.000 170.040 900.000 170.640 ;
    END
  END digest[201]
  PIN digest[202]
    DIRECTION OUTPUT ;
    USE SIGNAL ;
    ANTENNADIFFAREA 0.340600 ;
    PORT
      LAYER met3 ;
        RECT 896.000 299.240 900.000 299.840 ;
    END
  END digest[202]
  PIN digest[203]
    DIRECTION OUTPUT ;
    USE SIGNAL ;
    ANTENNADIFFAREA 0.340600 ;
    PORT
      LAYER met3 ;
        RECT 896.000 105.440 900.000 106.040 ;
    END
  END digest[203]
  PIN digest[204]
    DIRECTION OUTPUT ;
    USE SIGNAL ;
    ANTENNADIFFAREA 0.340600 ;
    PORT
      LAYER met3 ;
        RECT 896.000 336.640 900.000 337.240 ;
    END
  END digest[204]
  PIN digest[205]
    DIRECTION OUTPUT ;
    USE SIGNAL ;
    ANTENNADIFFAREA 0.340600 ;
    PORT
      LAYER met3 ;
        RECT 896.000 374.040 900.000 374.640 ;
    END
  END digest[205]
  PIN digest[206]
    DIRECTION OUTPUT ;
    USE SIGNAL ;
    ANTENNADIFFAREA 0.340600 ;
    PORT
      LAYER met3 ;
        RECT 896.000 469.240 900.000 469.840 ;
    END
  END digest[206]
  PIN digest[207]
    DIRECTION OUTPUT ;
    USE SIGNAL ;
    ANTENNADIFFAREA 0.340600 ;
    PORT
      LAYER met3 ;
        RECT 896.000 598.440 900.000 599.040 ;
    END
  END digest[207]
  PIN digest[208]
    DIRECTION OUTPUT ;
    USE SIGNAL ;
    ANTENNADIFFAREA 0.340600 ;
    PORT
      LAYER met3 ;
        RECT 896.000 639.240 900.000 639.840 ;
    END
  END digest[208]
  PIN digest[209]
    DIRECTION OUTPUT ;
    USE SIGNAL ;
    ANTENNADIFFAREA 0.340600 ;
    PORT
      LAYER met3 ;
        RECT 896.000 666.440 900.000 667.040 ;
    END
  END digest[209]
  PIN digest[20]
    DIRECTION OUTPUT ;
    USE SIGNAL ;
    ANTENNADIFFAREA 0.340600 ;
    PORT
      LAYER met2 ;
        RECT 611.890 896.000 612.170 900.000 ;
    END
  END digest[20]
  PIN digest[210]
    DIRECTION OUTPUT ;
    USE SIGNAL ;
    ANTENNADIFFAREA 0.340600 ;
    PORT
      LAYER met3 ;
        RECT 896.000 540.640 900.000 541.240 ;
    END
  END digest[210]
  PIN digest[211]
    DIRECTION OUTPUT ;
    USE SIGNAL ;
    ANTENNADIFFAREA 0.340600 ;
    PORT
      LAYER met3 ;
        RECT 896.000 537.240 900.000 537.840 ;
    END
  END digest[211]
  PIN digest[212]
    DIRECTION OUTPUT ;
    USE SIGNAL ;
    ANTENNADIFFAREA 0.340600 ;
    PORT
      LAYER met3 ;
        RECT 896.000 567.840 900.000 568.440 ;
    END
  END digest[212]
  PIN digest[213]
    DIRECTION OUTPUT ;
    USE SIGNAL ;
    ANTENNADIFFAREA 0.340600 ;
    PORT
      LAYER met3 ;
        RECT 896.000 554.240 900.000 554.840 ;
    END
  END digest[213]
  PIN digest[214]
    DIRECTION OUTPUT ;
    USE SIGNAL ;
    ANTENNADIFFAREA 0.340600 ;
    PORT
      LAYER met3 ;
        RECT 896.000 775.240 900.000 775.840 ;
    END
  END digest[214]
  PIN digest[215]
    DIRECTION OUTPUT ;
    USE SIGNAL ;
    ANTENNADIFFAREA 0.340600 ;
    PORT
      LAYER met3 ;
        RECT 896.000 683.440 900.000 684.040 ;
    END
  END digest[215]
  PIN digest[216]
    DIRECTION OUTPUT ;
    USE SIGNAL ;
    ANTENNADIFFAREA 0.340600 ;
    PORT
      LAYER met3 ;
        RECT 896.000 751.440 900.000 752.040 ;
    END
  END digest[216]
  PIN digest[217]
    DIRECTION OUTPUT ;
    USE SIGNAL ;
    ANTENNADIFFAREA 0.340600 ;
    PORT
      LAYER met3 ;
        RECT 896.000 700.440 900.000 701.040 ;
    END
  END digest[217]
  PIN digest[218]
    DIRECTION OUTPUT ;
    USE SIGNAL ;
    ANTENNADIFFAREA 0.340600 ;
    PORT
      LAYER met3 ;
        RECT 896.000 748.040 900.000 748.640 ;
    END
  END digest[218]
  PIN digest[219]
    DIRECTION OUTPUT ;
    USE SIGNAL ;
    ANTENNADIFFAREA 0.340600 ;
    PORT
      LAYER met3 ;
        RECT 896.000 707.240 900.000 707.840 ;
    END
  END digest[219]
  PIN digest[21]
    DIRECTION OUTPUT ;
    USE SIGNAL ;
    ANTENNADIFFAREA 0.340600 ;
    PORT
      LAYER met2 ;
        RECT 602.230 896.000 602.510 900.000 ;
    END
  END digest[21]
  PIN digest[220]
    DIRECTION OUTPUT ;
    USE SIGNAL ;
    ANTENNADIFFAREA 0.340600 ;
    PORT
      LAYER met3 ;
        RECT 896.000 720.840 900.000 721.440 ;
    END
  END digest[220]
  PIN digest[221]
    DIRECTION OUTPUT ;
    USE SIGNAL ;
    ANTENNADIFFAREA 0.340600 ;
    PORT
      LAYER met3 ;
        RECT 896.000 768.440 900.000 769.040 ;
    END
  END digest[221]
  PIN digest[222]
    DIRECTION OUTPUT ;
    USE SIGNAL ;
    ANTENNADIFFAREA 0.340600 ;
    PORT
      LAYER met3 ;
        RECT 896.000 744.640 900.000 745.240 ;
    END
  END digest[222]
  PIN digest[223]
    DIRECTION OUTPUT ;
    USE SIGNAL ;
    ANTENNADIFFAREA 0.340600 ;
    PORT
      LAYER met2 ;
        RECT 721.370 896.000 721.650 900.000 ;
    END
  END digest[223]
  PIN digest[224]
    DIRECTION OUTPUT ;
    USE SIGNAL ;
    ANTENNADIFFAREA 0.340600 ;
    PORT
      LAYER met2 ;
        RECT 772.890 0.000 773.170 4.000 ;
    END
  END digest[224]
  PIN digest[225]
    DIRECTION OUTPUT ;
    USE SIGNAL ;
    ANTENNADIFFAREA 0.340600 ;
    PORT
      LAYER met2 ;
        RECT 840.510 0.000 840.790 4.000 ;
    END
  END digest[225]
  PIN digest[226]
    DIRECTION OUTPUT ;
    USE SIGNAL ;
    ANTENNADIFFAREA 0.340600 ;
    PORT
      LAYER met2 ;
        RECT 892.030 0.000 892.310 4.000 ;
    END
  END digest[226]
  PIN digest[227]
    DIRECTION OUTPUT ;
    USE SIGNAL ;
    ANTENNADIFFAREA 0.340600 ;
    PORT
      LAYER met2 ;
        RECT 711.710 0.000 711.990 4.000 ;
    END
  END digest[227]
  PIN digest[228]
    DIRECTION OUTPUT ;
    USE SIGNAL ;
    ANTENNADIFFAREA 0.340600 ;
    PORT
      LAYER met2 ;
        RECT 837.290 0.000 837.570 4.000 ;
    END
  END digest[228]
  PIN digest[229]
    DIRECTION OUTPUT ;
    USE SIGNAL ;
    ANTENNADIFFAREA 0.340600 ;
    PORT
      LAYER met2 ;
        RECT 792.210 0.000 792.490 4.000 ;
    END
  END digest[229]
  PIN digest[22]
    DIRECTION OUTPUT ;
    USE SIGNAL ;
    ANTENNADIFFAREA 0.340600 ;
    PORT
      LAYER met2 ;
        RECT 592.570 896.000 592.850 900.000 ;
    END
  END digest[22]
  PIN digest[230]
    DIRECTION OUTPUT ;
    USE SIGNAL ;
    ANTENNADIFFAREA 0.340600 ;
    PORT
      LAYER met2 ;
        RECT 817.970 0.000 818.250 4.000 ;
    END
  END digest[230]
  PIN digest[231]
    DIRECTION OUTPUT ;
    USE SIGNAL ;
    ANTENNADIFFAREA 0.340600 ;
    PORT
      LAYER met3 ;
        RECT 896.000 214.240 900.000 214.840 ;
    END
  END digest[231]
  PIN digest[232]
    DIRECTION OUTPUT ;
    USE SIGNAL ;
    ANTENNADIFFAREA 0.340600 ;
    PORT
      LAYER met3 ;
        RECT 896.000 197.240 900.000 197.840 ;
    END
  END digest[232]
  PIN digest[233]
    DIRECTION OUTPUT ;
    USE SIGNAL ;
    ANTENNADIFFAREA 0.340600 ;
    PORT
      LAYER met3 ;
        RECT 896.000 173.440 900.000 174.040 ;
    END
  END digest[233]
  PIN digest[234]
    DIRECTION OUTPUT ;
    USE SIGNAL ;
    ANTENNADIFFAREA 0.340600 ;
    PORT
      LAYER met3 ;
        RECT 896.000 302.640 900.000 303.240 ;
    END
  END digest[234]
  PIN digest[235]
    DIRECTION OUTPUT ;
    USE SIGNAL ;
    ANTENNADIFFAREA 0.340600 ;
    PORT
      LAYER met3 ;
        RECT 896.000 323.040 900.000 323.640 ;
    END
  END digest[235]
  PIN digest[236]
    DIRECTION OUTPUT ;
    USE SIGNAL ;
    ANTENNADIFFAREA 0.340600 ;
    PORT
      LAYER met3 ;
        RECT 896.000 343.440 900.000 344.040 ;
    END
  END digest[236]
  PIN digest[237]
    DIRECTION OUTPUT ;
    USE SIGNAL ;
    ANTENNADIFFAREA 0.340600 ;
    PORT
      LAYER met3 ;
        RECT 896.000 353.640 900.000 354.240 ;
    END
  END digest[237]
  PIN digest[238]
    DIRECTION OUTPUT ;
    USE SIGNAL ;
    ANTENNADIFFAREA 0.340600 ;
    PORT
      LAYER met3 ;
        RECT 896.000 408.040 900.000 408.640 ;
    END
  END digest[238]
  PIN digest[239]
    DIRECTION OUTPUT ;
    USE SIGNAL ;
    ANTENNADIFFAREA 0.340600 ;
    PORT
      LAYER met3 ;
        RECT 896.000 486.240 900.000 486.840 ;
    END
  END digest[239]
  PIN digest[23]
    DIRECTION OUTPUT ;
    USE SIGNAL ;
    ANTENNADIFFAREA 0.340600 ;
    PORT
      LAYER met2 ;
        RECT 576.470 896.000 576.750 900.000 ;
    END
  END digest[23]
  PIN digest[240]
    DIRECTION OUTPUT ;
    USE SIGNAL ;
    ANTENNADIFFAREA 0.340600 ;
    PORT
      LAYER met3 ;
        RECT 896.000 462.440 900.000 463.040 ;
    END
  END digest[240]
  PIN digest[241]
    DIRECTION OUTPUT ;
    USE SIGNAL ;
    ANTENNADIFFAREA 0.340600 ;
    PORT
      LAYER met3 ;
        RECT 896.000 557.640 900.000 558.240 ;
    END
  END digest[241]
  PIN digest[242]
    DIRECTION OUTPUT ;
    USE SIGNAL ;
    ANTENNADIFFAREA 0.340600 ;
    PORT
      LAYER met3 ;
        RECT 896.000 588.240 900.000 588.840 ;
    END
  END digest[242]
  PIN digest[243]
    DIRECTION OUTPUT ;
    USE SIGNAL ;
    ANTENNADIFFAREA 0.340600 ;
    PORT
      LAYER met3 ;
        RECT 896.000 632.440 900.000 633.040 ;
    END
  END digest[243]
  PIN digest[244]
    DIRECTION OUTPUT ;
    USE SIGNAL ;
    ANTENNADIFFAREA 0.340600 ;
    PORT
      LAYER met3 ;
        RECT 896.000 601.840 900.000 602.440 ;
    END
  END digest[244]
  PIN digest[245]
    DIRECTION OUTPUT ;
    USE SIGNAL ;
    ANTENNADIFFAREA 0.340600 ;
    PORT
      LAYER met3 ;
        RECT 896.000 608.640 900.000 609.240 ;
    END
  END digest[245]
  PIN digest[246]
    DIRECTION OUTPUT ;
    USE SIGNAL ;
    ANTENNADIFFAREA 0.340600 ;
    PORT
      LAYER met2 ;
        RECT 679.510 896.000 679.790 900.000 ;
    END
  END digest[246]
  PIN digest[247]
    DIRECTION OUTPUT ;
    USE SIGNAL ;
    ANTENNADIFFAREA 0.340600 ;
    PORT
      LAYER met2 ;
        RECT 673.070 896.000 673.350 900.000 ;
    END
  END digest[247]
  PIN digest[248]
    DIRECTION OUTPUT ;
    USE SIGNAL ;
    ANTENNADIFFAREA 0.340600 ;
    PORT
      LAYER met2 ;
        RECT 705.270 896.000 705.550 900.000 ;
    END
  END digest[248]
  PIN digest[249]
    DIRECTION OUTPUT ;
    USE SIGNAL ;
    ANTENNADIFFAREA 0.340600 ;
    PORT
      LAYER met2 ;
        RECT 650.530 896.000 650.810 900.000 ;
    END
  END digest[249]
  PIN digest[24]
    DIRECTION OUTPUT ;
    USE SIGNAL ;
    ANTENNADIFFAREA 0.340600 ;
    PORT
      LAYER met2 ;
        RECT 560.370 896.000 560.650 900.000 ;
    END
  END digest[24]
  PIN digest[250]
    DIRECTION OUTPUT ;
    USE SIGNAL ;
    ANTENNADIFFAREA 0.340600 ;
    PORT
      LAYER met2 ;
        RECT 689.170 896.000 689.450 900.000 ;
    END
  END digest[250]
  PIN digest[251]
    DIRECTION OUTPUT ;
    USE SIGNAL ;
    ANTENNADIFFAREA 0.340600 ;
    PORT
      LAYER met2 ;
        RECT 666.630 896.000 666.910 900.000 ;
    END
  END digest[251]
  PIN digest[252]
    DIRECTION OUTPUT ;
    USE SIGNAL ;
    ANTENNADIFFAREA 0.340600 ;
    PORT
      LAYER met2 ;
        RECT 656.970 896.000 657.250 900.000 ;
    END
  END digest[252]
  PIN digest[253]
    DIRECTION OUTPUT ;
    USE SIGNAL ;
    ANTENNADIFFAREA 0.340600 ;
    PORT
      LAYER met2 ;
        RECT 692.390 896.000 692.670 900.000 ;
    END
  END digest[253]
  PIN digest[254]
    DIRECTION OUTPUT ;
    USE SIGNAL ;
    ANTENNADIFFAREA 0.340600 ;
    PORT
      LAYER met2 ;
        RECT 669.850 896.000 670.130 900.000 ;
    END
  END digest[254]
  PIN digest[255]
    DIRECTION OUTPUT ;
    USE SIGNAL ;
    ANTENNADIFFAREA 0.340600 ;
    PORT
      LAYER met2 ;
        RECT 640.870 896.000 641.150 900.000 ;
    END
  END digest[255]
  PIN digest[25]
    DIRECTION OUTPUT ;
    USE SIGNAL ;
    ANTENNADIFFAREA 0.340600 ;
    PORT
      LAYER met2 ;
        RECT 756.790 896.000 757.070 900.000 ;
    END
  END digest[25]
  PIN digest[26]
    DIRECTION OUTPUT ;
    USE SIGNAL ;
    ANTENNADIFFAREA 0.340600 ;
    PORT
      LAYER met2 ;
        RECT 534.610 896.000 534.890 900.000 ;
    END
  END digest[26]
  PIN digest[27]
    DIRECTION OUTPUT ;
    USE SIGNAL ;
    ANTENNADIFFAREA 0.340600 ;
    PORT
      LAYER met2 ;
        RECT 518.510 896.000 518.790 900.000 ;
    END
  END digest[27]
  PIN digest[28]
    DIRECTION OUTPUT ;
    USE SIGNAL ;
    ANTENNADIFFAREA 0.340600 ;
    PORT
      LAYER met2 ;
        RECT 824.410 896.000 824.690 900.000 ;
    END
  END digest[28]
  PIN digest[29]
    DIRECTION OUTPUT ;
    USE SIGNAL ;
    ANTENNADIFFAREA 0.340600 ;
    PORT
      LAYER met2 ;
        RECT 850.170 896.000 850.450 900.000 ;
    END
  END digest[29]
  PIN digest[2]
    DIRECTION OUTPUT ;
    USE SIGNAL ;
    ANTENNADIFFAREA 0.340600 ;
    PORT
      LAYER met2 ;
        RECT 544.270 0.000 544.550 4.000 ;
    END
  END digest[2]
  PIN digest[30]
    DIRECTION OUTPUT ;
    USE SIGNAL ;
    ANTENNADIFFAREA 0.340600 ;
    PORT
      LAYER met2 ;
        RECT 376.830 896.000 377.110 900.000 ;
    END
  END digest[30]
  PIN digest[31]
    DIRECTION OUTPUT ;
    USE SIGNAL ;
    ANTENNADIFFAREA 0.340600 ;
    PORT
      LAYER met2 ;
        RECT 866.270 896.000 866.550 900.000 ;
    END
  END digest[31]
  PIN digest[32]
    DIRECTION OUTPUT ;
    USE SIGNAL ;
    ANTENNADIFFAREA 0.340600 ;
    PORT
      LAYER met2 ;
        RECT 582.910 0.000 583.190 4.000 ;
    END
  END digest[32]
  PIN digest[33]
    DIRECTION OUTPUT ;
    USE SIGNAL ;
    ANTENNADIFFAREA 0.340600 ;
    PORT
      LAYER met2 ;
        RECT 418.690 0.000 418.970 4.000 ;
    END
  END digest[33]
  PIN digest[34]
    DIRECTION OUTPUT ;
    USE SIGNAL ;
    ANTENNADIFFAREA 0.340600 ;
    PORT
      LAYER met2 ;
        RECT 547.490 0.000 547.770 4.000 ;
    END
  END digest[34]
  PIN digest[35]
    DIRECTION OUTPUT ;
    USE SIGNAL ;
    ANTENNADIFFAREA 0.340600 ;
    PORT
      LAYER met2 ;
        RECT 399.370 0.000 399.650 4.000 ;
    END
  END digest[35]
  PIN digest[36]
    DIRECTION OUTPUT ;
    USE SIGNAL ;
    ANTENNADIFFAREA 0.340600 ;
    PORT
      LAYER met2 ;
        RECT 541.050 0.000 541.330 4.000 ;
    END
  END digest[36]
  PIN digest[37]
    DIRECTION OUTPUT ;
    USE SIGNAL ;
    ANTENNADIFFAREA 0.340600 ;
    PORT
      LAYER met2 ;
        RECT 386.490 0.000 386.770 4.000 ;
    END
  END digest[37]
  PIN digest[38]
    DIRECTION OUTPUT ;
    USE SIGNAL ;
    ANTENNADIFFAREA 0.340600 ;
    PORT
      LAYER met2 ;
        RECT 415.470 0.000 415.750 4.000 ;
    END
  END digest[38]
  PIN digest[39]
    DIRECTION OUTPUT ;
    USE SIGNAL ;
    ANTENNADIFFAREA 0.340600 ;
    PORT
      LAYER met2 ;
        RECT 479.870 0.000 480.150 4.000 ;
    END
  END digest[39]
  PIN digest[3]
    DIRECTION OUTPUT ;
    USE SIGNAL ;
    ANTENNADIFFAREA 0.340600 ;
    PORT
      LAYER met2 ;
        RECT 441.230 0.000 441.510 4.000 ;
    END
  END digest[3]
  PIN digest[40]
    DIRECTION OUTPUT ;
    USE SIGNAL ;
    ANTENNADIFFAREA 0.340600 ;
    PORT
      LAYER met2 ;
        RECT 592.570 0.000 592.850 4.000 ;
    END
  END digest[40]
  PIN digest[41]
    DIRECTION OUTPUT ;
    USE SIGNAL ;
    ANTENNADIFFAREA 0.340600 ;
    PORT
      LAYER met3 ;
        RECT 896.000 146.240 900.000 146.840 ;
    END
  END digest[41]
  PIN digest[42]
    DIRECTION OUTPUT ;
    USE SIGNAL ;
    ANTENNADIFFAREA 0.340600 ;
    PORT
      LAYER met3 ;
        RECT 896.000 309.440 900.000 310.040 ;
    END
  END digest[42]
  PIN digest[43]
    DIRECTION OUTPUT ;
    USE SIGNAL ;
    ANTENNADIFFAREA 0.340600 ;
    PORT
      LAYER met3 ;
        RECT 896.000 319.640 900.000 320.240 ;
    END
  END digest[43]
  PIN digest[44]
    DIRECTION OUTPUT ;
    USE SIGNAL ;
    ANTENNADIFFAREA 0.340600 ;
    PORT
      LAYER met3 ;
        RECT 896.000 360.440 900.000 361.040 ;
    END
  END digest[44]
  PIN digest[45]
    DIRECTION OUTPUT ;
    USE SIGNAL ;
    ANTENNADIFFAREA 0.340600 ;
    PORT
      LAYER met3 ;
        RECT 896.000 414.840 900.000 415.440 ;
    END
  END digest[45]
  PIN digest[46]
    DIRECTION OUTPUT ;
    USE SIGNAL ;
    ANTENNADIFFAREA 0.340600 ;
    PORT
      LAYER met3 ;
        RECT 896.000 425.040 900.000 425.640 ;
    END
  END digest[46]
  PIN digest[47]
    DIRECTION OUTPUT ;
    USE SIGNAL ;
    ANTENNADIFFAREA 0.340600 ;
    PORT
      LAYER met3 ;
        RECT 896.000 642.640 900.000 643.240 ;
    END
  END digest[47]
  PIN digest[48]
    DIRECTION OUTPUT ;
    USE SIGNAL ;
    ANTENNADIFFAREA 0.340600 ;
    PORT
      LAYER met2 ;
        RECT 512.070 896.000 512.350 900.000 ;
    END
  END digest[48]
  PIN digest[49]
    DIRECTION OUTPUT ;
    USE SIGNAL ;
    ANTENNADIFFAREA 0.340600 ;
    PORT
      LAYER met2 ;
        RECT 479.870 896.000 480.150 900.000 ;
    END
  END digest[49]
  PIN digest[4]
    DIRECTION OUTPUT ;
    USE SIGNAL ;
    ANTENNADIFFAREA 0.340600 ;
    PORT
      LAYER met2 ;
        RECT 434.790 0.000 435.070 4.000 ;
    END
  END digest[4]
  PIN digest[50]
    DIRECTION OUTPUT ;
    USE SIGNAL ;
    ANTENNADIFFAREA 0.340600 ;
    PORT
      LAYER met2 ;
        RECT 811.530 896.000 811.810 900.000 ;
    END
  END digest[50]
  PIN digest[51]
    DIRECTION OUTPUT ;
    USE SIGNAL ;
    ANTENNADIFFAREA 0.340600 ;
    PORT
      LAYER met2 ;
        RECT 805.090 896.000 805.370 900.000 ;
    END
  END digest[51]
  PIN digest[52]
    DIRECTION OUTPUT ;
    USE SIGNAL ;
    ANTENNADIFFAREA 0.340600 ;
    PORT
      LAYER met2 ;
        RECT 434.790 896.000 435.070 900.000 ;
    END
  END digest[52]
  PIN digest[53]
    DIRECTION OUTPUT ;
    USE SIGNAL ;
    ANTENNADIFFAREA 0.340600 ;
    PORT
      LAYER met2 ;
        RECT 817.970 896.000 818.250 900.000 ;
    END
  END digest[53]
  PIN digest[54]
    DIRECTION OUTPUT ;
    USE SIGNAL ;
    ANTENNADIFFAREA 0.340600 ;
    PORT
      LAYER met2 ;
        RECT 788.990 896.000 789.270 900.000 ;
    END
  END digest[54]
  PIN digest[55]
    DIRECTION OUTPUT ;
    USE SIGNAL ;
    ANTENNADIFFAREA 0.340600 ;
    PORT
      LAYER met2 ;
        RECT 431.570 896.000 431.850 900.000 ;
    END
  END digest[55]
  PIN digest[56]
    DIRECTION OUTPUT ;
    USE SIGNAL ;
    ANTENNADIFFAREA 0.340600 ;
    PORT
      LAYER met2 ;
        RECT 531.390 896.000 531.670 900.000 ;
    END
  END digest[56]
  PIN digest[57]
    DIRECTION OUTPUT ;
    USE SIGNAL ;
    ANTENNADIFFAREA 0.340600 ;
    PORT
      LAYER met2 ;
        RECT 524.950 896.000 525.230 900.000 ;
    END
  END digest[57]
  PIN digest[58]
    DIRECTION OUTPUT ;
    USE SIGNAL ;
    ANTENNADIFFAREA 0.340600 ;
    PORT
      LAYER met2 ;
        RECT 502.410 896.000 502.690 900.000 ;
    END
  END digest[58]
  PIN digest[59]
    DIRECTION OUTPUT ;
    USE SIGNAL ;
    ANTENNADIFFAREA 0.340600 ;
    PORT
      LAYER met2 ;
        RECT 492.750 896.000 493.030 900.000 ;
    END
  END digest[59]
  PIN digest[5]
    DIRECTION OUTPUT ;
    USE SIGNAL ;
    ANTENNADIFFAREA 0.340600 ;
    PORT
      LAYER met2 ;
        RECT 499.190 0.000 499.470 4.000 ;
    END
  END digest[5]
  PIN digest[60]
    DIRECTION OUTPUT ;
    USE SIGNAL ;
    ANTENNADIFFAREA 0.340600 ;
    PORT
      LAYER met2 ;
        RECT 814.750 896.000 815.030 900.000 ;
    END
  END digest[60]
  PIN digest[61]
    DIRECTION OUTPUT ;
    USE SIGNAL ;
    ANTENNADIFFAREA 0.340600 ;
    PORT
      LAYER met2 ;
        RECT 827.630 896.000 827.910 900.000 ;
    END
  END digest[61]
  PIN digest[62]
    DIRECTION OUTPUT ;
    USE SIGNAL ;
    ANTENNADIFFAREA 0.340600 ;
    PORT
      LAYER met2 ;
        RECT 396.150 896.000 396.430 900.000 ;
    END
  END digest[62]
  PIN digest[63]
    DIRECTION OUTPUT ;
    USE SIGNAL ;
    ANTENNADIFFAREA 0.340600 ;
    PORT
      LAYER met2 ;
        RECT 312.430 896.000 312.710 900.000 ;
    END
  END digest[63]
  PIN digest[64]
    DIRECTION OUTPUT ;
    USE SIGNAL ;
    ANTENNADIFFAREA 0.340600 ;
    PORT
      LAYER met2 ;
        RECT 389.710 0.000 389.990 4.000 ;
    END
  END digest[64]
  PIN digest[65]
    DIRECTION OUTPUT ;
    USE SIGNAL ;
    ANTENNADIFFAREA 0.340600 ;
    PORT
      LAYER met2 ;
        RECT 383.270 0.000 383.550 4.000 ;
    END
  END digest[65]
  PIN digest[66]
    DIRECTION OUTPUT ;
    USE SIGNAL ;
    ANTENNADIFFAREA 0.340600 ;
    PORT
      LAYER met2 ;
        RECT 566.810 0.000 567.090 4.000 ;
    END
  END digest[66]
  PIN digest[67]
    DIRECTION OUTPUT ;
    USE SIGNAL ;
    ANTENNADIFFAREA 0.340600 ;
    PORT
      LAYER met2 ;
        RECT 438.010 0.000 438.290 4.000 ;
    END
  END digest[67]
  PIN digest[68]
    DIRECTION OUTPUT ;
    USE SIGNAL ;
    ANTENNADIFFAREA 0.340600 ;
    PORT
      LAYER met2 ;
        RECT 560.370 0.000 560.650 4.000 ;
    END
  END digest[68]
  PIN digest[69]
    DIRECTION OUTPUT ;
    USE SIGNAL ;
    ANTENNADIFFAREA 0.340600 ;
    PORT
      LAYER met2 ;
        RECT 457.330 0.000 457.610 4.000 ;
    END
  END digest[69]
  PIN digest[6]
    DIRECTION OUTPUT ;
    USE SIGNAL ;
    ANTENNADIFFAREA 0.340600 ;
    PORT
      LAYER met2 ;
        RECT 576.470 0.000 576.750 4.000 ;
    END
  END digest[6]
  PIN digest[70]
    DIRECTION OUTPUT ;
    USE SIGNAL ;
    ANTENNADIFFAREA 0.340600 ;
    PORT
      LAYER met2 ;
        RECT 431.570 0.000 431.850 4.000 ;
    END
  END digest[70]
  PIN digest[71]
    DIRECTION OUTPUT ;
    USE SIGNAL ;
    ANTENNADIFFAREA 0.340600 ;
    PORT
      LAYER met2 ;
        RECT 512.070 0.000 512.350 4.000 ;
    END
  END digest[71]
  PIN digest[72]
    DIRECTION OUTPUT ;
    USE SIGNAL ;
    ANTENNADIFFAREA 0.340600 ;
    PORT
      LAYER met2 ;
        RECT 608.670 0.000 608.950 4.000 ;
    END
  END digest[72]
  PIN digest[73]
    DIRECTION OUTPUT ;
    USE SIGNAL ;
    ANTENNADIFFAREA 0.340600 ;
    PORT
      LAYER met2 ;
        RECT 412.250 0.000 412.530 4.000 ;
    END
  END digest[73]
  PIN digest[74]
    DIRECTION OUTPUT ;
    USE SIGNAL ;
    ANTENNADIFFAREA 0.340600 ;
    PORT
      LAYER met2 ;
        RECT 563.590 0.000 563.870 4.000 ;
    END
  END digest[74]
  PIN digest[75]
    DIRECTION OUTPUT ;
    USE SIGNAL ;
    ANTENNADIFFAREA 0.340600 ;
    PORT
      LAYER met3 ;
        RECT 896.000 272.040 900.000 272.640 ;
    END
  END digest[75]
  PIN digest[76]
    DIRECTION OUTPUT ;
    USE SIGNAL ;
    ANTENNADIFFAREA 0.340600 ;
    PORT
      LAYER met3 ;
        RECT 896.000 68.040 900.000 68.640 ;
    END
  END digest[76]
  PIN digest[77]
    DIRECTION OUTPUT ;
    USE SIGNAL ;
    ANTENNADIFFAREA 0.340600 ;
    PORT
      LAYER met3 ;
        RECT 896.000 669.840 900.000 670.440 ;
    END
  END digest[77]
  PIN digest[78]
    DIRECTION OUTPUT ;
    USE SIGNAL ;
    ANTENNADIFFAREA 0.340600 ;
    PORT
      LAYER met3 ;
        RECT 896.000 421.640 900.000 422.240 ;
    END
  END digest[78]
  PIN digest[79]
    DIRECTION OUTPUT ;
    USE SIGNAL ;
    ANTENNADIFFAREA 0.340600 ;
    PORT
      LAYER met3 ;
        RECT 896.000 656.240 900.000 656.840 ;
    END
  END digest[79]
  PIN digest[7]
    DIRECTION OUTPUT ;
    USE SIGNAL ;
    ANTENNADIFFAREA 0.340600 ;
    PORT
      LAYER met3 ;
        RECT 896.000 207.440 900.000 208.040 ;
    END
  END digest[7]
  PIN digest[80]
    DIRECTION OUTPUT ;
    USE SIGNAL ;
    ANTENNADIFFAREA 0.340600 ;
    PORT
      LAYER met2 ;
        RECT 859.830 896.000 860.110 900.000 ;
    END
  END digest[80]
  PIN digest[81]
    DIRECTION OUTPUT ;
    USE SIGNAL ;
    ANTENNADIFFAREA 0.340600 ;
    PORT
      LAYER met2 ;
        RECT 370.390 896.000 370.670 900.000 ;
    END
  END digest[81]
  PIN digest[82]
    DIRECTION OUTPUT ;
    USE SIGNAL ;
    ANTENNADIFFAREA 0.340600 ;
    PORT
      LAYER met2 ;
        RECT 357.510 896.000 357.790 900.000 ;
    END
  END digest[82]
  PIN digest[83]
    DIRECTION OUTPUT ;
    USE SIGNAL ;
    ANTENNADIFFAREA 0.340600 ;
    PORT
      LAYER met2 ;
        RECT 373.610 896.000 373.890 900.000 ;
    END
  END digest[83]
  PIN digest[84]
    DIRECTION OUTPUT ;
    USE SIGNAL ;
    ANTENNADIFFAREA 0.340600 ;
    PORT
      LAYER met2 ;
        RECT 863.050 896.000 863.330 900.000 ;
    END
  END digest[84]
  PIN digest[85]
    DIRECTION OUTPUT ;
    USE SIGNAL ;
    ANTENNADIFFAREA 0.340600 ;
    PORT
      LAYER met2 ;
        RECT 389.710 896.000 389.990 900.000 ;
    END
  END digest[85]
  PIN digest[86]
    DIRECTION OUTPUT ;
    USE SIGNAL ;
    ANTENNADIFFAREA 0.340600 ;
    PORT
      LAYER met2 ;
        RECT 325.310 896.000 325.590 900.000 ;
    END
  END digest[86]
  PIN digest[87]
    DIRECTION OUTPUT ;
    USE SIGNAL ;
    ANTENNADIFFAREA 0.340600 ;
    PORT
      LAYER met2 ;
        RECT 367.170 896.000 367.450 900.000 ;
    END
  END digest[87]
  PIN digest[88]
    DIRECTION OUTPUT ;
    USE SIGNAL ;
    ANTENNADIFFAREA 0.340600 ;
    PORT
      LAYER met2 ;
        RECT 795.430 896.000 795.710 900.000 ;
    END
  END digest[88]
  PIN digest[89]
    DIRECTION OUTPUT ;
    USE SIGNAL ;
    ANTENNADIFFAREA 0.340600 ;
    PORT
      LAYER met2 ;
        RECT 792.210 896.000 792.490 900.000 ;
    END
  END digest[89]
  PIN digest[8]
    DIRECTION OUTPUT ;
    USE SIGNAL ;
    ANTENNADIFFAREA 0.340600 ;
    PORT
      LAYER met3 ;
        RECT 896.000 258.440 900.000 259.040 ;
    END
  END digest[8]
  PIN digest[90]
    DIRECTION OUTPUT ;
    USE SIGNAL ;
    ANTENNADIFFAREA 0.340600 ;
    PORT
      LAYER met2 ;
        RECT 537.830 896.000 538.110 900.000 ;
    END
  END digest[90]
  PIN digest[91]
    DIRECTION OUTPUT ;
    USE SIGNAL ;
    ANTENNADIFFAREA 0.340600 ;
    PORT
      LAYER met2 ;
        RECT 466.990 896.000 467.270 900.000 ;
    END
  END digest[91]
  PIN digest[92]
    DIRECTION OUTPUT ;
    USE SIGNAL ;
    ANTENNADIFFAREA 0.340600 ;
    PORT
      LAYER met2 ;
        RECT 302.770 896.000 303.050 900.000 ;
    END
  END digest[92]
  PIN digest[93]
    DIRECTION OUTPUT ;
    USE SIGNAL ;
    ANTENNADIFFAREA 0.340600 ;
    PORT
      LAYER met2 ;
        RECT 334.970 896.000 335.250 900.000 ;
    END
  END digest[93]
  PIN digest[94]
    DIRECTION OUTPUT ;
    USE SIGNAL ;
    ANTENNADIFFAREA 0.340600 ;
    PORT
      LAYER met2 ;
        RECT 344.630 896.000 344.910 900.000 ;
    END
  END digest[94]
  PIN digest[95]
    DIRECTION OUTPUT ;
    USE SIGNAL ;
    ANTENNADIFFAREA 0.340600 ;
    PORT
      LAYER met2 ;
        RECT 331.750 896.000 332.030 900.000 ;
    END
  END digest[95]
  PIN digest[96]
    DIRECTION OUTPUT ;
    USE SIGNAL ;
    ANTENNADIFFAREA 0.340600 ;
    PORT
      LAYER met2 ;
        RECT 885.590 0.000 885.870 4.000 ;
    END
  END digest[96]
  PIN digest[97]
    DIRECTION OUTPUT ;
    USE SIGNAL ;
    ANTENNADIFFAREA 0.340600 ;
    PORT
      LAYER met2 ;
        RECT 673.070 0.000 673.350 4.000 ;
    END
  END digest[97]
  PIN digest[98]
    DIRECTION OUTPUT ;
    USE SIGNAL ;
    ANTENNADIFFAREA 0.340600 ;
    PORT
      LAYER met2 ;
        RECT 666.630 0.000 666.910 4.000 ;
    END
  END digest[98]
  PIN digest[99]
    DIRECTION OUTPUT ;
    USE SIGNAL ;
    ANTENNADIFFAREA 0.340600 ;
    PORT
      LAYER met2 ;
        RECT 692.390 0.000 692.670 4.000 ;
    END
  END digest[99]
  PIN digest[9]
    DIRECTION OUTPUT ;
    USE SIGNAL ;
    ANTENNADIFFAREA 0.340600 ;
    PORT
      LAYER met3 ;
        RECT 896.000 142.840 900.000 143.440 ;
    END
  END digest[9]
  PIN done
    DIRECTION OUTPUT ;
    USE SIGNAL ;
    ANTENNADIFFAREA 0.340600 ;
    PORT
      LAYER met3 ;
        RECT 896.000 282.240 900.000 282.840 ;
    END
  END done
  PIN h_in[0]
    DIRECTION INPUT ;
    USE SIGNAL ;
    ANTENNAGATEAREA 0.631200 ;
    ANTENNADIFFAREA 0.434700 ;
    PORT
      LAYER met2 ;
        RECT 782.550 0.000 782.830 4.000 ;
    END
  END h_in[0]
  PIN h_in[100]
    DIRECTION INPUT ;
    USE SIGNAL ;
    ANTENNAGATEAREA 0.560700 ;
    ANTENNADIFFAREA 0.434700 ;
    PORT
      LAYER met2 ;
        RECT 685.950 0.000 686.230 4.000 ;
    END
  END h_in[100]
  PIN h_in[101]
    DIRECTION INPUT ;
    USE SIGNAL ;
    ANTENNAGATEAREA 0.647700 ;
    ANTENNADIFFAREA 0.434700 ;
    PORT
      LAYER met2 ;
        RECT 750.350 0.000 750.630 4.000 ;
    END
  END h_in[101]
  PIN h_in[102]
    DIRECTION INPUT ;
    USE SIGNAL ;
    ANTENNAGATEAREA 0.631200 ;
    ANTENNADIFFAREA 0.434700 ;
    PORT
      LAYER met2 ;
        RECT 653.750 0.000 654.030 4.000 ;
    END
  END h_in[102]
  PIN h_in[103]
    DIRECTION INPUT ;
    USE SIGNAL ;
    ANTENNAGATEAREA 0.647700 ;
    ANTENNADIFFAREA 0.434700 ;
    PORT
      LAYER met3 ;
        RECT 896.000 217.640 900.000 218.240 ;
    END
  END h_in[103]
  PIN h_in[104]
    DIRECTION INPUT ;
    USE SIGNAL ;
    ANTENNAGATEAREA 0.593700 ;
    ANTENNADIFFAREA 0.434700 ;
    PORT
      LAYER met3 ;
        RECT 896.000 187.040 900.000 187.640 ;
    END
  END h_in[104]
  PIN h_in[105]
    DIRECTION INPUT ;
    USE SIGNAL ;
    ANTENNAGATEAREA 0.593700 ;
    ANTENNADIFFAREA 0.434700 ;
    PORT
      LAYER met3 ;
        RECT 896.000 180.240 900.000 180.840 ;
    END
  END h_in[105]
  PIN h_in[106]
    DIRECTION INPUT ;
    USE SIGNAL ;
    ANTENNAGATEAREA 0.647700 ;
    ANTENNADIFFAREA 0.434700 ;
    PORT
      LAYER met3 ;
        RECT 896.000 295.840 900.000 296.440 ;
    END
  END h_in[106]
  PIN h_in[107]
    DIRECTION INPUT ;
    USE SIGNAL ;
    ANTENNAGATEAREA 0.647700 ;
    ANTENNADIFFAREA 0.434700 ;
    PORT
      LAYER met3 ;
        RECT 896.000 132.640 900.000 133.240 ;
    END
  END h_in[107]
  PIN h_in[108]
    DIRECTION INPUT ;
    USE SIGNAL ;
    ANTENNAGATEAREA 0.647700 ;
    ANTENNADIFFAREA 0.434700 ;
    PORT
      LAYER met3 ;
        RECT 896.000 81.640 900.000 82.240 ;
    END
  END h_in[108]
  PIN h_in[109]
    DIRECTION INPUT ;
    USE SIGNAL ;
    ANTENNAGATEAREA 0.647700 ;
    ANTENNADIFFAREA 0.434700 ;
    PORT
      LAYER met3 ;
        RECT 896.000 64.640 900.000 65.240 ;
    END
  END h_in[109]
  PIN h_in[10]
    DIRECTION INPUT ;
    USE SIGNAL ;
    ANTENNAGATEAREA 0.631200 ;
    ANTENNADIFFAREA 0.434700 ;
    PORT
      LAYER met3 ;
        RECT 896.000 329.840 900.000 330.440 ;
    END
  END h_in[10]
  PIN h_in[110]
    DIRECTION INPUT ;
    USE SIGNAL ;
    ANTENNAGATEAREA 0.647700 ;
    ANTENNADIFFAREA 0.434700 ;
    PORT
      LAYER met3 ;
        RECT 896.000 404.640 900.000 405.240 ;
    END
  END h_in[110]
  PIN h_in[111]
    DIRECTION INPUT ;
    USE SIGNAL ;
    ANTENNAGATEAREA 0.593700 ;
    ANTENNADIFFAREA 0.434700 ;
    PORT
      LAYER met3 ;
        RECT 896.000 652.840 900.000 653.440 ;
    END
  END h_in[111]
  PIN h_in[112]
    DIRECTION INPUT ;
    USE SIGNAL ;
    ANTENNAGATEAREA 0.647700 ;
    ANTENNADIFFAREA 0.434700 ;
    PORT
      LAYER met2 ;
        RECT 776.110 896.000 776.390 900.000 ;
    END
  END h_in[112]
  PIN h_in[113]
    DIRECTION INPUT ;
    USE SIGNAL ;
    ANTENNAGATEAREA 0.647700 ;
    ANTENNADIFFAREA 0.434700 ;
    PORT
      LAYER met2 ;
        RECT 785.770 896.000 786.050 900.000 ;
    END
  END h_in[113]
  PIN h_in[114]
    DIRECTION INPUT ;
    USE SIGNAL ;
    ANTENNAGATEAREA 0.647700 ;
    ANTENNADIFFAREA 0.434700 ;
    PORT
      LAYER met2 ;
        RECT 441.230 896.000 441.510 900.000 ;
    END
  END h_in[114]
  PIN h_in[115]
    DIRECTION INPUT ;
    USE SIGNAL ;
    ANTENNAGATEAREA 0.647700 ;
    ANTENNADIFFAREA 0.434700 ;
    PORT
      LAYER met2 ;
        RECT 769.670 896.000 769.950 900.000 ;
    END
  END h_in[115]
  PIN h_in[116]
    DIRECTION INPUT ;
    USE SIGNAL ;
    ANTENNAGATEAREA 0.647700 ;
    ANTENNADIFFAREA 0.434700 ;
    PORT
      LAYER met2 ;
        RECT 450.890 896.000 451.170 900.000 ;
    END
  END h_in[116]
  PIN h_in[117]
    DIRECTION INPUT ;
    USE SIGNAL ;
    ANTENNAGATEAREA 0.647700 ;
    ANTENNADIFFAREA 0.434700 ;
    PORT
      LAYER met2 ;
        RECT 447.670 896.000 447.950 900.000 ;
    END
  END h_in[117]
  PIN h_in[118]
    DIRECTION INPUT ;
    USE SIGNAL ;
    ANTENNAGATEAREA 0.647700 ;
    ANTENNADIFFAREA 0.434700 ;
    PORT
      LAYER met2 ;
        RECT 383.270 896.000 383.550 900.000 ;
    END
  END h_in[118]
  PIN h_in[119]
    DIRECTION INPUT ;
    USE SIGNAL ;
    ANTENNAGATEAREA 0.647700 ;
    ANTENNADIFFAREA 0.434700 ;
    PORT
      LAYER met2 ;
        RECT 821.190 896.000 821.470 900.000 ;
    END
  END h_in[119]
  PIN h_in[11]
    DIRECTION INPUT ;
    USE SIGNAL ;
    ANTENNAGATEAREA 0.631200 ;
    ANTENNADIFFAREA 0.434700 ;
    PORT
      LAYER met3 ;
        RECT 896.000 350.240 900.000 350.840 ;
    END
  END h_in[11]
  PIN h_in[120]
    DIRECTION INPUT ;
    USE SIGNAL ;
    ANTENNAGATEAREA 0.647700 ;
    ANTENNADIFFAREA 0.434700 ;
    PORT
      LAYER met2 ;
        RECT 798.650 896.000 798.930 900.000 ;
    END
  END h_in[120]
  PIN h_in[121]
    DIRECTION INPUT ;
    USE SIGNAL ;
    ANTENNAGATEAREA 0.593700 ;
    ANTENNADIFFAREA 0.434700 ;
    PORT
      LAYER met2 ;
        RECT 505.630 896.000 505.910 900.000 ;
    END
  END h_in[121]
  PIN h_in[122]
    DIRECTION INPUT ;
    USE SIGNAL ;
    ANTENNAGATEAREA 0.647700 ;
    ANTENNADIFFAREA 0.434700 ;
    PORT
      LAYER met2 ;
        RECT 772.890 896.000 773.170 900.000 ;
    END
  END h_in[122]
  PIN h_in[123]
    DIRECTION INPUT ;
    USE SIGNAL ;
    ANTENNAGATEAREA 0.647700 ;
    ANTENNADIFFAREA 0.434700 ;
    PORT
      LAYER met2 ;
        RECT 808.310 896.000 808.590 900.000 ;
    END
  END h_in[123]
  PIN h_in[124]
    DIRECTION INPUT ;
    USE SIGNAL ;
    ANTENNAGATEAREA 0.593700 ;
    ANTENNADIFFAREA 0.434700 ;
    PORT
      LAYER met2 ;
        RECT 392.930 896.000 393.210 900.000 ;
    END
  END h_in[124]
  PIN h_in[125]
    DIRECTION INPUT ;
    USE SIGNAL ;
    ANTENNAGATEAREA 0.593700 ;
    ANTENNADIFFAREA 0.434700 ;
    PORT
      LAYER met2 ;
        RECT 360.730 896.000 361.010 900.000 ;
    END
  END h_in[125]
  PIN h_in[126]
    DIRECTION INPUT ;
    USE SIGNAL ;
    ANTENNAGATEAREA 0.631200 ;
    ANTENNADIFFAREA 0.434700 ;
    PORT
      LAYER met2 ;
        RECT 305.990 896.000 306.270 900.000 ;
    END
  END h_in[126]
  PIN h_in[127]
    DIRECTION INPUT ;
    USE SIGNAL ;
    ANTENNAGATEAREA 0.593700 ;
    ANTENNADIFFAREA 0.434700 ;
    PORT
      LAYER met2 ;
        RECT 347.850 896.000 348.130 900.000 ;
    END
  END h_in[127]
  PIN h_in[128]
    DIRECTION INPUT ;
    USE SIGNAL ;
    ANTENNAGATEAREA 0.631200 ;
    ANTENNADIFFAREA 0.434700 ;
    PORT
      LAYER met2 ;
        RECT 724.590 0.000 724.870 4.000 ;
    END
  END h_in[128]
  PIN h_in[129]
    DIRECTION INPUT ;
    USE SIGNAL ;
    ANTENNAGATEAREA 0.631200 ;
    ANTENNADIFFAREA 0.434700 ;
    PORT
      LAYER met2 ;
        RECT 753.570 0.000 753.850 4.000 ;
    END
  END h_in[129]
  PIN h_in[12]
    DIRECTION INPUT ;
    USE SIGNAL ;
    ANTENNAGATEAREA 0.631200 ;
    ANTENNADIFFAREA 0.434700 ;
    PORT
      LAYER met3 ;
        RECT 896.000 387.640 900.000 388.240 ;
    END
  END h_in[12]
  PIN h_in[130]
    DIRECTION INPUT ;
    USE SIGNAL ;
    ANTENNAGATEAREA 0.560700 ;
    ANTENNADIFFAREA 0.434700 ;
    PORT
      LAYER met2 ;
        RECT 824.410 0.000 824.690 4.000 ;
    END
  END h_in[130]
  PIN h_in[131]
    DIRECTION INPUT ;
    USE SIGNAL ;
    ANTENNAGATEAREA 0.631200 ;
    ANTENNADIFFAREA 0.434700 ;
    PORT
      LAYER met2 ;
        RECT 737.470 0.000 737.750 4.000 ;
    END
  END h_in[131]
  PIN h_in[132]
    DIRECTION INPUT ;
    USE SIGNAL ;
    ANTENNAGATEAREA 0.631200 ;
    ANTENNADIFFAREA 0.434700 ;
    PORT
      LAYER met2 ;
        RECT 801.870 0.000 802.150 4.000 ;
    END
  END h_in[132]
  PIN h_in[133]
    DIRECTION INPUT ;
    USE SIGNAL ;
    ANTENNAGATEAREA 0.647700 ;
    ANTENNADIFFAREA 0.434700 ;
    PORT
      LAYER met2 ;
        RECT 689.170 0.000 689.450 4.000 ;
    END
  END h_in[133]
  PIN h_in[134]
    DIRECTION INPUT ;
    USE SIGNAL ;
    ANTENNAGATEAREA 0.560700 ;
    ANTENNADIFFAREA 0.434700 ;
    PORT
      LAYER met3 ;
        RECT 896.000 227.840 900.000 228.440 ;
    END
  END h_in[134]
  PIN h_in[135]
    DIRECTION INPUT ;
    USE SIGNAL ;
    ANTENNAGATEAREA 0.631200 ;
    ANTENNADIFFAREA 0.434700 ;
    PORT
      LAYER met3 ;
        RECT 896.000 248.240 900.000 248.840 ;
    END
  END h_in[135]
  PIN h_in[136]
    DIRECTION INPUT ;
    USE SIGNAL ;
    ANTENNAGATEAREA 0.631200 ;
    ANTENNADIFFAREA 0.434700 ;
    PORT
      LAYER met3 ;
        RECT 896.000 275.440 900.000 276.040 ;
    END
  END h_in[136]
  PIN h_in[137]
    DIRECTION INPUT ;
    USE SIGNAL ;
    ANTENNAGATEAREA 0.631200 ;
    ANTENNADIFFAREA 0.434700 ;
    PORT
      LAYER met3 ;
        RECT 896.000 129.240 900.000 129.840 ;
    END
  END h_in[137]
  PIN h_in[138]
    DIRECTION INPUT ;
    USE SIGNAL ;
    ANTENNAGATEAREA 0.647700 ;
    ANTENNADIFFAREA 0.434700 ;
    PORT
      LAYER met3 ;
        RECT 896.000 102.040 900.000 102.640 ;
    END
  END h_in[138]
  PIN h_in[139]
    DIRECTION INPUT ;
    USE SIGNAL ;
    ANTENNAGATEAREA 0.647700 ;
    ANTENNADIFFAREA 0.434700 ;
    PORT
      LAYER met3 ;
        RECT 896.000 85.040 900.000 85.640 ;
    END
  END h_in[139]
  PIN h_in[13]
    DIRECTION INPUT ;
    USE SIGNAL ;
    ANTENNAGATEAREA 0.631200 ;
    ANTENNADIFFAREA 0.434700 ;
    PORT
      LAYER met3 ;
        RECT 896.000 418.240 900.000 418.840 ;
    END
  END h_in[13]
  PIN h_in[140]
    DIRECTION INPUT ;
    USE SIGNAL ;
    ANTENNAGATEAREA 0.631200 ;
    ANTENNADIFFAREA 0.434700 ;
    PORT
      LAYER met3 ;
        RECT 896.000 448.840 900.000 449.440 ;
    END
  END h_in[140]
  PIN h_in[141]
    DIRECTION INPUT ;
    USE SIGNAL ;
    ANTENNAGATEAREA 0.631200 ;
    ANTENNADIFFAREA 0.434700 ;
    PORT
      LAYER met3 ;
        RECT 896.000 510.040 900.000 510.640 ;
    END
  END h_in[141]
  PIN h_in[142]
    DIRECTION INPUT ;
    USE SIGNAL ;
    ANTENNAGATEAREA 0.631200 ;
    ANTENNADIFFAREA 0.434700 ;
    PORT
      LAYER met3 ;
        RECT 896.000 544.040 900.000 544.640 ;
    END
  END h_in[142]
  PIN h_in[143]
    DIRECTION INPUT ;
    USE SIGNAL ;
    ANTENNAGATEAREA 0.631200 ;
    ANTENNADIFFAREA 0.434700 ;
    PORT
      LAYER met3 ;
        RECT 896.000 459.040 900.000 459.640 ;
    END
  END h_in[143]
  PIN h_in[144]
    DIRECTION INPUT ;
    USE SIGNAL ;
    ANTENNAGATEAREA 0.631200 ;
    ANTENNADIFFAREA 0.434700 ;
    PORT
      LAYER met3 ;
        RECT 896.000 625.640 900.000 626.240 ;
    END
  END h_in[144]
  PIN h_in[145]
    DIRECTION INPUT ;
    USE SIGNAL ;
    ANTENNAGATEAREA 0.631200 ;
    ANTENNADIFFAREA 0.434700 ;
    PORT
      LAYER met3 ;
        RECT 896.000 527.040 900.000 527.640 ;
    END
  END h_in[145]
  PIN h_in[146]
    DIRECTION INPUT ;
    USE SIGNAL ;
    ANTENNAGATEAREA 0.631200 ;
    ANTENNADIFFAREA 0.434700 ;
    PORT
      LAYER met3 ;
        RECT 896.000 564.440 900.000 565.040 ;
    END
  END h_in[146]
  PIN h_in[147]
    DIRECTION INPUT ;
    USE SIGNAL ;
    ANTENNAGATEAREA 0.631200 ;
    ANTENNADIFFAREA 0.434700 ;
    PORT
      LAYER met3 ;
        RECT 896.000 584.840 900.000 585.440 ;
    END
  END h_in[147]
  PIN h_in[148]
    DIRECTION INPUT ;
    USE SIGNAL ;
    ANTENNAGATEAREA 0.560700 ;
    ANTENNADIFFAREA 0.434700 ;
    PORT
      LAYER met3 ;
        RECT 896.000 741.240 900.000 741.840 ;
    END
  END h_in[148]
  PIN h_in[149]
    DIRECTION INPUT ;
    USE SIGNAL ;
    ANTENNAGATEAREA 0.631200 ;
    ANTENNADIFFAREA 0.434700 ;
    PORT
      LAYER met3 ;
        RECT 896.000 710.640 900.000 711.240 ;
    END
  END h_in[149]
  PIN h_in[14]
    DIRECTION INPUT ;
    USE SIGNAL ;
    ANTENNAGATEAREA 0.631200 ;
    ANTENNADIFFAREA 0.434700 ;
    PORT
      LAYER met3 ;
        RECT 896.000 431.840 900.000 432.440 ;
    END
  END h_in[14]
  PIN h_in[150]
    DIRECTION INPUT ;
    USE SIGNAL ;
    ANTENNAGATEAREA 0.593700 ;
    ANTENNADIFFAREA 0.434700 ;
    PORT
      LAYER met2 ;
        RECT 682.730 896.000 683.010 900.000 ;
    END
  END h_in[150]
  PIN h_in[151]
    DIRECTION INPUT ;
    USE SIGNAL ;
    ANTENNAGATEAREA 0.631200 ;
    ANTENNADIFFAREA 0.434700 ;
    PORT
      LAYER met3 ;
        RECT 896.000 690.240 900.000 690.840 ;
    END
  END h_in[151]
  PIN h_in[152]
    DIRECTION INPUT ;
    USE SIGNAL ;
    ANTENNAGATEAREA 0.593700 ;
    ANTENNADIFFAREA 0.434700 ;
    PORT
      LAYER met2 ;
        RECT 579.690 896.000 579.970 900.000 ;
    END
  END h_in[152]
  PIN h_in[153]
    DIRECTION INPUT ;
    USE SIGNAL ;
    ANTENNAGATEAREA 0.560700 ;
    ANTENNADIFFAREA 0.434700 ;
    PORT
      LAYER met2 ;
        RECT 740.690 896.000 740.970 900.000 ;
    END
  END h_in[153]
  PIN h_in[154]
    DIRECTION INPUT ;
    USE SIGNAL ;
    ANTENNAGATEAREA 0.593700 ;
    ANTENNADIFFAREA 0.434700 ;
    PORT
      LAYER met2 ;
        RECT 570.030 896.000 570.310 900.000 ;
    END
  END h_in[154]
  PIN h_in[155]
    DIRECTION INPUT ;
    USE SIGNAL ;
    ANTENNAGATEAREA 0.593700 ;
    ANTENNADIFFAREA 0.434700 ;
    PORT
      LAYER met2 ;
        RECT 557.150 896.000 557.430 900.000 ;
    END
  END h_in[155]
  PIN h_in[156]
    DIRECTION INPUT ;
    USE SIGNAL ;
    ANTENNAGATEAREA 0.631200 ;
    ANTENNADIFFAREA 0.434700 ;
    PORT
      LAYER met2 ;
        RECT 595.790 896.000 596.070 900.000 ;
    END
  END h_in[156]
  PIN h_in[157]
    DIRECTION INPUT ;
    USE SIGNAL ;
    ANTENNAGATEAREA 0.631200 ;
    ANTENNADIFFAREA 0.434700 ;
    PORT
      LAYER met2 ;
        RECT 586.130 896.000 586.410 900.000 ;
    END
  END h_in[157]
  PIN h_in[158]
    DIRECTION INPUT ;
    USE SIGNAL ;
    ANTENNAGATEAREA 0.631200 ;
    ANTENNADIFFAREA 0.434700 ;
    PORT
      LAYER met2 ;
        RECT 750.350 896.000 750.630 900.000 ;
    END
  END h_in[158]
  PIN h_in[159]
    DIRECTION INPUT ;
    USE SIGNAL ;
    ANTENNAGATEAREA 0.560700 ;
    ANTENNADIFFAREA 0.434700 ;
    PORT
      LAYER met2 ;
        RECT 550.710 896.000 550.990 900.000 ;
    END
  END h_in[159]
  PIN h_in[15]
    DIRECTION INPUT ;
    USE SIGNAL ;
    ANTENNAGATEAREA 0.631200 ;
    ANTENNADIFFAREA 0.434700 ;
    PORT
      LAYER met3 ;
        RECT 896.000 465.840 900.000 466.440 ;
    END
  END h_in[15]
  PIN h_in[160]
    DIRECTION INPUT ;
    USE SIGNAL ;
    ANTENNAGATEAREA 0.631200 ;
    ANTENNADIFFAREA 0.434700 ;
    PORT
      LAYER met2 ;
        RECT 805.090 0.000 805.370 4.000 ;
    END
  END h_in[160]
  PIN h_in[161]
    DIRECTION INPUT ;
    USE SIGNAL ;
    ANTENNAGATEAREA 0.631200 ;
    ANTENNADIFFAREA 0.434700 ;
    PORT
      LAYER met2 ;
        RECT 756.790 0.000 757.070 4.000 ;
    END
  END h_in[161]
  PIN h_in[162]
    DIRECTION INPUT ;
    USE SIGNAL ;
    ANTENNAGATEAREA 0.631200 ;
    ANTENNADIFFAREA 0.434700 ;
    PORT
      LAYER met2 ;
        RECT 776.110 0.000 776.390 4.000 ;
    END
  END h_in[162]
  PIN h_in[163]
    DIRECTION INPUT ;
    USE SIGNAL ;
    ANTENNAGATEAREA 0.631200 ;
    ANTENNADIFFAREA 0.434700 ;
    PORT
      LAYER met2 ;
        RECT 769.670 0.000 769.950 4.000 ;
    END
  END h_in[163]
  PIN h_in[164]
    DIRECTION INPUT ;
    USE SIGNAL ;
    ANTENNAGATEAREA 0.647700 ;
    ANTENNADIFFAREA 0.434700 ;
    PORT
      LAYER met2 ;
        RECT 698.830 0.000 699.110 4.000 ;
    END
  END h_in[164]
  PIN h_in[165]
    DIRECTION INPUT ;
    USE SIGNAL ;
    ANTENNAGATEAREA 0.631200 ;
    ANTENNADIFFAREA 0.434700 ;
    PORT
      LAYER met2 ;
        RECT 821.190 0.000 821.470 4.000 ;
    END
  END h_in[165]
  PIN h_in[166]
    DIRECTION INPUT ;
    USE SIGNAL ;
    ANTENNAGATEAREA 0.647700 ;
    ANTENNADIFFAREA 0.434700 ;
    PORT
      LAYER met2 ;
        RECT 743.910 0.000 744.190 4.000 ;
    END
  END h_in[166]
  PIN h_in[167]
    DIRECTION INPUT ;
    USE SIGNAL ;
    ANTENNAGATEAREA 0.631200 ;
    ANTENNADIFFAREA 0.434700 ;
    PORT
      LAYER met3 ;
        RECT 896.000 231.240 900.000 231.840 ;
    END
  END h_in[167]
  PIN h_in[168]
    DIRECTION INPUT ;
    USE SIGNAL ;
    ANTENNAGATEAREA 0.631200 ;
    ANTENNADIFFAREA 0.434700 ;
    PORT
      LAYER met3 ;
        RECT 896.000 190.440 900.000 191.040 ;
    END
  END h_in[168]
  PIN h_in[169]
    DIRECTION INPUT ;
    USE SIGNAL ;
    ANTENNAGATEAREA 0.631200 ;
    ANTENNADIFFAREA 0.434700 ;
    PORT
      LAYER met3 ;
        RECT 896.000 149.640 900.000 150.240 ;
    END
  END h_in[169]
  PIN h_in[16]
    DIRECTION INPUT ;
    USE SIGNAL ;
    ANTENNAGATEAREA 0.631200 ;
    ANTENNADIFFAREA 0.434700 ;
    PORT
      LAYER met2 ;
        RECT 553.930 896.000 554.210 900.000 ;
    END
  END h_in[16]
  PIN h_in[170]
    DIRECTION INPUT ;
    USE SIGNAL ;
    ANTENNAGATEAREA 0.631200 ;
    ANTENNADIFFAREA 0.434700 ;
    PORT
      LAYER met3 ;
        RECT 896.000 312.840 900.000 313.440 ;
    END
  END h_in[170]
  PIN h_in[171]
    DIRECTION INPUT ;
    USE SIGNAL ;
    ANTENNAGATEAREA 0.647700 ;
    ANTENNADIFFAREA 0.434700 ;
    PORT
      LAYER met3 ;
        RECT 896.000 95.240 900.000 95.840 ;
    END
  END h_in[171]
  PIN h_in[172]
    DIRECTION INPUT ;
    USE SIGNAL ;
    ANTENNAGATEAREA 0.631200 ;
    ANTENNADIFFAREA 0.434700 ;
    PORT
      LAYER met3 ;
        RECT 896.000 367.240 900.000 367.840 ;
    END
  END h_in[172]
  PIN h_in[173]
    DIRECTION INPUT ;
    USE SIGNAL ;
    ANTENNAGATEAREA 0.631200 ;
    ANTENNADIFFAREA 0.434700 ;
    PORT
      LAYER met3 ;
        RECT 896.000 397.840 900.000 398.440 ;
    END
  END h_in[173]
  PIN h_in[174]
    DIRECTION INPUT ;
    USE SIGNAL ;
    ANTENNAGATEAREA 0.631200 ;
    ANTENNADIFFAREA 0.434700 ;
    PORT
      LAYER met3 ;
        RECT 896.000 445.440 900.000 446.040 ;
    END
  END h_in[174]
  PIN h_in[175]
    DIRECTION INPUT ;
    USE SIGNAL ;
    ANTENNAGATEAREA 0.647700 ;
    ANTENNADIFFAREA 0.434700 ;
    PORT
      LAYER met3 ;
        RECT 896.000 622.240 900.000 622.840 ;
    END
  END h_in[175]
  PIN h_in[176]
    DIRECTION INPUT ;
    USE SIGNAL ;
    ANTENNAGATEAREA 0.631200 ;
    ANTENNADIFFAREA 0.434700 ;
    PORT
      LAYER met3 ;
        RECT 896.000 479.440 900.000 480.040 ;
    END
  END h_in[176]
  PIN h_in[177]
    DIRECTION INPUT ;
    USE SIGNAL ;
    ANTENNAGATEAREA 0.631200 ;
    ANTENNADIFFAREA 0.434700 ;
    PORT
      LAYER met3 ;
        RECT 896.000 523.640 900.000 524.240 ;
    END
  END h_in[177]
  PIN h_in[178]
    DIRECTION INPUT ;
    USE SIGNAL ;
    ANTENNAGATEAREA 0.631200 ;
    ANTENNADIFFAREA 0.434700 ;
    PORT
      LAYER met3 ;
        RECT 896.000 520.240 900.000 520.840 ;
    END
  END h_in[178]
  PIN h_in[179]
    DIRECTION INPUT ;
    USE SIGNAL ;
    ANTENNAGATEAREA 0.631200 ;
    ANTENNADIFFAREA 0.434700 ;
    PORT
      LAYER met3 ;
        RECT 896.000 530.440 900.000 531.040 ;
    END
  END h_in[179]
  PIN h_in[17]
    DIRECTION INPUT ;
    USE SIGNAL ;
    ANTENNAGATEAREA 0.631200 ;
    ANTENNADIFFAREA 0.434700 ;
    PORT
      LAYER met2 ;
        RECT 760.010 896.000 760.290 900.000 ;
    END
  END h_in[17]
  PIN h_in[180]
    DIRECTION INPUT ;
    USE SIGNAL ;
    ANTENNAGATEAREA 0.631200 ;
    ANTENNADIFFAREA 0.434700 ;
    PORT
      LAYER met3 ;
        RECT 896.000 618.840 900.000 619.440 ;
    END
  END h_in[180]
  PIN h_in[181]
    DIRECTION INPUT ;
    USE SIGNAL ;
    ANTENNAGATEAREA 0.560700 ;
    ANTENNADIFFAREA 0.434700 ;
    PORT
      LAYER met3 ;
        RECT 896.000 754.840 900.000 755.440 ;
    END
  END h_in[181]
  PIN h_in[182]
    DIRECTION INPUT ;
    USE SIGNAL ;
    ANTENNAGATEAREA 0.631200 ;
    ANTENNADIFFAREA 0.434700 ;
    PORT
      LAYER met3 ;
        RECT 896.000 703.840 900.000 704.440 ;
    END
  END h_in[182]
  PIN h_in[183]
    DIRECTION INPUT ;
    USE SIGNAL ;
    ANTENNAGATEAREA 0.631200 ;
    ANTENNADIFFAREA 0.434700 ;
    PORT
      LAYER met3 ;
        RECT 896.000 717.440 900.000 718.040 ;
    END
  END h_in[183]
  PIN h_in[184]
    DIRECTION INPUT ;
    USE SIGNAL ;
    ANTENNAGATEAREA 0.631200 ;
    ANTENNADIFFAREA 0.434700 ;
    PORT
      LAYER met3 ;
        RECT 896.000 686.840 900.000 687.440 ;
    END
  END h_in[184]
  PIN h_in[185]
    DIRECTION INPUT ;
    USE SIGNAL ;
    ANTENNAGATEAREA 0.631200 ;
    ANTENNADIFFAREA 0.434700 ;
    PORT
      LAYER met3 ;
        RECT 896.000 758.240 900.000 758.840 ;
    END
  END h_in[185]
  PIN h_in[186]
    DIRECTION INPUT ;
    USE SIGNAL ;
    ANTENNAGATEAREA 0.631200 ;
    ANTENNADIFFAREA 0.434700 ;
    PORT
      LAYER met3 ;
        RECT 896.000 765.040 900.000 765.640 ;
    END
  END h_in[186]
  PIN h_in[187]
    DIRECTION INPUT ;
    USE SIGNAL ;
    ANTENNAGATEAREA 0.631200 ;
    ANTENNADIFFAREA 0.434700 ;
    PORT
      LAYER met3 ;
        RECT 896.000 771.840 900.000 772.440 ;
    END
  END h_in[187]
  PIN h_in[188]
    DIRECTION INPUT ;
    USE SIGNAL ;
    ANTENNAGATEAREA 0.631200 ;
    ANTENNADIFFAREA 0.434700 ;
    PORT
      LAYER met2 ;
        RECT 608.670 896.000 608.950 900.000 ;
    END
  END h_in[188]
  PIN h_in[189]
    DIRECTION INPUT ;
    USE SIGNAL ;
    ANTENNAGATEAREA 0.631200 ;
    ANTENNADIFFAREA 0.434700 ;
    PORT
      LAYER met2 ;
        RECT 599.010 896.000 599.290 900.000 ;
    END
  END h_in[189]
  PIN h_in[18]
    DIRECTION INPUT ;
    USE SIGNAL ;
    ANTENNAGATEAREA 0.647700 ;
    ANTENNADIFFAREA 0.434700 ;
    PORT
      LAYER met2 ;
        RECT 489.530 896.000 489.810 900.000 ;
    END
  END h_in[18]
  PIN h_in[190]
    DIRECTION INPUT ;
    USE SIGNAL ;
    ANTENNAGATEAREA 0.631200 ;
    ANTENNADIFFAREA 0.434700 ;
    PORT
      LAYER met2 ;
        RECT 731.030 896.000 731.310 900.000 ;
    END
  END h_in[190]
  PIN h_in[191]
    DIRECTION INPUT ;
    USE SIGNAL ;
    ANTENNAGATEAREA 0.631200 ;
    ANTENNADIFFAREA 0.434700 ;
    PORT
      LAYER met2 ;
        RECT 718.150 896.000 718.430 900.000 ;
    END
  END h_in[191]
  PIN h_in[192]
    DIRECTION INPUT ;
    USE SIGNAL ;
    ANTENNAGATEAREA 0.631200 ;
    ANTENNADIFFAREA 0.434700 ;
    PORT
      LAYER met2 ;
        RECT 834.070 0.000 834.350 4.000 ;
    END
  END h_in[192]
  PIN h_in[193]
    DIRECTION INPUT ;
    USE SIGNAL ;
    ANTENNAGATEAREA 0.631200 ;
    ANTENNADIFFAREA 0.434700 ;
    PORT
      LAYER met2 ;
        RECT 714.930 0.000 715.210 4.000 ;
    END
  END h_in[193]
  PIN h_in[194]
    DIRECTION INPUT ;
    USE SIGNAL ;
    ANTENNAGATEAREA 0.631200 ;
    ANTENNADIFFAREA 0.434700 ;
    PORT
      LAYER met2 ;
        RECT 863.050 0.000 863.330 4.000 ;
    END
  END h_in[194]
  PIN h_in[195]
    DIRECTION INPUT ;
    USE SIGNAL ;
    ANTENNAGATEAREA 0.631200 ;
    ANTENNADIFFAREA 0.434700 ;
    PORT
      LAYER met2 ;
        RECT 827.630 0.000 827.910 4.000 ;
    END
  END h_in[195]
  PIN h_in[196]
    DIRECTION INPUT ;
    USE SIGNAL ;
    ANTENNAGATEAREA 0.631200 ;
    ANTENNADIFFAREA 0.434700 ;
    PORT
      LAYER met2 ;
        RECT 785.770 0.000 786.050 4.000 ;
    END
  END h_in[196]
  PIN h_in[197]
    DIRECTION INPUT ;
    USE SIGNAL ;
    ANTENNAGATEAREA 0.631200 ;
    ANTENNADIFFAREA 0.434700 ;
    PORT
      LAYER met2 ;
        RECT 779.330 0.000 779.610 4.000 ;
    END
  END h_in[197]
  PIN h_in[198]
    DIRECTION INPUT ;
    USE SIGNAL ;
    ANTENNAGATEAREA 0.560700 ;
    ANTENNADIFFAREA 0.434700 ;
    PORT
      LAYER met2 ;
        RECT 734.250 0.000 734.530 4.000 ;
    END
  END h_in[198]
  PIN h_in[199]
    DIRECTION INPUT ;
    USE SIGNAL ;
    ANTENNAGATEAREA 0.631200 ;
    ANTENNADIFFAREA 0.434700 ;
    PORT
      LAYER met3 ;
        RECT 896.000 234.640 900.000 235.240 ;
    END
  END h_in[199]
  PIN h_in[19]
    DIRECTION INPUT ;
    USE SIGNAL ;
    ANTENNAGATEAREA 0.560700 ;
    ANTENNADIFFAREA 0.434700 ;
    PORT
      LAYER met2 ;
        RECT 499.190 896.000 499.470 900.000 ;
    END
  END h_in[19]
  PIN h_in[1]
    DIRECTION INPUT ;
    USE SIGNAL ;
    ANTENNAGATEAREA 0.631200 ;
    ANTENNADIFFAREA 0.434700 ;
    PORT
      LAYER met2 ;
        RECT 695.610 0.000 695.890 4.000 ;
    END
  END h_in[1]
  PIN h_in[200]
    DIRECTION INPUT ;
    USE SIGNAL ;
    ANTENNAGATEAREA 0.631200 ;
    ANTENNADIFFAREA 0.434700 ;
    PORT
      LAYER met3 ;
        RECT 896.000 261.840 900.000 262.440 ;
    END
  END h_in[200]
  PIN h_in[201]
    DIRECTION INPUT ;
    USE SIGNAL ;
    ANTENNAGATEAREA 0.631200 ;
    ANTENNADIFFAREA 0.434700 ;
    PORT
      LAYER met3 ;
        RECT 896.000 159.840 900.000 160.440 ;
    END
  END h_in[201]
  PIN h_in[202]
    DIRECTION INPUT ;
    USE SIGNAL ;
    ANTENNAGATEAREA 0.647700 ;
    ANTENNADIFFAREA 0.434700 ;
    PORT
      LAYER met3 ;
        RECT 896.000 115.640 900.000 116.240 ;
    END
  END h_in[202]
  PIN h_in[203]
    DIRECTION INPUT ;
    USE SIGNAL ;
    ANTENNAGATEAREA 0.631200 ;
    ANTENNADIFFAREA 0.434700 ;
    PORT
      LAYER met3 ;
        RECT 896.000 333.240 900.000 333.840 ;
    END
  END h_in[203]
  PIN h_in[204]
    DIRECTION INPUT ;
    USE SIGNAL ;
    ANTENNAGATEAREA 0.631200 ;
    ANTENNADIFFAREA 0.434700 ;
    PORT
      LAYER met3 ;
        RECT 896.000 357.040 900.000 357.640 ;
    END
  END h_in[204]
  PIN h_in[205]
    DIRECTION INPUT ;
    USE SIGNAL ;
    ANTENNAGATEAREA 0.631200 ;
    ANTENNADIFFAREA 0.434700 ;
    PORT
      LAYER met3 ;
        RECT 896.000 384.240 900.000 384.840 ;
    END
  END h_in[205]
  PIN h_in[206]
    DIRECTION INPUT ;
    USE SIGNAL ;
    ANTENNAGATEAREA 0.631200 ;
    ANTENNADIFFAREA 0.434700 ;
    PORT
      LAYER met3 ;
        RECT 896.000 411.440 900.000 412.040 ;
    END
  END h_in[206]
  PIN h_in[207]
    DIRECTION INPUT ;
    USE SIGNAL ;
    ANTENNAGATEAREA 0.647700 ;
    ANTENNADIFFAREA 0.434700 ;
    PORT
      LAYER met3 ;
        RECT 896.000 649.440 900.000 650.040 ;
    END
  END h_in[207]
  PIN h_in[208]
    DIRECTION INPUT ;
    USE SIGNAL ;
    ANTENNAGATEAREA 0.631200 ;
    ANTENNADIFFAREA 0.434700 ;
    PORT
      LAYER met3 ;
        RECT 896.000 659.640 900.000 660.240 ;
    END
  END h_in[208]
  PIN h_in[209]
    DIRECTION INPUT ;
    USE SIGNAL ;
    ANTENNAGATEAREA 0.631200 ;
    ANTENNADIFFAREA 0.434700 ;
    PORT
      LAYER met3 ;
        RECT 896.000 547.440 900.000 548.040 ;
    END
  END h_in[209]
  PIN h_in[20]
    DIRECTION INPUT ;
    USE SIGNAL ;
    ANTENNAGATEAREA 0.631200 ;
    ANTENNADIFFAREA 0.434700 ;
    PORT
      LAYER met2 ;
        RECT 566.810 896.000 567.090 900.000 ;
    END
  END h_in[20]
  PIN h_in[210]
    DIRECTION INPUT ;
    USE SIGNAL ;
    ANTENNAGATEAREA 0.631200 ;
    ANTENNADIFFAREA 0.434700 ;
    PORT
      LAYER met3 ;
        RECT 896.000 615.440 900.000 616.040 ;
    END
  END h_in[210]
  PIN h_in[211]
    DIRECTION INPUT ;
    USE SIGNAL ;
    ANTENNAGATEAREA 0.631200 ;
    ANTENNADIFFAREA 0.434700 ;
    PORT
      LAYER met3 ;
        RECT 896.000 591.640 900.000 592.240 ;
    END
  END h_in[211]
  PIN h_in[212]
    DIRECTION INPUT ;
    USE SIGNAL ;
    ANTENNAGATEAREA 0.631200 ;
    ANTENNADIFFAREA 0.434700 ;
    PORT
      LAYER met3 ;
        RECT 896.000 550.840 900.000 551.440 ;
    END
  END h_in[212]
  PIN h_in[213]
    DIRECTION INPUT ;
    USE SIGNAL ;
    ANTENNAGATEAREA 0.631200 ;
    ANTENNADIFFAREA 0.434700 ;
    PORT
      LAYER met3 ;
        RECT 896.000 612.040 900.000 612.640 ;
    END
  END h_in[213]
  PIN h_in[214]
    DIRECTION INPUT ;
    USE SIGNAL ;
    ANTENNAGATEAREA 0.560700 ;
    ANTENNADIFFAREA 0.434700 ;
    PORT
      LAYER met3 ;
        RECT 896.000 761.640 900.000 762.240 ;
    END
  END h_in[214]
  PIN h_in[215]
    DIRECTION INPUT ;
    USE SIGNAL ;
    ANTENNAGATEAREA 0.631200 ;
    ANTENNADIFFAREA 0.434700 ;
    PORT
      LAYER met3 ;
        RECT 896.000 680.040 900.000 680.640 ;
    END
  END h_in[215]
  PIN h_in[216]
    DIRECTION INPUT ;
    USE SIGNAL ;
    ANTENNAGATEAREA 0.647700 ;
    ANTENNADIFFAREA 0.434700 ;
    PORT
      LAYER met2 ;
        RECT 685.950 896.000 686.230 900.000 ;
    END
  END h_in[216]
  PIN h_in[217]
    DIRECTION INPUT ;
    USE SIGNAL ;
    ANTENNAGATEAREA 0.647700 ;
    ANTENNADIFFAREA 0.434700 ;
    PORT
      LAYER met2 ;
        RECT 708.490 896.000 708.770 900.000 ;
    END
  END h_in[217]
  PIN h_in[218]
    DIRECTION INPUT ;
    USE SIGNAL ;
    ANTENNAGATEAREA 0.647700 ;
    ANTENNADIFFAREA 0.434700 ;
    PORT
      LAYER met2 ;
        RECT 702.050 896.000 702.330 900.000 ;
    END
  END h_in[218]
  PIN h_in[219]
    DIRECTION INPUT ;
    USE SIGNAL ;
    ANTENNAGATEAREA 0.647700 ;
    ANTENNADIFFAREA 0.434700 ;
    PORT
      LAYER met2 ;
        RECT 676.290 896.000 676.570 900.000 ;
    END
  END h_in[219]
  PIN h_in[21]
    DIRECTION INPUT ;
    USE SIGNAL ;
    ANTENNAGATEAREA 0.631200 ;
    ANTENNADIFFAREA 0.434700 ;
    PORT
      LAYER met2 ;
        RECT 544.270 896.000 544.550 900.000 ;
    END
  END h_in[21]
  PIN h_in[220]
    DIRECTION INPUT ;
    USE SIGNAL ;
    ANTENNAGATEAREA 0.631200 ;
    ANTENNADIFFAREA 0.434700 ;
    PORT
      LAYER met2 ;
        RECT 711.710 896.000 711.990 900.000 ;
    END
  END h_in[220]
  PIN h_in[221]
    DIRECTION INPUT ;
    USE SIGNAL ;
    ANTENNAGATEAREA 0.631200 ;
    ANTENNADIFFAREA 0.434700 ;
    PORT
      LAYER met2 ;
        RECT 698.830 896.000 699.110 900.000 ;
    END
  END h_in[221]
  PIN h_in[222]
    DIRECTION INPUT ;
    USE SIGNAL ;
    ANTENNAGATEAREA 0.560700 ;
    ANTENNADIFFAREA 0.434700 ;
    PORT
      LAYER met2 ;
        RECT 660.190 896.000 660.470 900.000 ;
    END
  END h_in[222]
  PIN h_in[223]
    DIRECTION INPUT ;
    USE SIGNAL ;
    ANTENNAGATEAREA 0.631200 ;
    ANTENNADIFFAREA 0.434700 ;
    PORT
      LAYER met2 ;
        RECT 663.410 896.000 663.690 900.000 ;
    END
  END h_in[223]
  PIN h_in[224]
    DIRECTION INPUT ;
    USE SIGNAL ;
    ANTENNAGATEAREA 0.631200 ;
    ANTENNADIFFAREA 0.434700 ;
    PORT
      LAYER met2 ;
        RECT 811.530 0.000 811.810 4.000 ;
    END
  END h_in[224]
  PIN h_in[225]
    DIRECTION INPUT ;
    USE SIGNAL ;
    ANTENNAGATEAREA 0.631200 ;
    ANTENNADIFFAREA 0.434700 ;
    PORT
      LAYER met2 ;
        RECT 808.310 0.000 808.590 4.000 ;
    END
  END h_in[225]
  PIN h_in[226]
    DIRECTION INPUT ;
    USE SIGNAL ;
    ANTENNAGATEAREA 0.631200 ;
    ANTENNADIFFAREA 0.434700 ;
    PORT
      LAYER met2 ;
        RECT 760.010 0.000 760.290 4.000 ;
    END
  END h_in[226]
  PIN h_in[227]
    DIRECTION INPUT ;
    USE SIGNAL ;
    ANTENNAGATEAREA 0.647700 ;
    ANTENNADIFFAREA 0.434700 ;
    PORT
      LAYER met2 ;
        RECT 859.830 0.000 860.110 4.000 ;
    END
  END h_in[227]
  PIN h_in[228]
    DIRECTION INPUT ;
    USE SIGNAL ;
    ANTENNAGATEAREA 0.631200 ;
    ANTENNADIFFAREA 0.434700 ;
    PORT
      LAYER met2 ;
        RECT 747.130 0.000 747.410 4.000 ;
    END
  END h_in[228]
  PIN h_in[229]
    DIRECTION INPUT ;
    USE SIGNAL ;
    ANTENNAGATEAREA 0.593700 ;
    ANTENNADIFFAREA 0.434700 ;
    PORT
      LAYER met2 ;
        RECT 875.930 0.000 876.210 4.000 ;
    END
  END h_in[229]
  PIN h_in[22]
    DIRECTION INPUT ;
    USE SIGNAL ;
    ANTENNAGATEAREA 0.631200 ;
    ANTENNADIFFAREA 0.434700 ;
    PORT
      LAYER met2 ;
        RECT 547.490 896.000 547.770 900.000 ;
    END
  END h_in[22]
  PIN h_in[230]
    DIRECTION INPUT ;
    USE SIGNAL ;
    ANTENNAGATEAREA 0.560700 ;
    ANTENNADIFFAREA 0.434700 ;
    PORT
      LAYER met2 ;
        RECT 763.230 0.000 763.510 4.000 ;
    END
  END h_in[230]
  PIN h_in[231]
    DIRECTION INPUT ;
    USE SIGNAL ;
    ANTENNAGATEAREA 0.631200 ;
    ANTENNADIFFAREA 0.434700 ;
    PORT
      LAYER met3 ;
        RECT 896.000 224.440 900.000 225.040 ;
    END
  END h_in[231]
  PIN h_in[232]
    DIRECTION INPUT ;
    USE SIGNAL ;
    ANTENNAGATEAREA 0.631200 ;
    ANTENNADIFFAREA 0.434700 ;
    PORT
      LAYER met3 ;
        RECT 896.000 265.240 900.000 265.840 ;
    END
  END h_in[232]
  PIN h_in[233]
    DIRECTION INPUT ;
    USE SIGNAL ;
    ANTENNAGATEAREA 0.647700 ;
    ANTENNADIFFAREA 0.434700 ;
    PORT
      LAYER met3 ;
        RECT 896.000 163.240 900.000 163.840 ;
    END
  END h_in[233]
  PIN h_in[234]
    DIRECTION INPUT ;
    USE SIGNAL ;
    ANTENNAGATEAREA 0.647700 ;
    ANTENNADIFFAREA 0.434700 ;
    PORT
      LAYER met3 ;
        RECT 896.000 119.040 900.000 119.640 ;
    END
  END h_in[234]
  PIN h_in[235]
    DIRECTION INPUT ;
    USE SIGNAL ;
    ANTENNAGATEAREA 0.647700 ;
    ANTENNADIFFAREA 0.434700 ;
    PORT
      LAYER met3 ;
        RECT 896.000 108.840 900.000 109.440 ;
    END
  END h_in[235]
  PIN h_in[236]
    DIRECTION INPUT ;
    USE SIGNAL ;
    ANTENNAGATEAREA 0.593700 ;
    ANTENNADIFFAREA 0.434700 ;
    PORT
      LAYER met3 ;
        RECT 896.000 88.440 900.000 89.040 ;
    END
  END h_in[236]
  PIN h_in[237]
    DIRECTION INPUT ;
    USE SIGNAL ;
    ANTENNAGATEAREA 0.631200 ;
    ANTENNADIFFAREA 0.434700 ;
    PORT
      LAYER met3 ;
        RECT 896.000 363.840 900.000 364.440 ;
    END
  END h_in[237]
  PIN h_in[238]
    DIRECTION INPUT ;
    USE SIGNAL ;
    ANTENNAGATEAREA 0.631200 ;
    ANTENNADIFFAREA 0.434700 ;
    PORT
      LAYER met3 ;
        RECT 896.000 391.040 900.000 391.640 ;
    END
  END h_in[238]
  PIN h_in[239]
    DIRECTION INPUT ;
    USE SIGNAL ;
    ANTENNAGATEAREA 0.560700 ;
    ANTENNADIFFAREA 0.434700 ;
    PORT
      LAYER met3 ;
        RECT 896.000 438.640 900.000 439.240 ;
    END
  END h_in[239]
  PIN h_in[23]
    DIRECTION INPUT ;
    USE SIGNAL ;
    ANTENNAGATEAREA 0.631200 ;
    ANTENNADIFFAREA 0.434700 ;
    PORT
      LAYER met2 ;
        RECT 541.050 896.000 541.330 900.000 ;
    END
  END h_in[23]
  PIN h_in[240]
    DIRECTION INPUT ;
    USE SIGNAL ;
    ANTENNAGATEAREA 0.647700 ;
    ANTENNADIFFAREA 0.434700 ;
    PORT
      LAYER met3 ;
        RECT 896.000 442.040 900.000 442.640 ;
    END
  END h_in[240]
  PIN h_in[241]
    DIRECTION INPUT ;
    USE SIGNAL ;
    ANTENNAGATEAREA 0.647700 ;
    ANTENNADIFFAREA 0.434700 ;
    PORT
      LAYER met3 ;
        RECT 896.000 629.040 900.000 629.640 ;
    END
  END h_in[241]
  PIN h_in[242]
    DIRECTION INPUT ;
    USE SIGNAL ;
    ANTENNAGATEAREA 0.647700 ;
    ANTENNADIFFAREA 0.434700 ;
    PORT
      LAYER met3 ;
        RECT 896.000 482.840 900.000 483.440 ;
    END
  END h_in[242]
  PIN h_in[243]
    DIRECTION INPUT ;
    USE SIGNAL ;
    ANTENNAGATEAREA 0.631200 ;
    ANTENNADIFFAREA 0.434700 ;
    PORT
      LAYER met3 ;
        RECT 896.000 489.640 900.000 490.240 ;
    END
  END h_in[243]
  PIN h_in[244]
    DIRECTION INPUT ;
    USE SIGNAL ;
    ANTENNAGATEAREA 0.647700 ;
    ANTENNADIFFAREA 0.434700 ;
    PORT
      LAYER met3 ;
        RECT 896.000 533.840 900.000 534.440 ;
    END
  END h_in[244]
  PIN h_in[245]
    DIRECTION INPUT ;
    USE SIGNAL ;
    ANTENNAGATEAREA 0.593700 ;
    ANTENNADIFFAREA 0.434700 ;
    PORT
      LAYER met2 ;
        RECT 695.610 896.000 695.890 900.000 ;
    END
  END h_in[245]
  PIN h_in[246]
    DIRECTION INPUT ;
    USE SIGNAL ;
    ANTENNAGATEAREA 0.593700 ;
    ANTENNADIFFAREA 0.434700 ;
    PORT
      LAYER met2 ;
        RECT 653.750 896.000 654.030 900.000 ;
    END
  END h_in[246]
  PIN h_in[247]
    DIRECTION INPUT ;
    USE SIGNAL ;
    ANTENNAGATEAREA 0.593700 ;
    ANTENNADIFFAREA 0.434700 ;
    PORT
      LAYER met2 ;
        RECT 647.310 896.000 647.590 900.000 ;
    END
  END h_in[247]
  PIN h_in[248]
    DIRECTION INPUT ;
    USE SIGNAL ;
    ANTENNAGATEAREA 0.647700 ;
    ANTENNADIFFAREA 0.434700 ;
    PORT
      LAYER met2 ;
        RECT 627.990 896.000 628.270 900.000 ;
    END
  END h_in[248]
  PIN h_in[249]
    DIRECTION INPUT ;
    USE SIGNAL ;
    ANTENNAGATEAREA 0.647700 ;
    ANTENNADIFFAREA 0.434700 ;
    PORT
      LAYER met2 ;
        RECT 734.250 896.000 734.530 900.000 ;
    END
  END h_in[249]
  PIN h_in[24]
    DIRECTION INPUT ;
    USE SIGNAL ;
    ANTENNAGATEAREA 0.631200 ;
    ANTENNADIFFAREA 0.434700 ;
    PORT
      LAYER met2 ;
        RECT 528.170 896.000 528.450 900.000 ;
    END
  END h_in[24]
  PIN h_in[250]
    DIRECTION INPUT ;
    USE SIGNAL ;
    ANTENNAGATEAREA 0.631200 ;
    ANTENNADIFFAREA 0.434700 ;
    PORT
      LAYER met2 ;
        RECT 634.430 896.000 634.710 900.000 ;
    END
  END h_in[250]
  PIN h_in[251]
    DIRECTION INPUT ;
    USE SIGNAL ;
    ANTENNAGATEAREA 0.631200 ;
    ANTENNADIFFAREA 0.434700 ;
    PORT
      LAYER met2 ;
        RECT 644.090 896.000 644.370 900.000 ;
    END
  END h_in[251]
  PIN h_in[252]
    DIRECTION INPUT ;
    USE SIGNAL ;
    ANTENNAGATEAREA 0.560700 ;
    ANTENNADIFFAREA 0.434700 ;
    PORT
      LAYER met2 ;
        RECT 637.650 896.000 637.930 900.000 ;
    END
  END h_in[252]
  PIN h_in[253]
    DIRECTION INPUT ;
    USE SIGNAL ;
    ANTENNAGATEAREA 0.631200 ;
    ANTENNADIFFAREA 0.434700 ;
    PORT
      LAYER met2 ;
        RECT 724.590 896.000 724.870 900.000 ;
    END
  END h_in[253]
  PIN h_in[254]
    DIRECTION INPUT ;
    USE SIGNAL ;
    ANTENNAGATEAREA 0.560700 ;
    ANTENNADIFFAREA 0.434700 ;
    PORT
      LAYER met2 ;
        RECT 631.210 896.000 631.490 900.000 ;
    END
  END h_in[254]
  PIN h_in[255]
    DIRECTION INPUT ;
    USE SIGNAL ;
    ANTENNAGATEAREA 0.631200 ;
    ANTENNADIFFAREA 0.434700 ;
    PORT
      LAYER met2 ;
        RECT 621.550 896.000 621.830 900.000 ;
    END
  END h_in[255]
  PIN h_in[25]
    DIRECTION INPUT ;
    USE SIGNAL ;
    ANTENNAGATEAREA 0.631200 ;
    ANTENNADIFFAREA 0.434700 ;
    PORT
      LAYER met2 ;
        RECT 521.730 896.000 522.010 900.000 ;
    END
  END h_in[25]
  PIN h_in[26]
    DIRECTION INPUT ;
    USE SIGNAL ;
    ANTENNAGATEAREA 0.631200 ;
    ANTENNADIFFAREA 0.434700 ;
    PORT
      LAYER met2 ;
        RECT 495.970 896.000 496.250 900.000 ;
    END
  END h_in[26]
  PIN h_in[27]
    DIRECTION INPUT ;
    USE SIGNAL ;
    ANTENNAGATEAREA 0.631200 ;
    ANTENNADIFFAREA 0.434700 ;
    PORT
      LAYER met2 ;
        RECT 483.090 896.000 483.370 900.000 ;
    END
  END h_in[27]
  PIN h_in[28]
    DIRECTION INPUT ;
    USE SIGNAL ;
    ANTENNAGATEAREA 0.631200 ;
    ANTENNADIFFAREA 0.434700 ;
    PORT
      LAYER met2 ;
        RECT 428.350 896.000 428.630 900.000 ;
    END
  END h_in[28]
  PIN h_in[29]
    DIRECTION INPUT ;
    USE SIGNAL ;
    ANTENNAGATEAREA 0.631200 ;
    ANTENNADIFFAREA 0.434700 ;
    PORT
      LAYER met2 ;
        RECT 399.370 896.000 399.650 900.000 ;
    END
  END h_in[29]
  PIN h_in[2]
    DIRECTION INPUT ;
    USE SIGNAL ;
    ANTENNAGATEAREA 0.631200 ;
    ANTENNADIFFAREA 0.434700 ;
    PORT
      LAYER met2 ;
        RECT 663.410 0.000 663.690 4.000 ;
    END
  END h_in[2]
  PIN h_in[30]
    DIRECTION INPUT ;
    USE SIGNAL ;
    ANTENNAGATEAREA 0.631200 ;
    ANTENNADIFFAREA 0.434700 ;
    PORT
      LAYER met2 ;
        RECT 380.050 896.000 380.330 900.000 ;
    END
  END h_in[30]
  PIN h_in[31]
    DIRECTION INPUT ;
    USE SIGNAL ;
    ANTENNAGATEAREA 0.631200 ;
    ANTENNADIFFAREA 0.434700 ;
    PORT
      LAYER met2 ;
        RECT 351.070 896.000 351.350 900.000 ;
    END
  END h_in[31]
  PIN h_in[32]
    DIRECTION INPUT ;
    USE SIGNAL ;
    ANTENNAGATEAREA 0.631200 ;
    ANTENNADIFFAREA 0.434700 ;
    PORT
      LAYER met2 ;
        RECT 682.730 0.000 683.010 4.000 ;
    END
  END h_in[32]
  PIN h_in[33]
    DIRECTION INPUT ;
    USE SIGNAL ;
    ANTENNAGATEAREA 0.631200 ;
    ANTENNADIFFAREA 0.434700 ;
    PORT
      LAYER met2 ;
        RECT 679.510 0.000 679.790 4.000 ;
    END
  END h_in[33]
  PIN h_in[34]
    DIRECTION INPUT ;
    USE SIGNAL ;
    ANTENNAGATEAREA 0.631200 ;
    ANTENNADIFFAREA 0.434700 ;
    PORT
      LAYER met2 ;
        RECT 650.530 0.000 650.810 4.000 ;
    END
  END h_in[34]
  PIN h_in[35]
    DIRECTION INPUT ;
    USE SIGNAL ;
    ANTENNAGATEAREA 0.631200 ;
    ANTENNADIFFAREA 0.434700 ;
    PORT
      LAYER met2 ;
        RECT 676.290 0.000 676.570 4.000 ;
    END
  END h_in[35]
  PIN h_in[36]
    DIRECTION INPUT ;
    USE SIGNAL ;
    ANTENNAGATEAREA 0.631200 ;
    ANTENNADIFFAREA 0.434700 ;
    PORT
      LAYER met2 ;
        RECT 660.190 0.000 660.470 4.000 ;
    END
  END h_in[36]
  PIN h_in[37]
    DIRECTION INPUT ;
    USE SIGNAL ;
    ANTENNAGATEAREA 0.631200 ;
    ANTENNADIFFAREA 0.434700 ;
    PORT
      LAYER met2 ;
        RECT 647.310 0.000 647.590 4.000 ;
    END
  END h_in[37]
  PIN h_in[38]
    DIRECTION INPUT ;
    USE SIGNAL ;
    ANTENNAGATEAREA 0.593700 ;
    ANTENNADIFFAREA 0.434700 ;
    PORT
      LAYER met3 ;
        RECT 896.000 241.440 900.000 242.040 ;
    END
  END h_in[38]
  PIN h_in[39]
    DIRECTION INPUT ;
    USE SIGNAL ;
    ANTENNAGATEAREA 0.560700 ;
    ANTENNADIFFAREA 0.434700 ;
    PORT
      LAYER met3 ;
        RECT 896.000 210.840 900.000 211.440 ;
    END
  END h_in[39]
  PIN h_in[3]
    DIRECTION INPUT ;
    USE SIGNAL ;
    ANTENNAGATEAREA 0.647700 ;
    ANTENNADIFFAREA 0.434700 ;
    PORT
      LAYER met2 ;
        RECT 869.490 0.000 869.770 4.000 ;
    END
  END h_in[3]
  PIN h_in[40]
    DIRECTION INPUT ;
    USE SIGNAL ;
    ANTENNAGATEAREA 0.631200 ;
    ANTENNADIFFAREA 0.434700 ;
    PORT
      LAYER met3 ;
        RECT 896.000 183.640 900.000 184.240 ;
    END
  END h_in[40]
  PIN h_in[41]
    DIRECTION INPUT ;
    USE SIGNAL ;
    ANTENNAGATEAREA 0.631200 ;
    ANTENNADIFFAREA 0.434700 ;
    PORT
      LAYER met3 ;
        RECT 896.000 292.440 900.000 293.040 ;
    END
  END h_in[41]
  PIN h_in[42]
    DIRECTION INPUT ;
    USE SIGNAL ;
    ANTENNAGATEAREA 0.631200 ;
    ANTENNADIFFAREA 0.434700 ;
    PORT
      LAYER met3 ;
        RECT 896.000 316.240 900.000 316.840 ;
    END
  END h_in[42]
  PIN h_in[43]
    DIRECTION INPUT ;
    USE SIGNAL ;
    ANTENNAGATEAREA 0.631200 ;
    ANTENNADIFFAREA 0.434700 ;
    PORT
      LAYER met3 ;
        RECT 896.000 340.040 900.000 340.640 ;
    END
  END h_in[43]
  PIN h_in[44]
    DIRECTION INPUT ;
    USE SIGNAL ;
    ANTENNAGATEAREA 0.631200 ;
    ANTENNADIFFAREA 0.434700 ;
    PORT
      LAYER met3 ;
        RECT 896.000 377.440 900.000 378.040 ;
    END
  END h_in[44]
  PIN h_in[45]
    DIRECTION INPUT ;
    USE SIGNAL ;
    ANTENNAGATEAREA 0.631200 ;
    ANTENNADIFFAREA 0.434700 ;
    PORT
      LAYER met3 ;
        RECT 896.000 499.840 900.000 500.440 ;
    END
  END h_in[45]
  PIN h_in[46]
    DIRECTION INPUT ;
    USE SIGNAL ;
    ANTENNAGATEAREA 0.631200 ;
    ANTENNADIFFAREA 0.434700 ;
    PORT
      LAYER met3 ;
        RECT 896.000 428.440 900.000 429.040 ;
    END
  END h_in[46]
  PIN h_in[47]
    DIRECTION INPUT ;
    USE SIGNAL ;
    ANTENNAGATEAREA 0.631200 ;
    ANTENNADIFFAREA 0.434700 ;
    PORT
      LAYER met3 ;
        RECT 896.000 472.640 900.000 473.240 ;
    END
  END h_in[47]
  PIN h_in[48]
    DIRECTION INPUT ;
    USE SIGNAL ;
    ANTENNAGATEAREA 0.631200 ;
    ANTENNADIFFAREA 0.434700 ;
    PORT
      LAYER met2 ;
        RECT 782.550 896.000 782.830 900.000 ;
    END
  END h_in[48]
  PIN h_in[49]
    DIRECTION INPUT ;
    USE SIGNAL ;
    ANTENNAGATEAREA 0.631200 ;
    ANTENNADIFFAREA 0.434700 ;
    PORT
      LAYER met2 ;
        RECT 801.870 896.000 802.150 900.000 ;
    END
  END h_in[49]
  PIN h_in[4]
    DIRECTION INPUT ;
    USE SIGNAL ;
    ANTENNAGATEAREA 0.631200 ;
    ANTENNADIFFAREA 0.434700 ;
    PORT
      LAYER met2 ;
        RECT 702.050 0.000 702.330 4.000 ;
    END
  END h_in[4]
  PIN h_in[50]
    DIRECTION INPUT ;
    USE SIGNAL ;
    ANTENNAGATEAREA 0.593700 ;
    ANTENNADIFFAREA 0.434700 ;
    PORT
      LAYER met2 ;
        RECT 425.130 896.000 425.410 900.000 ;
    END
  END h_in[50]
  PIN h_in[51]
    DIRECTION INPUT ;
    USE SIGNAL ;
    ANTENNAGATEAREA 0.631200 ;
    ANTENNADIFFAREA 0.434700 ;
    PORT
      LAYER met2 ;
        RECT 779.330 896.000 779.610 900.000 ;
    END
  END h_in[51]
  PIN h_in[52]
    DIRECTION INPUT ;
    USE SIGNAL ;
    ANTENNAGATEAREA 0.631200 ;
    ANTENNADIFFAREA 0.434700 ;
    PORT
      LAYER met2 ;
        RECT 438.010 896.000 438.290 900.000 ;
    END
  END h_in[52]
  PIN h_in[53]
    DIRECTION INPUT ;
    USE SIGNAL ;
    ANTENNAGATEAREA 0.631200 ;
    ANTENNADIFFAREA 0.434700 ;
    PORT
      LAYER met2 ;
        RECT 457.330 896.000 457.610 900.000 ;
    END
  END h_in[53]
  PIN h_in[54]
    DIRECTION INPUT ;
    USE SIGNAL ;
    ANTENNAGATEAREA 0.631200 ;
    ANTENNADIFFAREA 0.434700 ;
    PORT
      LAYER met2 ;
        RECT 470.210 896.000 470.490 900.000 ;
    END
  END h_in[54]
  PIN h_in[55]
    DIRECTION INPUT ;
    USE SIGNAL ;
    ANTENNAGATEAREA 0.631200 ;
    ANTENNADIFFAREA 0.434700 ;
    PORT
      LAYER met2 ;
        RECT 460.550 896.000 460.830 900.000 ;
    END
  END h_in[55]
  PIN h_in[56]
    DIRECTION INPUT ;
    USE SIGNAL ;
    ANTENNAGATEAREA 0.631200 ;
    ANTENNADIFFAREA 0.434700 ;
    PORT
      LAYER met2 ;
        RECT 515.290 896.000 515.570 900.000 ;
    END
  END h_in[56]
  PIN h_in[57]
    DIRECTION INPUT ;
    USE SIGNAL ;
    ANTENNAGATEAREA 0.631200 ;
    ANTENNADIFFAREA 0.434700 ;
    PORT
      LAYER met2 ;
        RECT 508.850 896.000 509.130 900.000 ;
    END
  END h_in[57]
  PIN h_in[58]
    DIRECTION INPUT ;
    USE SIGNAL ;
    ANTENNAGATEAREA 0.631200 ;
    ANTENNADIFFAREA 0.434700 ;
    PORT
      LAYER met2 ;
        RECT 486.310 896.000 486.590 900.000 ;
    END
  END h_in[58]
  PIN h_in[59]
    DIRECTION INPUT ;
    USE SIGNAL ;
    ANTENNAGATEAREA 0.631200 ;
    ANTENNADIFFAREA 0.434700 ;
    PORT
      LAYER met2 ;
        RECT 476.650 896.000 476.930 900.000 ;
    END
  END h_in[59]
  PIN h_in[5]
    DIRECTION INPUT ;
    USE SIGNAL ;
    ANTENNAGATEAREA 0.631200 ;
    ANTENNADIFFAREA 0.434700 ;
    PORT
      LAYER met2 ;
        RECT 669.850 0.000 670.130 4.000 ;
    END
  END h_in[5]
  PIN h_in[60]
    DIRECTION INPUT ;
    USE SIGNAL ;
    ANTENNAGATEAREA 0.593700 ;
    ANTENNADIFFAREA 0.434700 ;
    PORT
      LAYER met2 ;
        RECT 834.070 896.000 834.350 900.000 ;
    END
  END h_in[60]
  PIN h_in[61]
    DIRECTION INPUT ;
    USE SIGNAL ;
    ANTENNAGATEAREA 0.631200 ;
    ANTENNADIFFAREA 0.434700 ;
    PORT
      LAYER met2 ;
        RECT 409.030 896.000 409.310 900.000 ;
    END
  END h_in[61]
  PIN h_in[62]
    DIRECTION INPUT ;
    USE SIGNAL ;
    ANTENNAGATEAREA 0.631200 ;
    ANTENNADIFFAREA 0.434700 ;
    PORT
      LAYER met2 ;
        RECT 386.490 896.000 386.770 900.000 ;
    END
  END h_in[62]
  PIN h_in[63]
    DIRECTION INPUT ;
    USE SIGNAL ;
    ANTENNAGATEAREA 0.631200 ;
    ANTENNADIFFAREA 0.434700 ;
    PORT
      LAYER met2 ;
        RECT 354.290 896.000 354.570 900.000 ;
    END
  END h_in[63]
  PIN h_in[64]
    DIRECTION INPUT ;
    USE SIGNAL ;
    ANTENNAGATEAREA 0.631200 ;
    ANTENNADIFFAREA 0.434700 ;
    PORT
      LAYER met2 ;
        RECT 705.270 0.000 705.550 4.000 ;
    END
  END h_in[64]
  PIN h_in[65]
    DIRECTION INPUT ;
    USE SIGNAL ;
    ANTENNAGATEAREA 0.647700 ;
    ANTENNADIFFAREA 0.434700 ;
    PORT
      LAYER met2 ;
        RECT 872.710 0.000 872.990 4.000 ;
    END
  END h_in[65]
  PIN h_in[66]
    DIRECTION INPUT ;
    USE SIGNAL ;
    ANTENNAGATEAREA 0.593700 ;
    ANTENNADIFFAREA 0.434700 ;
    PORT
      LAYER met2 ;
        RECT 879.150 0.000 879.430 4.000 ;
    END
  END h_in[66]
  PIN h_in[67]
    DIRECTION INPUT ;
    USE SIGNAL ;
    ANTENNAGATEAREA 0.647700 ;
    ANTENNADIFFAREA 0.434700 ;
    PORT
      LAYER met2 ;
        RECT 895.250 0.000 895.530 4.000 ;
    END
  END h_in[67]
  PIN h_in[68]
    DIRECTION INPUT ;
    USE SIGNAL ;
    ANTENNAGATEAREA 0.560700 ;
    ANTENNADIFFAREA 0.434700 ;
    PORT
      LAYER met2 ;
        RECT 656.970 0.000 657.250 4.000 ;
    END
  END h_in[68]
  PIN h_in[69]
    DIRECTION INPUT ;
    USE SIGNAL ;
    ANTENNAGATEAREA 0.560700 ;
    ANTENNADIFFAREA 0.434700 ;
    PORT
      LAYER met2 ;
        RECT 644.090 0.000 644.370 4.000 ;
    END
  END h_in[69]
  PIN h_in[6]
    DIRECTION INPUT ;
    USE SIGNAL ;
    ANTENNAGATEAREA 0.647700 ;
    ANTENNADIFFAREA 0.434700 ;
    PORT
      LAYER met3 ;
        RECT 896.000 244.840 900.000 245.440 ;
    END
  END h_in[6]
  PIN h_in[70]
    DIRECTION INPUT ;
    USE SIGNAL ;
    ANTENNAGATEAREA 0.593700 ;
    ANTENNADIFFAREA 0.434700 ;
    PORT
      LAYER met3 ;
        RECT 896.000 221.040 900.000 221.640 ;
    END
  END h_in[70]
  PIN h_in[71]
    DIRECTION INPUT ;
    USE SIGNAL ;
    ANTENNAGATEAREA 0.647700 ;
    ANTENNADIFFAREA 0.434700 ;
    PORT
      LAYER met3 ;
        RECT 896.000 200.640 900.000 201.240 ;
    END
  END h_in[71]
  PIN h_in[72]
    DIRECTION INPUT ;
    USE SIGNAL ;
    ANTENNAGATEAREA 0.647700 ;
    ANTENNADIFFAREA 0.434700 ;
    PORT
      LAYER met3 ;
        RECT 896.000 268.640 900.000 269.240 ;
    END
  END h_in[72]
  PIN h_in[73]
    DIRECTION INPUT ;
    USE SIGNAL ;
    ANTENNAGATEAREA 0.647700 ;
    ANTENNADIFFAREA 0.434700 ;
    PORT
      LAYER met3 ;
        RECT 896.000 153.040 900.000 153.640 ;
    END
  END h_in[73]
  PIN h_in[74]
    DIRECTION INPUT ;
    USE SIGNAL ;
    ANTENNAGATEAREA 0.631200 ;
    ANTENNADIFFAREA 0.434700 ;
    PORT
      LAYER met3 ;
        RECT 896.000 289.040 900.000 289.640 ;
    END
  END h_in[74]
  PIN h_in[75]
    DIRECTION INPUT ;
    USE SIGNAL ;
    ANTENNAGATEAREA 0.593700 ;
    ANTENNADIFFAREA 0.434700 ;
    PORT
      LAYER met3 ;
        RECT 896.000 125.840 900.000 126.440 ;
    END
  END h_in[75]
  PIN h_in[76]
    DIRECTION INPUT ;
    USE SIGNAL ;
    ANTENNAGATEAREA 0.560700 ;
    ANTENNADIFFAREA 0.434700 ;
    PORT
      LAYER met3 ;
        RECT 896.000 455.640 900.000 456.240 ;
    END
  END h_in[76]
  PIN h_in[77]
    DIRECTION INPUT ;
    USE SIGNAL ;
    ANTENNAGATEAREA 0.593700 ;
    ANTENNADIFFAREA 0.434700 ;
    PORT
      LAYER met3 ;
        RECT 896.000 673.240 900.000 673.840 ;
    END
  END h_in[77]
  PIN h_in[78]
    DIRECTION INPUT ;
    USE SIGNAL ;
    ANTENNAGATEAREA 0.560700 ;
    ANTENNADIFFAREA 0.434700 ;
    PORT
      LAYER met3 ;
        RECT 896.000 513.440 900.000 514.040 ;
    END
  END h_in[78]
  PIN h_in[79]
    DIRECTION INPUT ;
    USE SIGNAL ;
    ANTENNAGATEAREA 0.631200 ;
    ANTENNADIFFAREA 0.434700 ;
    PORT
      LAYER met3 ;
        RECT 896.000 516.840 900.000 517.440 ;
    END
  END h_in[79]
  PIN h_in[7]
    DIRECTION INPUT ;
    USE SIGNAL ;
    ANTENNAGATEAREA 0.631200 ;
    ANTENNADIFFAREA 0.434700 ;
    PORT
      LAYER met3 ;
        RECT 896.000 255.040 900.000 255.640 ;
    END
  END h_in[7]
  PIN h_in[80]
    DIRECTION INPUT ;
    USE SIGNAL ;
    ANTENNAGATEAREA 0.560700 ;
    ANTENNADIFFAREA 0.434700 ;
    PORT
      LAYER met2 ;
        RECT 843.730 896.000 844.010 900.000 ;
    END
  END h_in[80]
  PIN h_in[81]
    DIRECTION INPUT ;
    USE SIGNAL ;
    ANTENNAGATEAREA 0.647700 ;
    ANTENNADIFFAREA 0.434700 ;
    PORT
      LAYER met2 ;
        RECT 421.910 896.000 422.190 900.000 ;
    END
  END h_in[81]
  PIN h_in[82]
    DIRECTION INPUT ;
    USE SIGNAL ;
    ANTENNAGATEAREA 0.631200 ;
    ANTENNADIFFAREA 0.434700 ;
    PORT
      LAYER met2 ;
        RECT 846.950 896.000 847.230 900.000 ;
    END
  END h_in[82]
  PIN h_in[83]
    DIRECTION INPUT ;
    USE SIGNAL ;
    ANTENNAGATEAREA 0.647700 ;
    ANTENNADIFFAREA 0.434700 ;
    PORT
      LAYER met2 ;
        RECT 405.810 896.000 406.090 900.000 ;
    END
  END h_in[83]
  PIN h_in[84]
    DIRECTION INPUT ;
    USE SIGNAL ;
    ANTENNAGATEAREA 0.647700 ;
    ANTENNADIFFAREA 0.434700 ;
    PORT
      LAYER met2 ;
        RECT 412.250 896.000 412.530 900.000 ;
    END
  END h_in[84]
  PIN h_in[85]
    DIRECTION INPUT ;
    USE SIGNAL ;
    ANTENNAGATEAREA 0.593700 ;
    ANTENNADIFFAREA 0.434700 ;
    PORT
      LAYER met2 ;
        RECT 837.290 896.000 837.570 900.000 ;
    END
  END h_in[85]
  PIN h_in[86]
    DIRECTION INPUT ;
    USE SIGNAL ;
    ANTENNAGATEAREA 0.593700 ;
    ANTENNADIFFAREA 0.434700 ;
    PORT
      LAYER met2 ;
        RECT 293.110 896.000 293.390 900.000 ;
    END
  END h_in[86]
  PIN h_in[87]
    DIRECTION INPUT ;
    USE SIGNAL ;
    ANTENNAGATEAREA 0.647700 ;
    ANTENNADIFFAREA 0.434700 ;
    PORT
      LAYER met2 ;
        RECT 402.590 896.000 402.870 900.000 ;
    END
  END h_in[87]
  PIN h_in[88]
    DIRECTION INPUT ;
    USE SIGNAL ;
    ANTENNAGATEAREA 0.560700 ;
    ANTENNADIFFAREA 0.434700 ;
    PORT
      LAYER met2 ;
        RECT 444.450 896.000 444.730 900.000 ;
    END
  END h_in[88]
  PIN h_in[89]
    DIRECTION INPUT ;
    USE SIGNAL ;
    ANTENNAGATEAREA 0.560700 ;
    ANTENNADIFFAREA 0.434700 ;
    PORT
      LAYER met2 ;
        RECT 454.110 896.000 454.390 900.000 ;
    END
  END h_in[89]
  PIN h_in[8]
    DIRECTION INPUT ;
    USE SIGNAL ;
    ANTENNAGATEAREA 0.631200 ;
    ANTENNADIFFAREA 0.434700 ;
    PORT
      LAYER met3 ;
        RECT 896.000 278.840 900.000 279.440 ;
    END
  END h_in[8]
  PIN h_in[90]
    DIRECTION INPUT ;
    USE SIGNAL ;
    ANTENNAGATEAREA 0.631200 ;
    ANTENNADIFFAREA 0.434700 ;
    PORT
      LAYER met2 ;
        RECT 473.430 896.000 473.710 900.000 ;
    END
  END h_in[90]
  PIN h_in[91]
    DIRECTION INPUT ;
    USE SIGNAL ;
    ANTENNAGATEAREA 0.631200 ;
    ANTENNADIFFAREA 0.434700 ;
    PORT
      LAYER met2 ;
        RECT 463.770 896.000 464.050 900.000 ;
    END
  END h_in[91]
  PIN h_in[92]
    DIRECTION INPUT ;
    USE SIGNAL ;
    ANTENNAGATEAREA 0.631200 ;
    ANTENNADIFFAREA 0.434700 ;
    PORT
      LAYER met2 ;
        RECT 363.950 896.000 364.230 900.000 ;
    END
  END h_in[92]
  PIN h_in[93]
    DIRECTION INPUT ;
    USE SIGNAL ;
    ANTENNAGATEAREA 0.631200 ;
    ANTENNADIFFAREA 0.434700 ;
    PORT
      LAYER met2 ;
        RECT 315.650 896.000 315.930 900.000 ;
    END
  END h_in[93]
  PIN h_in[94]
    DIRECTION INPUT ;
    USE SIGNAL ;
    ANTENNAGATEAREA 0.631200 ;
    ANTENNADIFFAREA 0.434700 ;
    PORT
      LAYER met2 ;
        RECT 341.410 896.000 341.690 900.000 ;
    END
  END h_in[94]
  PIN h_in[95]
    DIRECTION INPUT ;
    USE SIGNAL ;
    ANTENNAGATEAREA 0.631200 ;
    ANTENNADIFFAREA 0.434700 ;
    PORT
      LAYER met2 ;
        RECT 338.190 896.000 338.470 900.000 ;
    END
  END h_in[95]
  PIN h_in[96]
    DIRECTION INPUT ;
    USE SIGNAL ;
    ANTENNAGATEAREA 0.647700 ;
    ANTENNADIFFAREA 0.434700 ;
    PORT
      LAYER met2 ;
        RECT 798.650 0.000 798.930 4.000 ;
    END
  END h_in[96]
  PIN h_in[97]
    DIRECTION INPUT ;
    USE SIGNAL ;
    ANTENNAGATEAREA 0.647700 ;
    ANTENNADIFFAREA 0.434700 ;
    PORT
      LAYER met2 ;
        RECT 846.950 0.000 847.230 4.000 ;
    END
  END h_in[97]
  PIN h_in[98]
    DIRECTION INPUT ;
    USE SIGNAL ;
    ANTENNAGATEAREA 0.593700 ;
    ANTENNADIFFAREA 0.434700 ;
    PORT
      LAYER met2 ;
        RECT 882.370 0.000 882.650 4.000 ;
    END
  END h_in[98]
  PIN h_in[99]
    DIRECTION INPUT ;
    USE SIGNAL ;
    ANTENNAGATEAREA 0.647700 ;
    ANTENNADIFFAREA 0.434700 ;
    PORT
      LAYER met3 ;
        RECT 896.000 176.840 900.000 177.440 ;
    END
  END h_in[99]
  PIN h_in[9]
    DIRECTION INPUT ;
    USE SIGNAL ;
    ANTENNAGATEAREA 0.647700 ;
    ANTENNADIFFAREA 0.434700 ;
    PORT
      LAYER met3 ;
        RECT 896.000 139.440 900.000 140.040 ;
    END
  END h_in[9]
  PIN rst_n
    DIRECTION INPUT ;
    USE SIGNAL ;
    ANTENNAGATEAREA 0.860700 ;
    ANTENNADIFFAREA 0.434700 ;
    PORT
      LAYER met3 ;
        RECT 896.000 285.640 900.000 286.240 ;
    END
  END rst_n
  PIN start
    DIRECTION INPUT ;
    USE SIGNAL ;
    ANTENNAGATEAREA 1.286700 ;
    ANTENNADIFFAREA 0.434700 ;
    PORT
      LAYER met2 ;
        RECT 714.930 896.000 715.210 900.000 ;
    END
  END start
  OBS
      LAYER nwell ;
        RECT 5.330 10.795 894.430 886.805 ;
      LAYER li1 ;
        RECT 5.520 10.795 894.240 886.805 ;
      LAYER met1 ;
        RECT 0.070 0.380 898.770 889.740 ;
      LAYER met2 ;
        RECT 0.650 895.720 3.030 898.125 ;
        RECT 3.870 895.720 6.250 898.125 ;
        RECT 7.090 895.720 9.470 898.125 ;
        RECT 10.310 895.720 12.690 898.125 ;
        RECT 13.530 895.720 15.910 898.125 ;
        RECT 16.750 895.720 19.130 898.125 ;
        RECT 19.970 895.720 22.350 898.125 ;
        RECT 23.190 895.720 25.570 898.125 ;
        RECT 26.410 895.720 28.790 898.125 ;
        RECT 29.630 895.720 32.010 898.125 ;
        RECT 32.850 895.720 35.230 898.125 ;
        RECT 36.070 895.720 38.450 898.125 ;
        RECT 39.290 895.720 41.670 898.125 ;
        RECT 42.510 895.720 44.890 898.125 ;
        RECT 45.730 895.720 48.110 898.125 ;
        RECT 48.950 895.720 51.330 898.125 ;
        RECT 52.170 895.720 54.550 898.125 ;
        RECT 55.390 895.720 57.770 898.125 ;
        RECT 58.610 895.720 60.990 898.125 ;
        RECT 61.830 895.720 64.210 898.125 ;
        RECT 65.050 895.720 67.430 898.125 ;
        RECT 68.270 895.720 70.650 898.125 ;
        RECT 71.490 895.720 73.870 898.125 ;
        RECT 74.710 895.720 77.090 898.125 ;
        RECT 77.930 895.720 80.310 898.125 ;
        RECT 81.150 895.720 83.530 898.125 ;
        RECT 84.370 895.720 86.750 898.125 ;
        RECT 87.590 895.720 89.970 898.125 ;
        RECT 90.810 895.720 93.190 898.125 ;
        RECT 94.030 895.720 96.410 898.125 ;
        RECT 97.250 895.720 99.630 898.125 ;
        RECT 100.470 895.720 102.850 898.125 ;
        RECT 103.690 895.720 106.070 898.125 ;
        RECT 106.910 895.720 109.290 898.125 ;
        RECT 110.130 895.720 112.510 898.125 ;
        RECT 113.350 895.720 115.730 898.125 ;
        RECT 116.570 895.720 118.950 898.125 ;
        RECT 119.790 895.720 122.170 898.125 ;
        RECT 123.010 895.720 125.390 898.125 ;
        RECT 126.230 895.720 128.610 898.125 ;
        RECT 129.450 895.720 131.830 898.125 ;
        RECT 132.670 895.720 135.050 898.125 ;
        RECT 135.890 895.720 138.270 898.125 ;
        RECT 139.110 895.720 141.490 898.125 ;
        RECT 142.330 895.720 144.710 898.125 ;
        RECT 145.550 895.720 147.930 898.125 ;
        RECT 148.770 895.720 151.150 898.125 ;
        RECT 151.990 895.720 154.370 898.125 ;
        RECT 155.210 895.720 157.590 898.125 ;
        RECT 158.430 895.720 160.810 898.125 ;
        RECT 161.650 895.720 164.030 898.125 ;
        RECT 164.870 895.720 167.250 898.125 ;
        RECT 168.090 895.720 170.470 898.125 ;
        RECT 171.310 895.720 173.690 898.125 ;
        RECT 174.530 895.720 176.910 898.125 ;
        RECT 177.750 895.720 180.130 898.125 ;
        RECT 180.970 895.720 183.350 898.125 ;
        RECT 184.190 895.720 186.570 898.125 ;
        RECT 187.410 895.720 189.790 898.125 ;
        RECT 190.630 895.720 193.010 898.125 ;
        RECT 193.850 895.720 196.230 898.125 ;
        RECT 197.070 895.720 199.450 898.125 ;
        RECT 200.290 895.720 202.670 898.125 ;
        RECT 203.510 895.720 205.890 898.125 ;
        RECT 206.730 895.720 209.110 898.125 ;
        RECT 209.950 895.720 212.330 898.125 ;
        RECT 213.170 895.720 215.550 898.125 ;
        RECT 216.390 895.720 218.770 898.125 ;
        RECT 219.610 895.720 221.990 898.125 ;
        RECT 222.830 895.720 225.210 898.125 ;
        RECT 226.050 895.720 228.430 898.125 ;
        RECT 229.270 895.720 231.650 898.125 ;
        RECT 232.490 895.720 234.870 898.125 ;
        RECT 235.710 895.720 238.090 898.125 ;
        RECT 238.930 895.720 241.310 898.125 ;
        RECT 242.150 895.720 244.530 898.125 ;
        RECT 245.370 895.720 247.750 898.125 ;
        RECT 248.590 895.720 250.970 898.125 ;
        RECT 251.810 895.720 254.190 898.125 ;
        RECT 255.030 895.720 257.410 898.125 ;
        RECT 258.250 895.720 260.630 898.125 ;
        RECT 261.470 895.720 263.850 898.125 ;
        RECT 264.690 895.720 267.070 898.125 ;
        RECT 267.910 895.720 270.290 898.125 ;
        RECT 271.130 895.720 273.510 898.125 ;
        RECT 274.350 895.720 276.730 898.125 ;
        RECT 277.570 895.720 279.950 898.125 ;
        RECT 280.790 895.720 283.170 898.125 ;
        RECT 284.010 895.720 286.390 898.125 ;
        RECT 287.230 895.720 289.610 898.125 ;
        RECT 290.450 895.720 292.830 898.125 ;
        RECT 293.670 895.720 296.050 898.125 ;
        RECT 296.890 895.720 299.270 898.125 ;
        RECT 300.110 895.720 302.490 898.125 ;
        RECT 303.330 895.720 305.710 898.125 ;
        RECT 306.550 895.720 308.930 898.125 ;
        RECT 309.770 895.720 312.150 898.125 ;
        RECT 312.990 895.720 315.370 898.125 ;
        RECT 316.210 895.720 318.590 898.125 ;
        RECT 319.430 895.720 321.810 898.125 ;
        RECT 322.650 895.720 325.030 898.125 ;
        RECT 325.870 895.720 328.250 898.125 ;
        RECT 329.090 895.720 331.470 898.125 ;
        RECT 332.310 895.720 334.690 898.125 ;
        RECT 335.530 895.720 337.910 898.125 ;
        RECT 338.750 895.720 341.130 898.125 ;
        RECT 341.970 895.720 344.350 898.125 ;
        RECT 345.190 895.720 347.570 898.125 ;
        RECT 348.410 895.720 350.790 898.125 ;
        RECT 351.630 895.720 354.010 898.125 ;
        RECT 354.850 895.720 357.230 898.125 ;
        RECT 358.070 895.720 360.450 898.125 ;
        RECT 361.290 895.720 363.670 898.125 ;
        RECT 364.510 895.720 366.890 898.125 ;
        RECT 367.730 895.720 370.110 898.125 ;
        RECT 370.950 895.720 373.330 898.125 ;
        RECT 374.170 895.720 376.550 898.125 ;
        RECT 377.390 895.720 379.770 898.125 ;
        RECT 380.610 895.720 382.990 898.125 ;
        RECT 383.830 895.720 386.210 898.125 ;
        RECT 387.050 895.720 389.430 898.125 ;
        RECT 390.270 895.720 392.650 898.125 ;
        RECT 393.490 895.720 395.870 898.125 ;
        RECT 396.710 895.720 399.090 898.125 ;
        RECT 399.930 895.720 402.310 898.125 ;
        RECT 403.150 895.720 405.530 898.125 ;
        RECT 406.370 895.720 408.750 898.125 ;
        RECT 409.590 895.720 411.970 898.125 ;
        RECT 412.810 895.720 415.190 898.125 ;
        RECT 416.030 895.720 418.410 898.125 ;
        RECT 419.250 895.720 421.630 898.125 ;
        RECT 422.470 895.720 424.850 898.125 ;
        RECT 425.690 895.720 428.070 898.125 ;
        RECT 428.910 895.720 431.290 898.125 ;
        RECT 432.130 895.720 434.510 898.125 ;
        RECT 435.350 895.720 437.730 898.125 ;
        RECT 438.570 895.720 440.950 898.125 ;
        RECT 441.790 895.720 444.170 898.125 ;
        RECT 445.010 895.720 447.390 898.125 ;
        RECT 448.230 895.720 450.610 898.125 ;
        RECT 451.450 895.720 453.830 898.125 ;
        RECT 454.670 895.720 457.050 898.125 ;
        RECT 457.890 895.720 460.270 898.125 ;
        RECT 461.110 895.720 463.490 898.125 ;
        RECT 464.330 895.720 466.710 898.125 ;
        RECT 467.550 895.720 469.930 898.125 ;
        RECT 470.770 895.720 473.150 898.125 ;
        RECT 473.990 895.720 476.370 898.125 ;
        RECT 477.210 895.720 479.590 898.125 ;
        RECT 480.430 895.720 482.810 898.125 ;
        RECT 483.650 895.720 486.030 898.125 ;
        RECT 486.870 895.720 489.250 898.125 ;
        RECT 490.090 895.720 492.470 898.125 ;
        RECT 493.310 895.720 495.690 898.125 ;
        RECT 496.530 895.720 498.910 898.125 ;
        RECT 499.750 895.720 502.130 898.125 ;
        RECT 502.970 895.720 505.350 898.125 ;
        RECT 506.190 895.720 508.570 898.125 ;
        RECT 509.410 895.720 511.790 898.125 ;
        RECT 512.630 895.720 515.010 898.125 ;
        RECT 515.850 895.720 518.230 898.125 ;
        RECT 519.070 895.720 521.450 898.125 ;
        RECT 522.290 895.720 524.670 898.125 ;
        RECT 525.510 895.720 527.890 898.125 ;
        RECT 528.730 895.720 531.110 898.125 ;
        RECT 531.950 895.720 534.330 898.125 ;
        RECT 535.170 895.720 537.550 898.125 ;
        RECT 538.390 895.720 540.770 898.125 ;
        RECT 541.610 895.720 543.990 898.125 ;
        RECT 544.830 895.720 547.210 898.125 ;
        RECT 548.050 895.720 550.430 898.125 ;
        RECT 551.270 895.720 553.650 898.125 ;
        RECT 554.490 895.720 556.870 898.125 ;
        RECT 557.710 895.720 560.090 898.125 ;
        RECT 560.930 895.720 563.310 898.125 ;
        RECT 564.150 895.720 566.530 898.125 ;
        RECT 567.370 895.720 569.750 898.125 ;
        RECT 570.590 895.720 572.970 898.125 ;
        RECT 573.810 895.720 576.190 898.125 ;
        RECT 577.030 895.720 579.410 898.125 ;
        RECT 580.250 895.720 582.630 898.125 ;
        RECT 583.470 895.720 585.850 898.125 ;
        RECT 586.690 895.720 589.070 898.125 ;
        RECT 589.910 895.720 592.290 898.125 ;
        RECT 593.130 895.720 595.510 898.125 ;
        RECT 596.350 895.720 598.730 898.125 ;
        RECT 599.570 895.720 601.950 898.125 ;
        RECT 602.790 895.720 605.170 898.125 ;
        RECT 606.010 895.720 608.390 898.125 ;
        RECT 609.230 895.720 611.610 898.125 ;
        RECT 612.450 895.720 614.830 898.125 ;
        RECT 615.670 895.720 618.050 898.125 ;
        RECT 618.890 895.720 621.270 898.125 ;
        RECT 622.110 895.720 624.490 898.125 ;
        RECT 625.330 895.720 627.710 898.125 ;
        RECT 628.550 895.720 630.930 898.125 ;
        RECT 631.770 895.720 634.150 898.125 ;
        RECT 634.990 895.720 637.370 898.125 ;
        RECT 638.210 895.720 640.590 898.125 ;
        RECT 641.430 895.720 643.810 898.125 ;
        RECT 644.650 895.720 647.030 898.125 ;
        RECT 647.870 895.720 650.250 898.125 ;
        RECT 651.090 895.720 653.470 898.125 ;
        RECT 654.310 895.720 656.690 898.125 ;
        RECT 657.530 895.720 659.910 898.125 ;
        RECT 660.750 895.720 663.130 898.125 ;
        RECT 663.970 895.720 666.350 898.125 ;
        RECT 667.190 895.720 669.570 898.125 ;
        RECT 670.410 895.720 672.790 898.125 ;
        RECT 673.630 895.720 676.010 898.125 ;
        RECT 676.850 895.720 679.230 898.125 ;
        RECT 680.070 895.720 682.450 898.125 ;
        RECT 683.290 895.720 685.670 898.125 ;
        RECT 686.510 895.720 688.890 898.125 ;
        RECT 689.730 895.720 692.110 898.125 ;
        RECT 692.950 895.720 695.330 898.125 ;
        RECT 696.170 895.720 698.550 898.125 ;
        RECT 699.390 895.720 701.770 898.125 ;
        RECT 702.610 895.720 704.990 898.125 ;
        RECT 705.830 895.720 708.210 898.125 ;
        RECT 709.050 895.720 711.430 898.125 ;
        RECT 712.270 895.720 714.650 898.125 ;
        RECT 715.490 895.720 717.870 898.125 ;
        RECT 718.710 895.720 721.090 898.125 ;
        RECT 721.930 895.720 724.310 898.125 ;
        RECT 725.150 895.720 727.530 898.125 ;
        RECT 728.370 895.720 730.750 898.125 ;
        RECT 731.590 895.720 733.970 898.125 ;
        RECT 734.810 895.720 737.190 898.125 ;
        RECT 738.030 895.720 740.410 898.125 ;
        RECT 741.250 895.720 743.630 898.125 ;
        RECT 744.470 895.720 746.850 898.125 ;
        RECT 747.690 895.720 750.070 898.125 ;
        RECT 750.910 895.720 753.290 898.125 ;
        RECT 754.130 895.720 756.510 898.125 ;
        RECT 757.350 895.720 759.730 898.125 ;
        RECT 760.570 895.720 762.950 898.125 ;
        RECT 763.790 895.720 766.170 898.125 ;
        RECT 767.010 895.720 769.390 898.125 ;
        RECT 770.230 895.720 772.610 898.125 ;
        RECT 773.450 895.720 775.830 898.125 ;
        RECT 776.670 895.720 779.050 898.125 ;
        RECT 779.890 895.720 782.270 898.125 ;
        RECT 783.110 895.720 785.490 898.125 ;
        RECT 786.330 895.720 788.710 898.125 ;
        RECT 789.550 895.720 791.930 898.125 ;
        RECT 792.770 895.720 795.150 898.125 ;
        RECT 795.990 895.720 798.370 898.125 ;
        RECT 799.210 895.720 801.590 898.125 ;
        RECT 802.430 895.720 804.810 898.125 ;
        RECT 805.650 895.720 808.030 898.125 ;
        RECT 808.870 895.720 811.250 898.125 ;
        RECT 812.090 895.720 814.470 898.125 ;
        RECT 815.310 895.720 817.690 898.125 ;
        RECT 818.530 895.720 820.910 898.125 ;
        RECT 821.750 895.720 824.130 898.125 ;
        RECT 824.970 895.720 827.350 898.125 ;
        RECT 828.190 895.720 830.570 898.125 ;
        RECT 831.410 895.720 833.790 898.125 ;
        RECT 834.630 895.720 837.010 898.125 ;
        RECT 837.850 895.720 840.230 898.125 ;
        RECT 841.070 895.720 843.450 898.125 ;
        RECT 844.290 895.720 846.670 898.125 ;
        RECT 847.510 895.720 849.890 898.125 ;
        RECT 850.730 895.720 853.110 898.125 ;
        RECT 853.950 895.720 856.330 898.125 ;
        RECT 857.170 895.720 859.550 898.125 ;
        RECT 860.390 895.720 862.770 898.125 ;
        RECT 863.610 895.720 865.990 898.125 ;
        RECT 866.830 895.720 869.210 898.125 ;
        RECT 870.050 895.720 898.740 898.125 ;
        RECT 0.100 4.280 898.740 895.720 ;
        RECT 0.650 0.155 3.030 4.280 ;
        RECT 3.870 0.155 6.250 4.280 ;
        RECT 7.090 0.155 9.470 4.280 ;
        RECT 10.310 0.155 12.690 4.280 ;
        RECT 13.530 0.155 15.910 4.280 ;
        RECT 16.750 0.155 19.130 4.280 ;
        RECT 19.970 0.155 22.350 4.280 ;
        RECT 23.190 0.155 25.570 4.280 ;
        RECT 26.410 0.155 28.790 4.280 ;
        RECT 29.630 0.155 32.010 4.280 ;
        RECT 32.850 0.155 35.230 4.280 ;
        RECT 36.070 0.155 38.450 4.280 ;
        RECT 39.290 0.155 41.670 4.280 ;
        RECT 42.510 0.155 44.890 4.280 ;
        RECT 45.730 0.155 48.110 4.280 ;
        RECT 48.950 0.155 51.330 4.280 ;
        RECT 52.170 0.155 54.550 4.280 ;
        RECT 55.390 0.155 57.770 4.280 ;
        RECT 58.610 0.155 60.990 4.280 ;
        RECT 61.830 0.155 64.210 4.280 ;
        RECT 65.050 0.155 67.430 4.280 ;
        RECT 68.270 0.155 70.650 4.280 ;
        RECT 71.490 0.155 73.870 4.280 ;
        RECT 74.710 0.155 77.090 4.280 ;
        RECT 77.930 0.155 80.310 4.280 ;
        RECT 81.150 0.155 83.530 4.280 ;
        RECT 84.370 0.155 86.750 4.280 ;
        RECT 87.590 0.155 89.970 4.280 ;
        RECT 90.810 0.155 93.190 4.280 ;
        RECT 94.030 0.155 96.410 4.280 ;
        RECT 97.250 0.155 99.630 4.280 ;
        RECT 100.470 0.155 102.850 4.280 ;
        RECT 103.690 0.155 106.070 4.280 ;
        RECT 106.910 0.155 109.290 4.280 ;
        RECT 110.130 0.155 112.510 4.280 ;
        RECT 113.350 0.155 115.730 4.280 ;
        RECT 116.570 0.155 118.950 4.280 ;
        RECT 119.790 0.155 122.170 4.280 ;
        RECT 123.010 0.155 125.390 4.280 ;
        RECT 126.230 0.155 128.610 4.280 ;
        RECT 129.450 0.155 131.830 4.280 ;
        RECT 132.670 0.155 135.050 4.280 ;
        RECT 135.890 0.155 138.270 4.280 ;
        RECT 139.110 0.155 141.490 4.280 ;
        RECT 142.330 0.155 144.710 4.280 ;
        RECT 145.550 0.155 147.930 4.280 ;
        RECT 148.770 0.155 151.150 4.280 ;
        RECT 151.990 0.155 154.370 4.280 ;
        RECT 155.210 0.155 157.590 4.280 ;
        RECT 158.430 0.155 160.810 4.280 ;
        RECT 161.650 0.155 164.030 4.280 ;
        RECT 164.870 0.155 167.250 4.280 ;
        RECT 168.090 0.155 170.470 4.280 ;
        RECT 171.310 0.155 173.690 4.280 ;
        RECT 174.530 0.155 176.910 4.280 ;
        RECT 177.750 0.155 180.130 4.280 ;
        RECT 180.970 0.155 183.350 4.280 ;
        RECT 184.190 0.155 186.570 4.280 ;
        RECT 187.410 0.155 189.790 4.280 ;
        RECT 190.630 0.155 193.010 4.280 ;
        RECT 193.850 0.155 196.230 4.280 ;
        RECT 197.070 0.155 199.450 4.280 ;
        RECT 200.290 0.155 202.670 4.280 ;
        RECT 203.510 0.155 205.890 4.280 ;
        RECT 206.730 0.155 209.110 4.280 ;
        RECT 209.950 0.155 212.330 4.280 ;
        RECT 213.170 0.155 215.550 4.280 ;
        RECT 216.390 0.155 218.770 4.280 ;
        RECT 219.610 0.155 221.990 4.280 ;
        RECT 222.830 0.155 225.210 4.280 ;
        RECT 226.050 0.155 228.430 4.280 ;
        RECT 229.270 0.155 231.650 4.280 ;
        RECT 232.490 0.155 234.870 4.280 ;
        RECT 235.710 0.155 238.090 4.280 ;
        RECT 238.930 0.155 241.310 4.280 ;
        RECT 242.150 0.155 244.530 4.280 ;
        RECT 245.370 0.155 247.750 4.280 ;
        RECT 248.590 0.155 250.970 4.280 ;
        RECT 251.810 0.155 254.190 4.280 ;
        RECT 255.030 0.155 257.410 4.280 ;
        RECT 258.250 0.155 260.630 4.280 ;
        RECT 261.470 0.155 263.850 4.280 ;
        RECT 264.690 0.155 267.070 4.280 ;
        RECT 267.910 0.155 270.290 4.280 ;
        RECT 271.130 0.155 273.510 4.280 ;
        RECT 274.350 0.155 276.730 4.280 ;
        RECT 277.570 0.155 279.950 4.280 ;
        RECT 280.790 0.155 283.170 4.280 ;
        RECT 284.010 0.155 286.390 4.280 ;
        RECT 287.230 0.155 289.610 4.280 ;
        RECT 290.450 0.155 292.830 4.280 ;
        RECT 293.670 0.155 296.050 4.280 ;
        RECT 296.890 0.155 299.270 4.280 ;
        RECT 300.110 0.155 302.490 4.280 ;
        RECT 303.330 0.155 305.710 4.280 ;
        RECT 306.550 0.155 308.930 4.280 ;
        RECT 309.770 0.155 312.150 4.280 ;
        RECT 312.990 0.155 315.370 4.280 ;
        RECT 316.210 0.155 318.590 4.280 ;
        RECT 319.430 0.155 321.810 4.280 ;
        RECT 322.650 0.155 325.030 4.280 ;
        RECT 325.870 0.155 328.250 4.280 ;
        RECT 329.090 0.155 331.470 4.280 ;
        RECT 332.310 0.155 334.690 4.280 ;
        RECT 335.530 0.155 337.910 4.280 ;
        RECT 338.750 0.155 341.130 4.280 ;
        RECT 341.970 0.155 344.350 4.280 ;
        RECT 345.190 0.155 347.570 4.280 ;
        RECT 348.410 0.155 350.790 4.280 ;
        RECT 351.630 0.155 354.010 4.280 ;
        RECT 354.850 0.155 357.230 4.280 ;
        RECT 358.070 0.155 360.450 4.280 ;
        RECT 361.290 0.155 363.670 4.280 ;
        RECT 364.510 0.155 366.890 4.280 ;
        RECT 367.730 0.155 370.110 4.280 ;
        RECT 370.950 0.155 373.330 4.280 ;
        RECT 374.170 0.155 376.550 4.280 ;
        RECT 377.390 0.155 379.770 4.280 ;
        RECT 380.610 0.155 382.990 4.280 ;
        RECT 383.830 0.155 386.210 4.280 ;
        RECT 387.050 0.155 389.430 4.280 ;
        RECT 390.270 0.155 392.650 4.280 ;
        RECT 393.490 0.155 395.870 4.280 ;
        RECT 396.710 0.155 399.090 4.280 ;
        RECT 399.930 0.155 402.310 4.280 ;
        RECT 403.150 0.155 405.530 4.280 ;
        RECT 406.370 0.155 408.750 4.280 ;
        RECT 409.590 0.155 411.970 4.280 ;
        RECT 412.810 0.155 415.190 4.280 ;
        RECT 416.030 0.155 418.410 4.280 ;
        RECT 419.250 0.155 421.630 4.280 ;
        RECT 422.470 0.155 424.850 4.280 ;
        RECT 425.690 0.155 428.070 4.280 ;
        RECT 428.910 0.155 431.290 4.280 ;
        RECT 432.130 0.155 434.510 4.280 ;
        RECT 435.350 0.155 437.730 4.280 ;
        RECT 438.570 0.155 440.950 4.280 ;
        RECT 441.790 0.155 444.170 4.280 ;
        RECT 445.010 0.155 447.390 4.280 ;
        RECT 448.230 0.155 450.610 4.280 ;
        RECT 451.450 0.155 453.830 4.280 ;
        RECT 454.670 0.155 457.050 4.280 ;
        RECT 457.890 0.155 460.270 4.280 ;
        RECT 461.110 0.155 463.490 4.280 ;
        RECT 464.330 0.155 466.710 4.280 ;
        RECT 467.550 0.155 469.930 4.280 ;
        RECT 470.770 0.155 473.150 4.280 ;
        RECT 473.990 0.155 476.370 4.280 ;
        RECT 477.210 0.155 479.590 4.280 ;
        RECT 480.430 0.155 482.810 4.280 ;
        RECT 483.650 0.155 486.030 4.280 ;
        RECT 486.870 0.155 489.250 4.280 ;
        RECT 490.090 0.155 492.470 4.280 ;
        RECT 493.310 0.155 495.690 4.280 ;
        RECT 496.530 0.155 498.910 4.280 ;
        RECT 499.750 0.155 502.130 4.280 ;
        RECT 502.970 0.155 505.350 4.280 ;
        RECT 506.190 0.155 508.570 4.280 ;
        RECT 509.410 0.155 511.790 4.280 ;
        RECT 512.630 0.155 515.010 4.280 ;
        RECT 515.850 0.155 518.230 4.280 ;
        RECT 519.070 0.155 521.450 4.280 ;
        RECT 522.290 0.155 524.670 4.280 ;
        RECT 525.510 0.155 527.890 4.280 ;
        RECT 528.730 0.155 531.110 4.280 ;
        RECT 531.950 0.155 534.330 4.280 ;
        RECT 535.170 0.155 537.550 4.280 ;
        RECT 538.390 0.155 540.770 4.280 ;
        RECT 541.610 0.155 543.990 4.280 ;
        RECT 544.830 0.155 547.210 4.280 ;
        RECT 548.050 0.155 550.430 4.280 ;
        RECT 551.270 0.155 553.650 4.280 ;
        RECT 554.490 0.155 556.870 4.280 ;
        RECT 557.710 0.155 560.090 4.280 ;
        RECT 560.930 0.155 563.310 4.280 ;
        RECT 564.150 0.155 566.530 4.280 ;
        RECT 567.370 0.155 569.750 4.280 ;
        RECT 570.590 0.155 572.970 4.280 ;
        RECT 573.810 0.155 576.190 4.280 ;
        RECT 577.030 0.155 579.410 4.280 ;
        RECT 580.250 0.155 582.630 4.280 ;
        RECT 583.470 0.155 585.850 4.280 ;
        RECT 586.690 0.155 589.070 4.280 ;
        RECT 589.910 0.155 592.290 4.280 ;
        RECT 593.130 0.155 595.510 4.280 ;
        RECT 596.350 0.155 598.730 4.280 ;
        RECT 599.570 0.155 601.950 4.280 ;
        RECT 602.790 0.155 605.170 4.280 ;
        RECT 606.010 0.155 608.390 4.280 ;
        RECT 609.230 0.155 611.610 4.280 ;
        RECT 612.450 0.155 614.830 4.280 ;
        RECT 615.670 0.155 618.050 4.280 ;
        RECT 618.890 0.155 621.270 4.280 ;
        RECT 622.110 0.155 624.490 4.280 ;
        RECT 625.330 0.155 627.710 4.280 ;
        RECT 628.550 0.155 630.930 4.280 ;
        RECT 631.770 0.155 634.150 4.280 ;
        RECT 634.990 0.155 637.370 4.280 ;
        RECT 638.210 0.155 640.590 4.280 ;
        RECT 641.430 0.155 643.810 4.280 ;
        RECT 644.650 0.155 647.030 4.280 ;
        RECT 647.870 0.155 650.250 4.280 ;
        RECT 651.090 0.155 653.470 4.280 ;
        RECT 654.310 0.155 656.690 4.280 ;
        RECT 657.530 0.155 659.910 4.280 ;
        RECT 660.750 0.155 663.130 4.280 ;
        RECT 663.970 0.155 666.350 4.280 ;
        RECT 667.190 0.155 669.570 4.280 ;
        RECT 670.410 0.155 672.790 4.280 ;
        RECT 673.630 0.155 676.010 4.280 ;
        RECT 676.850 0.155 679.230 4.280 ;
        RECT 680.070 0.155 682.450 4.280 ;
        RECT 683.290 0.155 685.670 4.280 ;
        RECT 686.510 0.155 688.890 4.280 ;
        RECT 689.730 0.155 692.110 4.280 ;
        RECT 692.950 0.155 695.330 4.280 ;
        RECT 696.170 0.155 698.550 4.280 ;
        RECT 699.390 0.155 701.770 4.280 ;
        RECT 702.610 0.155 704.990 4.280 ;
        RECT 705.830 0.155 708.210 4.280 ;
        RECT 709.050 0.155 711.430 4.280 ;
        RECT 712.270 0.155 714.650 4.280 ;
        RECT 715.490 0.155 717.870 4.280 ;
        RECT 718.710 0.155 721.090 4.280 ;
        RECT 721.930 0.155 724.310 4.280 ;
        RECT 725.150 0.155 727.530 4.280 ;
        RECT 728.370 0.155 730.750 4.280 ;
        RECT 731.590 0.155 733.970 4.280 ;
        RECT 734.810 0.155 737.190 4.280 ;
        RECT 738.030 0.155 740.410 4.280 ;
        RECT 741.250 0.155 743.630 4.280 ;
        RECT 744.470 0.155 746.850 4.280 ;
        RECT 747.690 0.155 750.070 4.280 ;
        RECT 750.910 0.155 753.290 4.280 ;
        RECT 754.130 0.155 756.510 4.280 ;
        RECT 757.350 0.155 759.730 4.280 ;
        RECT 760.570 0.155 762.950 4.280 ;
        RECT 763.790 0.155 766.170 4.280 ;
        RECT 767.010 0.155 769.390 4.280 ;
        RECT 770.230 0.155 772.610 4.280 ;
        RECT 773.450 0.155 775.830 4.280 ;
        RECT 776.670 0.155 779.050 4.280 ;
        RECT 779.890 0.155 782.270 4.280 ;
        RECT 783.110 0.155 785.490 4.280 ;
        RECT 786.330 0.155 788.710 4.280 ;
        RECT 789.550 0.155 791.930 4.280 ;
        RECT 792.770 0.155 795.150 4.280 ;
        RECT 795.990 0.155 798.370 4.280 ;
        RECT 799.210 0.155 801.590 4.280 ;
        RECT 802.430 0.155 804.810 4.280 ;
        RECT 805.650 0.155 808.030 4.280 ;
        RECT 808.870 0.155 811.250 4.280 ;
        RECT 812.090 0.155 814.470 4.280 ;
        RECT 815.310 0.155 817.690 4.280 ;
        RECT 818.530 0.155 820.910 4.280 ;
        RECT 821.750 0.155 824.130 4.280 ;
        RECT 824.970 0.155 827.350 4.280 ;
        RECT 828.190 0.155 830.570 4.280 ;
        RECT 831.410 0.155 833.790 4.280 ;
        RECT 834.630 0.155 837.010 4.280 ;
        RECT 837.850 0.155 840.230 4.280 ;
        RECT 841.070 0.155 843.450 4.280 ;
        RECT 844.290 0.155 846.670 4.280 ;
        RECT 847.510 0.155 849.890 4.280 ;
        RECT 850.730 0.155 853.110 4.280 ;
        RECT 853.950 0.155 856.330 4.280 ;
        RECT 857.170 0.155 859.550 4.280 ;
        RECT 860.390 0.155 862.770 4.280 ;
        RECT 863.610 0.155 865.990 4.280 ;
        RECT 866.830 0.155 869.210 4.280 ;
        RECT 870.050 0.155 872.430 4.280 ;
        RECT 873.270 0.155 875.650 4.280 ;
        RECT 876.490 0.155 878.870 4.280 ;
        RECT 879.710 0.155 882.090 4.280 ;
        RECT 882.930 0.155 885.310 4.280 ;
        RECT 886.150 0.155 888.530 4.280 ;
        RECT 889.370 0.155 891.750 4.280 ;
        RECT 892.590 0.155 894.970 4.280 ;
        RECT 895.810 0.155 898.190 4.280 ;
      LAYER met3 ;
        RECT 4.400 897.240 896.000 898.105 ;
        RECT 3.990 895.240 896.000 897.240 ;
        RECT 4.400 893.840 896.000 895.240 ;
        RECT 3.990 891.840 896.000 893.840 ;
        RECT 4.400 890.440 896.000 891.840 ;
        RECT 3.990 888.440 896.000 890.440 ;
        RECT 4.400 887.040 896.000 888.440 ;
        RECT 3.990 885.040 896.000 887.040 ;
        RECT 4.400 883.640 896.000 885.040 ;
        RECT 3.990 881.640 896.000 883.640 ;
        RECT 4.400 880.240 896.000 881.640 ;
        RECT 3.990 878.240 896.000 880.240 ;
        RECT 4.400 876.840 896.000 878.240 ;
        RECT 3.990 874.840 896.000 876.840 ;
        RECT 4.400 873.440 896.000 874.840 ;
        RECT 3.990 871.440 896.000 873.440 ;
        RECT 4.400 870.040 896.000 871.440 ;
        RECT 3.990 868.040 896.000 870.040 ;
        RECT 4.400 866.640 896.000 868.040 ;
        RECT 3.990 864.640 896.000 866.640 ;
        RECT 4.400 863.240 896.000 864.640 ;
        RECT 3.990 861.240 896.000 863.240 ;
        RECT 4.400 859.840 896.000 861.240 ;
        RECT 3.990 857.840 896.000 859.840 ;
        RECT 4.400 856.440 896.000 857.840 ;
        RECT 3.990 854.440 896.000 856.440 ;
        RECT 4.400 853.040 896.000 854.440 ;
        RECT 3.990 851.040 896.000 853.040 ;
        RECT 4.400 849.640 896.000 851.040 ;
        RECT 3.990 847.640 896.000 849.640 ;
        RECT 4.400 846.240 896.000 847.640 ;
        RECT 3.990 844.240 896.000 846.240 ;
        RECT 4.400 842.840 896.000 844.240 ;
        RECT 3.990 840.840 896.000 842.840 ;
        RECT 4.400 839.440 896.000 840.840 ;
        RECT 3.990 837.440 896.000 839.440 ;
        RECT 4.400 836.040 896.000 837.440 ;
        RECT 3.990 834.040 896.000 836.040 ;
        RECT 4.400 832.640 896.000 834.040 ;
        RECT 3.990 830.640 896.000 832.640 ;
        RECT 4.400 829.240 896.000 830.640 ;
        RECT 3.990 827.240 896.000 829.240 ;
        RECT 4.400 825.840 896.000 827.240 ;
        RECT 3.990 823.840 896.000 825.840 ;
        RECT 4.400 822.440 896.000 823.840 ;
        RECT 3.990 820.440 896.000 822.440 ;
        RECT 4.400 819.040 896.000 820.440 ;
        RECT 3.990 817.040 896.000 819.040 ;
        RECT 4.400 815.640 896.000 817.040 ;
        RECT 3.990 813.640 896.000 815.640 ;
        RECT 4.400 812.240 896.000 813.640 ;
        RECT 3.990 810.240 896.000 812.240 ;
        RECT 4.400 808.840 896.000 810.240 ;
        RECT 3.990 806.840 896.000 808.840 ;
        RECT 4.400 805.440 896.000 806.840 ;
        RECT 3.990 803.440 896.000 805.440 ;
        RECT 4.400 802.040 896.000 803.440 ;
        RECT 3.990 800.040 896.000 802.040 ;
        RECT 4.400 798.640 896.000 800.040 ;
        RECT 3.990 796.640 896.000 798.640 ;
        RECT 4.400 795.240 896.000 796.640 ;
        RECT 3.990 793.240 896.000 795.240 ;
        RECT 4.400 791.840 896.000 793.240 ;
        RECT 3.990 789.840 896.000 791.840 ;
        RECT 4.400 788.440 896.000 789.840 ;
        RECT 3.990 786.440 896.000 788.440 ;
        RECT 4.400 785.040 896.000 786.440 ;
        RECT 3.990 783.040 896.000 785.040 ;
        RECT 4.400 781.640 895.600 783.040 ;
        RECT 3.990 779.640 896.000 781.640 ;
        RECT 4.400 778.240 895.600 779.640 ;
        RECT 3.990 776.240 896.000 778.240 ;
        RECT 4.400 774.840 895.600 776.240 ;
        RECT 3.990 772.840 896.000 774.840 ;
        RECT 4.400 771.440 895.600 772.840 ;
        RECT 3.990 769.440 896.000 771.440 ;
        RECT 4.400 768.040 895.600 769.440 ;
        RECT 3.990 766.040 896.000 768.040 ;
        RECT 4.400 764.640 895.600 766.040 ;
        RECT 3.990 762.640 896.000 764.640 ;
        RECT 4.400 761.240 895.600 762.640 ;
        RECT 3.990 759.240 896.000 761.240 ;
        RECT 4.400 757.840 895.600 759.240 ;
        RECT 3.990 755.840 896.000 757.840 ;
        RECT 4.400 754.440 895.600 755.840 ;
        RECT 3.990 752.440 896.000 754.440 ;
        RECT 4.400 751.040 895.600 752.440 ;
        RECT 3.990 749.040 896.000 751.040 ;
        RECT 4.400 747.640 895.600 749.040 ;
        RECT 3.990 745.640 896.000 747.640 ;
        RECT 4.400 744.240 895.600 745.640 ;
        RECT 3.990 742.240 896.000 744.240 ;
        RECT 4.400 740.840 895.600 742.240 ;
        RECT 3.990 738.840 896.000 740.840 ;
        RECT 4.400 737.440 895.600 738.840 ;
        RECT 3.990 735.440 896.000 737.440 ;
        RECT 4.400 734.040 895.600 735.440 ;
        RECT 3.990 732.040 896.000 734.040 ;
        RECT 4.400 730.640 895.600 732.040 ;
        RECT 3.990 728.640 896.000 730.640 ;
        RECT 4.400 727.240 895.600 728.640 ;
        RECT 3.990 725.240 896.000 727.240 ;
        RECT 4.400 723.840 895.600 725.240 ;
        RECT 3.990 721.840 896.000 723.840 ;
        RECT 4.400 720.440 895.600 721.840 ;
        RECT 3.990 718.440 896.000 720.440 ;
        RECT 4.400 717.040 895.600 718.440 ;
        RECT 3.990 715.040 896.000 717.040 ;
        RECT 4.400 713.640 895.600 715.040 ;
        RECT 3.990 711.640 896.000 713.640 ;
        RECT 4.400 710.240 895.600 711.640 ;
        RECT 3.990 708.240 896.000 710.240 ;
        RECT 4.400 706.840 895.600 708.240 ;
        RECT 3.990 704.840 896.000 706.840 ;
        RECT 4.400 703.440 895.600 704.840 ;
        RECT 3.990 701.440 896.000 703.440 ;
        RECT 4.400 700.040 895.600 701.440 ;
        RECT 3.990 698.040 896.000 700.040 ;
        RECT 4.400 696.640 895.600 698.040 ;
        RECT 3.990 694.640 896.000 696.640 ;
        RECT 4.400 693.240 895.600 694.640 ;
        RECT 3.990 691.240 896.000 693.240 ;
        RECT 4.400 689.840 895.600 691.240 ;
        RECT 3.990 687.840 896.000 689.840 ;
        RECT 4.400 686.440 895.600 687.840 ;
        RECT 3.990 684.440 896.000 686.440 ;
        RECT 4.400 683.040 895.600 684.440 ;
        RECT 3.990 681.040 896.000 683.040 ;
        RECT 4.400 679.640 895.600 681.040 ;
        RECT 3.990 677.640 896.000 679.640 ;
        RECT 4.400 676.240 895.600 677.640 ;
        RECT 3.990 674.240 896.000 676.240 ;
        RECT 4.400 672.840 895.600 674.240 ;
        RECT 3.990 670.840 896.000 672.840 ;
        RECT 4.400 669.440 895.600 670.840 ;
        RECT 3.990 667.440 896.000 669.440 ;
        RECT 4.400 666.040 895.600 667.440 ;
        RECT 3.990 664.040 896.000 666.040 ;
        RECT 4.400 662.640 895.600 664.040 ;
        RECT 3.990 660.640 896.000 662.640 ;
        RECT 4.400 659.240 895.600 660.640 ;
        RECT 3.990 657.240 896.000 659.240 ;
        RECT 4.400 655.840 895.600 657.240 ;
        RECT 3.990 653.840 896.000 655.840 ;
        RECT 4.400 652.440 895.600 653.840 ;
        RECT 3.990 650.440 896.000 652.440 ;
        RECT 4.400 649.040 895.600 650.440 ;
        RECT 3.990 647.040 896.000 649.040 ;
        RECT 4.400 645.640 895.600 647.040 ;
        RECT 3.990 643.640 896.000 645.640 ;
        RECT 4.400 642.240 895.600 643.640 ;
        RECT 3.990 640.240 896.000 642.240 ;
        RECT 4.400 638.840 895.600 640.240 ;
        RECT 3.990 636.840 896.000 638.840 ;
        RECT 4.400 635.440 895.600 636.840 ;
        RECT 3.990 633.440 896.000 635.440 ;
        RECT 4.400 632.040 895.600 633.440 ;
        RECT 3.990 630.040 896.000 632.040 ;
        RECT 4.400 628.640 895.600 630.040 ;
        RECT 3.990 626.640 896.000 628.640 ;
        RECT 4.400 625.240 895.600 626.640 ;
        RECT 3.990 623.240 896.000 625.240 ;
        RECT 4.400 621.840 895.600 623.240 ;
        RECT 3.990 619.840 896.000 621.840 ;
        RECT 4.400 618.440 895.600 619.840 ;
        RECT 3.990 616.440 896.000 618.440 ;
        RECT 4.400 615.040 895.600 616.440 ;
        RECT 3.990 613.040 896.000 615.040 ;
        RECT 4.400 611.640 895.600 613.040 ;
        RECT 3.990 609.640 896.000 611.640 ;
        RECT 4.400 608.240 895.600 609.640 ;
        RECT 3.990 606.240 896.000 608.240 ;
        RECT 4.400 604.840 895.600 606.240 ;
        RECT 3.990 602.840 896.000 604.840 ;
        RECT 4.400 601.440 895.600 602.840 ;
        RECT 3.990 599.440 896.000 601.440 ;
        RECT 4.400 598.040 895.600 599.440 ;
        RECT 3.990 596.040 896.000 598.040 ;
        RECT 4.400 594.640 895.600 596.040 ;
        RECT 3.990 592.640 896.000 594.640 ;
        RECT 4.400 591.240 895.600 592.640 ;
        RECT 3.990 589.240 896.000 591.240 ;
        RECT 4.400 587.840 895.600 589.240 ;
        RECT 3.990 585.840 896.000 587.840 ;
        RECT 4.400 584.440 895.600 585.840 ;
        RECT 3.990 582.440 896.000 584.440 ;
        RECT 4.400 581.040 895.600 582.440 ;
        RECT 3.990 579.040 896.000 581.040 ;
        RECT 4.400 577.640 895.600 579.040 ;
        RECT 3.990 575.640 896.000 577.640 ;
        RECT 4.400 574.240 895.600 575.640 ;
        RECT 3.990 572.240 896.000 574.240 ;
        RECT 4.400 570.840 895.600 572.240 ;
        RECT 3.990 568.840 896.000 570.840 ;
        RECT 4.400 567.440 895.600 568.840 ;
        RECT 3.990 565.440 896.000 567.440 ;
        RECT 4.400 564.040 895.600 565.440 ;
        RECT 3.990 562.040 896.000 564.040 ;
        RECT 4.400 560.640 895.600 562.040 ;
        RECT 3.990 558.640 896.000 560.640 ;
        RECT 4.400 557.240 895.600 558.640 ;
        RECT 3.990 555.240 896.000 557.240 ;
        RECT 4.400 553.840 895.600 555.240 ;
        RECT 3.990 551.840 896.000 553.840 ;
        RECT 4.400 550.440 895.600 551.840 ;
        RECT 3.990 548.440 896.000 550.440 ;
        RECT 4.400 547.040 895.600 548.440 ;
        RECT 3.990 545.040 896.000 547.040 ;
        RECT 4.400 543.640 895.600 545.040 ;
        RECT 3.990 541.640 896.000 543.640 ;
        RECT 4.400 540.240 895.600 541.640 ;
        RECT 3.990 538.240 896.000 540.240 ;
        RECT 4.400 536.840 895.600 538.240 ;
        RECT 3.990 534.840 896.000 536.840 ;
        RECT 4.400 533.440 895.600 534.840 ;
        RECT 3.990 531.440 896.000 533.440 ;
        RECT 4.400 530.040 895.600 531.440 ;
        RECT 3.990 528.040 896.000 530.040 ;
        RECT 4.400 526.640 895.600 528.040 ;
        RECT 3.990 524.640 896.000 526.640 ;
        RECT 4.400 523.240 895.600 524.640 ;
        RECT 3.990 521.240 896.000 523.240 ;
        RECT 4.400 519.840 895.600 521.240 ;
        RECT 3.990 517.840 896.000 519.840 ;
        RECT 4.400 516.440 895.600 517.840 ;
        RECT 3.990 514.440 896.000 516.440 ;
        RECT 4.400 513.040 895.600 514.440 ;
        RECT 3.990 511.040 896.000 513.040 ;
        RECT 4.400 509.640 895.600 511.040 ;
        RECT 3.990 507.640 896.000 509.640 ;
        RECT 4.400 506.240 895.600 507.640 ;
        RECT 3.990 504.240 896.000 506.240 ;
        RECT 4.400 502.840 895.600 504.240 ;
        RECT 3.990 500.840 896.000 502.840 ;
        RECT 4.400 499.440 895.600 500.840 ;
        RECT 3.990 497.440 896.000 499.440 ;
        RECT 4.400 496.040 895.600 497.440 ;
        RECT 3.990 494.040 896.000 496.040 ;
        RECT 4.400 492.640 895.600 494.040 ;
        RECT 3.990 490.640 896.000 492.640 ;
        RECT 4.400 489.240 895.600 490.640 ;
        RECT 3.990 487.240 896.000 489.240 ;
        RECT 4.400 485.840 895.600 487.240 ;
        RECT 3.990 483.840 896.000 485.840 ;
        RECT 4.400 482.440 895.600 483.840 ;
        RECT 3.990 480.440 896.000 482.440 ;
        RECT 4.400 479.040 895.600 480.440 ;
        RECT 3.990 477.040 896.000 479.040 ;
        RECT 4.400 475.640 895.600 477.040 ;
        RECT 3.990 473.640 896.000 475.640 ;
        RECT 4.400 472.240 895.600 473.640 ;
        RECT 3.990 470.240 896.000 472.240 ;
        RECT 4.400 468.840 895.600 470.240 ;
        RECT 3.990 466.840 896.000 468.840 ;
        RECT 4.400 465.440 895.600 466.840 ;
        RECT 3.990 463.440 896.000 465.440 ;
        RECT 4.400 462.040 895.600 463.440 ;
        RECT 3.990 460.040 896.000 462.040 ;
        RECT 4.400 458.640 895.600 460.040 ;
        RECT 3.990 456.640 896.000 458.640 ;
        RECT 4.400 455.240 895.600 456.640 ;
        RECT 3.990 453.240 896.000 455.240 ;
        RECT 4.400 451.840 895.600 453.240 ;
        RECT 3.990 449.840 896.000 451.840 ;
        RECT 4.400 448.440 895.600 449.840 ;
        RECT 3.990 446.440 896.000 448.440 ;
        RECT 4.400 445.040 895.600 446.440 ;
        RECT 3.990 443.040 896.000 445.040 ;
        RECT 4.400 441.640 895.600 443.040 ;
        RECT 3.990 439.640 896.000 441.640 ;
        RECT 4.400 438.240 895.600 439.640 ;
        RECT 3.990 436.240 896.000 438.240 ;
        RECT 4.400 434.840 895.600 436.240 ;
        RECT 3.990 432.840 896.000 434.840 ;
        RECT 4.400 431.440 895.600 432.840 ;
        RECT 3.990 429.440 896.000 431.440 ;
        RECT 4.400 428.040 895.600 429.440 ;
        RECT 3.990 426.040 896.000 428.040 ;
        RECT 4.400 424.640 895.600 426.040 ;
        RECT 3.990 422.640 896.000 424.640 ;
        RECT 4.400 421.240 895.600 422.640 ;
        RECT 3.990 419.240 896.000 421.240 ;
        RECT 4.400 417.840 895.600 419.240 ;
        RECT 3.990 415.840 896.000 417.840 ;
        RECT 4.400 414.440 895.600 415.840 ;
        RECT 3.990 412.440 896.000 414.440 ;
        RECT 4.400 411.040 895.600 412.440 ;
        RECT 3.990 409.040 896.000 411.040 ;
        RECT 4.400 407.640 895.600 409.040 ;
        RECT 3.990 405.640 896.000 407.640 ;
        RECT 4.400 404.240 895.600 405.640 ;
        RECT 3.990 402.240 896.000 404.240 ;
        RECT 4.400 400.840 895.600 402.240 ;
        RECT 3.990 398.840 896.000 400.840 ;
        RECT 4.400 397.440 895.600 398.840 ;
        RECT 3.990 395.440 896.000 397.440 ;
        RECT 4.400 394.040 895.600 395.440 ;
        RECT 3.990 392.040 896.000 394.040 ;
        RECT 4.400 390.640 895.600 392.040 ;
        RECT 3.990 388.640 896.000 390.640 ;
        RECT 4.400 387.240 895.600 388.640 ;
        RECT 3.990 385.240 896.000 387.240 ;
        RECT 4.400 383.840 895.600 385.240 ;
        RECT 3.990 381.840 896.000 383.840 ;
        RECT 4.400 380.440 895.600 381.840 ;
        RECT 3.990 378.440 896.000 380.440 ;
        RECT 4.400 377.040 895.600 378.440 ;
        RECT 3.990 375.040 896.000 377.040 ;
        RECT 4.400 373.640 895.600 375.040 ;
        RECT 3.990 371.640 896.000 373.640 ;
        RECT 4.400 370.240 895.600 371.640 ;
        RECT 3.990 368.240 896.000 370.240 ;
        RECT 4.400 366.840 895.600 368.240 ;
        RECT 3.990 364.840 896.000 366.840 ;
        RECT 4.400 363.440 895.600 364.840 ;
        RECT 3.990 361.440 896.000 363.440 ;
        RECT 4.400 360.040 895.600 361.440 ;
        RECT 3.990 358.040 896.000 360.040 ;
        RECT 4.400 356.640 895.600 358.040 ;
        RECT 3.990 354.640 896.000 356.640 ;
        RECT 4.400 353.240 895.600 354.640 ;
        RECT 3.990 351.240 896.000 353.240 ;
        RECT 4.400 349.840 895.600 351.240 ;
        RECT 3.990 347.840 896.000 349.840 ;
        RECT 4.400 346.440 895.600 347.840 ;
        RECT 3.990 344.440 896.000 346.440 ;
        RECT 4.400 343.040 895.600 344.440 ;
        RECT 3.990 341.040 896.000 343.040 ;
        RECT 4.400 339.640 895.600 341.040 ;
        RECT 3.990 337.640 896.000 339.640 ;
        RECT 4.400 336.240 895.600 337.640 ;
        RECT 3.990 334.240 896.000 336.240 ;
        RECT 4.400 332.840 895.600 334.240 ;
        RECT 3.990 330.840 896.000 332.840 ;
        RECT 4.400 329.440 895.600 330.840 ;
        RECT 3.990 327.440 896.000 329.440 ;
        RECT 4.400 326.040 895.600 327.440 ;
        RECT 3.990 324.040 896.000 326.040 ;
        RECT 4.400 322.640 895.600 324.040 ;
        RECT 3.990 320.640 896.000 322.640 ;
        RECT 4.400 319.240 895.600 320.640 ;
        RECT 3.990 317.240 896.000 319.240 ;
        RECT 4.400 315.840 895.600 317.240 ;
        RECT 3.990 313.840 896.000 315.840 ;
        RECT 4.400 312.440 895.600 313.840 ;
        RECT 3.990 310.440 896.000 312.440 ;
        RECT 4.400 309.040 895.600 310.440 ;
        RECT 3.990 307.040 896.000 309.040 ;
        RECT 4.400 305.640 895.600 307.040 ;
        RECT 3.990 303.640 896.000 305.640 ;
        RECT 4.400 302.240 895.600 303.640 ;
        RECT 3.990 300.240 896.000 302.240 ;
        RECT 4.400 298.840 895.600 300.240 ;
        RECT 3.990 296.840 896.000 298.840 ;
        RECT 4.400 295.440 895.600 296.840 ;
        RECT 3.990 293.440 896.000 295.440 ;
        RECT 4.400 292.040 895.600 293.440 ;
        RECT 3.990 290.040 896.000 292.040 ;
        RECT 4.400 288.640 895.600 290.040 ;
        RECT 3.990 286.640 896.000 288.640 ;
        RECT 4.400 285.240 895.600 286.640 ;
        RECT 3.990 283.240 896.000 285.240 ;
        RECT 4.400 281.840 895.600 283.240 ;
        RECT 3.990 279.840 896.000 281.840 ;
        RECT 4.400 278.440 895.600 279.840 ;
        RECT 3.990 276.440 896.000 278.440 ;
        RECT 4.400 275.040 895.600 276.440 ;
        RECT 3.990 273.040 896.000 275.040 ;
        RECT 4.400 271.640 895.600 273.040 ;
        RECT 3.990 269.640 896.000 271.640 ;
        RECT 4.400 268.240 895.600 269.640 ;
        RECT 3.990 266.240 896.000 268.240 ;
        RECT 4.400 264.840 895.600 266.240 ;
        RECT 3.990 262.840 896.000 264.840 ;
        RECT 4.400 261.440 895.600 262.840 ;
        RECT 3.990 259.440 896.000 261.440 ;
        RECT 4.400 258.040 895.600 259.440 ;
        RECT 3.990 256.040 896.000 258.040 ;
        RECT 4.400 254.640 895.600 256.040 ;
        RECT 3.990 252.640 896.000 254.640 ;
        RECT 4.400 251.240 895.600 252.640 ;
        RECT 3.990 249.240 896.000 251.240 ;
        RECT 4.400 247.840 895.600 249.240 ;
        RECT 3.990 245.840 896.000 247.840 ;
        RECT 4.400 244.440 895.600 245.840 ;
        RECT 3.990 242.440 896.000 244.440 ;
        RECT 4.400 241.040 895.600 242.440 ;
        RECT 3.990 239.040 896.000 241.040 ;
        RECT 4.400 237.640 895.600 239.040 ;
        RECT 3.990 235.640 896.000 237.640 ;
        RECT 4.400 234.240 895.600 235.640 ;
        RECT 3.990 232.240 896.000 234.240 ;
        RECT 4.400 230.840 895.600 232.240 ;
        RECT 3.990 228.840 896.000 230.840 ;
        RECT 4.400 227.440 895.600 228.840 ;
        RECT 3.990 225.440 896.000 227.440 ;
        RECT 4.400 224.040 895.600 225.440 ;
        RECT 3.990 222.040 896.000 224.040 ;
        RECT 4.400 220.640 895.600 222.040 ;
        RECT 3.990 218.640 896.000 220.640 ;
        RECT 4.400 217.240 895.600 218.640 ;
        RECT 3.990 215.240 896.000 217.240 ;
        RECT 4.400 213.840 895.600 215.240 ;
        RECT 3.990 211.840 896.000 213.840 ;
        RECT 4.400 210.440 895.600 211.840 ;
        RECT 3.990 208.440 896.000 210.440 ;
        RECT 4.400 207.040 895.600 208.440 ;
        RECT 3.990 205.040 896.000 207.040 ;
        RECT 4.400 203.640 895.600 205.040 ;
        RECT 3.990 201.640 896.000 203.640 ;
        RECT 4.400 200.240 895.600 201.640 ;
        RECT 3.990 198.240 896.000 200.240 ;
        RECT 4.400 196.840 895.600 198.240 ;
        RECT 3.990 194.840 896.000 196.840 ;
        RECT 4.400 193.440 895.600 194.840 ;
        RECT 3.990 191.440 896.000 193.440 ;
        RECT 4.400 190.040 895.600 191.440 ;
        RECT 3.990 188.040 896.000 190.040 ;
        RECT 4.400 186.640 895.600 188.040 ;
        RECT 3.990 184.640 896.000 186.640 ;
        RECT 4.400 183.240 895.600 184.640 ;
        RECT 3.990 181.240 896.000 183.240 ;
        RECT 4.400 179.840 895.600 181.240 ;
        RECT 3.990 177.840 896.000 179.840 ;
        RECT 4.400 176.440 895.600 177.840 ;
        RECT 3.990 174.440 896.000 176.440 ;
        RECT 4.400 173.040 895.600 174.440 ;
        RECT 3.990 171.040 896.000 173.040 ;
        RECT 4.400 169.640 895.600 171.040 ;
        RECT 3.990 167.640 896.000 169.640 ;
        RECT 4.400 166.240 895.600 167.640 ;
        RECT 3.990 164.240 896.000 166.240 ;
        RECT 4.400 162.840 895.600 164.240 ;
        RECT 3.990 160.840 896.000 162.840 ;
        RECT 4.400 159.440 895.600 160.840 ;
        RECT 3.990 157.440 896.000 159.440 ;
        RECT 4.400 156.040 895.600 157.440 ;
        RECT 3.990 154.040 896.000 156.040 ;
        RECT 4.400 152.640 895.600 154.040 ;
        RECT 3.990 150.640 896.000 152.640 ;
        RECT 4.400 149.240 895.600 150.640 ;
        RECT 3.990 147.240 896.000 149.240 ;
        RECT 4.400 145.840 895.600 147.240 ;
        RECT 3.990 143.840 896.000 145.840 ;
        RECT 4.400 142.440 895.600 143.840 ;
        RECT 3.990 140.440 896.000 142.440 ;
        RECT 4.400 139.040 895.600 140.440 ;
        RECT 3.990 137.040 896.000 139.040 ;
        RECT 4.400 135.640 895.600 137.040 ;
        RECT 3.990 133.640 896.000 135.640 ;
        RECT 4.400 132.240 895.600 133.640 ;
        RECT 3.990 130.240 896.000 132.240 ;
        RECT 4.400 128.840 895.600 130.240 ;
        RECT 3.990 126.840 896.000 128.840 ;
        RECT 4.400 125.440 895.600 126.840 ;
        RECT 3.990 123.440 896.000 125.440 ;
        RECT 4.400 122.040 895.600 123.440 ;
        RECT 3.990 120.040 896.000 122.040 ;
        RECT 4.400 118.640 895.600 120.040 ;
        RECT 3.990 116.640 896.000 118.640 ;
        RECT 4.400 115.240 895.600 116.640 ;
        RECT 3.990 113.240 896.000 115.240 ;
        RECT 4.400 111.840 895.600 113.240 ;
        RECT 3.990 109.840 896.000 111.840 ;
        RECT 4.400 108.440 895.600 109.840 ;
        RECT 3.990 106.440 896.000 108.440 ;
        RECT 4.400 105.040 895.600 106.440 ;
        RECT 3.990 103.040 896.000 105.040 ;
        RECT 4.400 101.640 895.600 103.040 ;
        RECT 3.990 99.640 896.000 101.640 ;
        RECT 4.400 98.240 895.600 99.640 ;
        RECT 3.990 96.240 896.000 98.240 ;
        RECT 4.400 94.840 895.600 96.240 ;
        RECT 3.990 92.840 896.000 94.840 ;
        RECT 4.400 91.440 895.600 92.840 ;
        RECT 3.990 89.440 896.000 91.440 ;
        RECT 4.400 88.040 895.600 89.440 ;
        RECT 3.990 86.040 896.000 88.040 ;
        RECT 4.400 84.640 895.600 86.040 ;
        RECT 3.990 82.640 896.000 84.640 ;
        RECT 4.400 81.240 895.600 82.640 ;
        RECT 3.990 79.240 896.000 81.240 ;
        RECT 4.400 77.840 895.600 79.240 ;
        RECT 3.990 75.840 896.000 77.840 ;
        RECT 4.400 74.440 895.600 75.840 ;
        RECT 3.990 72.440 896.000 74.440 ;
        RECT 4.400 71.040 895.600 72.440 ;
        RECT 3.990 69.040 896.000 71.040 ;
        RECT 4.400 67.640 895.600 69.040 ;
        RECT 3.990 65.640 896.000 67.640 ;
        RECT 4.400 64.240 895.600 65.640 ;
        RECT 3.990 62.240 896.000 64.240 ;
        RECT 4.400 60.840 895.600 62.240 ;
        RECT 3.990 58.840 896.000 60.840 ;
        RECT 4.400 57.440 896.000 58.840 ;
        RECT 3.990 55.440 896.000 57.440 ;
        RECT 4.400 54.040 896.000 55.440 ;
        RECT 3.990 52.040 896.000 54.040 ;
        RECT 4.400 50.640 896.000 52.040 ;
        RECT 3.990 48.640 896.000 50.640 ;
        RECT 4.400 47.240 896.000 48.640 ;
        RECT 3.990 45.240 896.000 47.240 ;
        RECT 4.400 43.840 896.000 45.240 ;
        RECT 3.990 41.840 896.000 43.840 ;
        RECT 4.400 40.440 896.000 41.840 ;
        RECT 3.990 38.440 896.000 40.440 ;
        RECT 4.400 37.040 896.000 38.440 ;
        RECT 3.990 35.040 896.000 37.040 ;
        RECT 4.400 33.640 896.000 35.040 ;
        RECT 3.990 31.640 896.000 33.640 ;
        RECT 4.400 30.240 896.000 31.640 ;
        RECT 3.990 28.240 896.000 30.240 ;
        RECT 4.400 26.840 896.000 28.240 ;
        RECT 3.990 24.840 896.000 26.840 ;
        RECT 4.400 23.440 896.000 24.840 ;
        RECT 3.990 21.440 896.000 23.440 ;
        RECT 4.400 20.040 896.000 21.440 ;
        RECT 3.990 18.040 896.000 20.040 ;
        RECT 4.400 16.640 896.000 18.040 ;
        RECT 3.990 14.640 896.000 16.640 ;
        RECT 4.400 13.240 896.000 14.640 ;
        RECT 3.990 11.240 896.000 13.240 ;
        RECT 4.400 9.840 896.000 11.240 ;
        RECT 3.990 7.840 896.000 9.840 ;
        RECT 4.400 6.440 896.000 7.840 ;
        RECT 3.990 4.440 896.000 6.440 ;
        RECT 4.400 3.040 896.000 4.440 ;
        RECT 3.990 1.040 896.000 3.040 ;
        RECT 4.400 0.175 896.000 1.040 ;
      LAYER met4 ;
        RECT 14.095 19.895 20.640 884.505 ;
        RECT 23.040 19.895 23.940 884.505 ;
        RECT 26.340 19.895 174.240 884.505 ;
        RECT 176.640 19.895 177.540 884.505 ;
        RECT 179.940 19.895 327.840 884.505 ;
        RECT 330.240 19.895 331.140 884.505 ;
        RECT 333.540 19.895 481.440 884.505 ;
        RECT 483.840 19.895 484.740 884.505 ;
        RECT 487.140 19.895 635.040 884.505 ;
        RECT 637.440 19.895 638.340 884.505 ;
        RECT 640.740 19.895 707.185 884.505 ;
  END
END sha256_core
END LIBRARY

